VERSION 5.8 ;
DIVIDERCHAR "/" ;
BUSBITCHARS "[]" ;
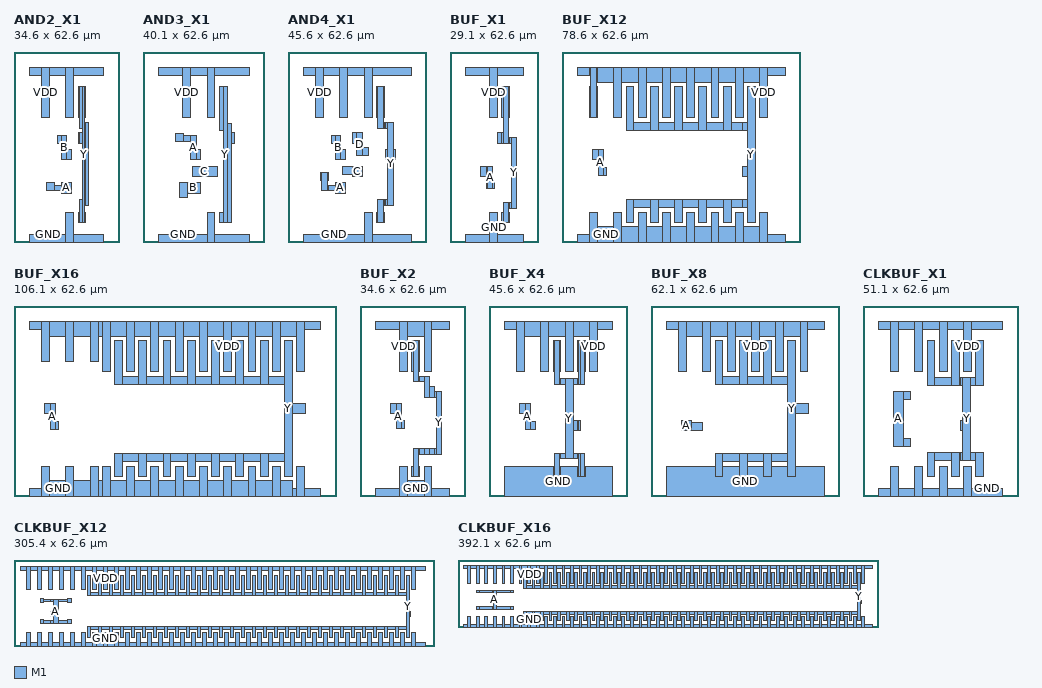
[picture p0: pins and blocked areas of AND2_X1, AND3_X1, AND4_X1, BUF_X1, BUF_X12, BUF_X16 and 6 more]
MACRO AND2_X1
  CLASS CORE ;
  ORIGIN 0 0 ;
  SIZE 34.600 BY 62.600 ;
  SYMMETRY X Y ;
  SITE TR1um_site ;
  PIN VDD
    DIRECTION INOUT ;
    USE POWER ;
    PORT
      LAYER M1 ;
        RECT 5.000 55.000 9.100 57.600 ;
      LAYER M1 ;
        RECT 9.100 41.000 11.700 57.600 ;
      LAYER M1 ;
        RECT 11.700 55.000 17.100 57.600 ;
      LAYER M1 ;
        RECT 17.100 41.000 19.700 57.600 ;
      LAYER M1 ;
        RECT 19.700 55.000 29.600 57.600 ;
    END
  END VDD
  PIN GND
    DIRECTION INOUT ;
    USE GROUND ;
    PORT
      LAYER M1 ;
        RECT 5.000 0.000 17.100 2.600 ;
      LAYER M1 ;
        RECT 17.100 0.000 19.700 9.800 ;
      LAYER M1 ;
        RECT 19.700 0.000 29.600 2.600 ;
    END
  END GND
  PIN Y
    DIRECTION OUTPUT ;
    USE SIGNAL ;
    PORT
      LAYER M1 ;
        RECT 21.100 6.400 21.500 9.800 ;
      LAYER M1 ;
        RECT 21.100 32.600 21.500 36.000 ;
      LAYER M1 ;
        RECT 21.100 41.000 21.500 51.200 ;
      LAYER M1 ;
        RECT 21.500 6.400 22.700 13.900 ;
      LAYER M1 ;
        RECT 21.500 32.600 22.700 36.000 ;
      LAYER M1 ;
        RECT 21.500 37.500 22.700 51.200 ;
      LAYER M1 ;
        RECT 22.700 6.400 23.300 51.200 ;
      LAYER M1 ;
        RECT 23.300 6.400 23.700 9.800 ;
      LAYER M1 ;
        RECT 23.300 12.100 23.700 39.300 ;
      LAYER M1 ;
        RECT 23.300 41.000 23.700 51.200 ;
      LAYER M1 ;
        RECT 23.700 12.100 24.500 39.300 ;
    END
  END Y
  PIN A
    DIRECTION INPUT ;
    USE SIGNAL ;
    PORT
      LAYER M1 ;
        RECT 10.600 16.900 13.200 19.500 ;
      LAYER M1 ;
        RECT 13.200 16.900 15.600 18.700 ;
      LAYER M1 ;
        RECT 15.600 16.100 19.000 19.500 ;
    END
  END A
  PIN B
    DIRECTION INPUT ;
    USE SIGNAL ;
    PORT
      LAYER M1 ;
        RECT 14.400 32.600 15.600 35.200 ;
      LAYER M1 ;
        RECT 15.600 27.100 17.400 35.200 ;
      LAYER M1 ;
        RECT 17.400 27.100 19.000 30.500 ;
    END
  END B
END AND2_X1
MACRO AND3_X1
  CLASS CORE ;
  ORIGIN 0 0 ;
  SIZE 40.100 BY 62.600 ;
  SYMMETRY X Y ;
  SITE TR1um_site ;
  PIN VDD
    DIRECTION INOUT ;
    USE POWER ;
    PORT
      LAYER M1 ;
        RECT 5.000 55.000 13.100 57.600 ;
      LAYER M1 ;
        RECT 13.100 41.000 15.700 57.600 ;
      LAYER M1 ;
        RECT 15.700 55.000 21.100 57.600 ;
      LAYER M1 ;
        RECT 21.100 41.000 23.700 57.600 ;
      LAYER M1 ;
        RECT 23.700 55.000 35.100 57.600 ;
    END
  END VDD
  PIN GND
    DIRECTION INOUT ;
    USE GROUND ;
    PORT
      LAYER M1 ;
        RECT 5.000 0.000 21.100 2.600 ;
      LAYER M1 ;
        RECT 21.100 0.000 23.700 9.800 ;
      LAYER M1 ;
        RECT 23.700 0.000 35.100 2.600 ;
    END
  END GND
  PIN Y
    DIRECTION OUTPUT ;
    USE SIGNAL ;
    PORT
      LAYER M1 ;
        RECT 25.100 6.400 26.600 9.800 ;
      LAYER M1 ;
        RECT 25.100 36.600 26.600 51.200 ;
      LAYER M1 ;
        RECT 26.600 6.400 27.700 51.200 ;
      LAYER M1 ;
        RECT 27.700 6.400 29.200 39.200 ;
      LAYER M1 ;
        RECT 29.200 32.600 30.000 36.000 ;
    END
  END Y
  PIN A
    DIRECTION INPUT ;
    USE SIGNAL ;
    PORT
      LAYER M1 ;
        RECT 10.700 33.200 13.300 35.800 ;
      LAYER M1 ;
        RECT 13.300 33.200 15.600 35.200 ;
      LAYER M1 ;
        RECT 15.600 27.100 17.600 35.200 ;
      LAYER M1 ;
        RECT 17.600 27.100 19.000 30.500 ;
    END
  END A
  PIN C
    DIRECTION INPUT ;
    USE SIGNAL ;
    PORT
      LAYER M1 ;
        RECT 16.300 21.600 24.500 25.000 ;
    END
  END C
  PIN B
    DIRECTION INPUT ;
    USE SIGNAL ;
    PORT
      LAYER M1 ;
        RECT 12.000 14.600 14.600 19.500 ;
      LAYER M1 ;
        RECT 14.600 16.100 19.000 19.500 ;
    END
  END B
END AND3_X1
MACRO AND4_X1
  CLASS CORE ;
  ORIGIN 0 0 ;
  SIZE 45.600 BY 62.600 ;
  SYMMETRY X Y ;
  SITE TR1um_site ;
  PIN VDD
    DIRECTION INOUT ;
    USE POWER ;
    PORT
      LAYER M1 ;
        RECT 5.000 55.000 9.100 57.600 ;
      LAYER M1 ;
        RECT 9.100 41.000 11.700 57.600 ;
      LAYER M1 ;
        RECT 11.700 55.000 17.100 57.600 ;
      LAYER M1 ;
        RECT 17.100 41.000 19.700 57.600 ;
      LAYER M1 ;
        RECT 19.700 55.000 25.100 57.600 ;
      LAYER M1 ;
        RECT 25.100 41.000 27.700 57.600 ;
      LAYER M1 ;
        RECT 27.700 55.000 40.600 57.600 ;
    END
  END VDD
  PIN GND
    DIRECTION INOUT ;
    USE GROUND ;
    PORT
      LAYER M1 ;
        RECT 5.000 0.000 25.100 2.600 ;
      LAYER M1 ;
        RECT 25.100 0.000 27.700 9.800 ;
      LAYER M1 ;
        RECT 27.700 0.000 40.600 2.600 ;
    END
  END GND
  PIN Y
    DIRECTION OUTPUT ;
    USE SIGNAL ;
    PORT
      LAYER M1 ;
        RECT 29.100 6.400 29.500 9.800 ;
      LAYER M1 ;
        RECT 29.100 41.000 29.500 51.200 ;
      LAYER M1 ;
        RECT 29.500 6.400 31.300 13.900 ;
      LAYER M1 ;
        RECT 29.500 37.500 31.300 51.200 ;
      LAYER M1 ;
        RECT 31.300 6.400 31.700 9.800 ;
      LAYER M1 ;
        RECT 31.300 12.100 31.700 13.900 ;
      LAYER M1 ;
        RECT 31.300 37.500 31.700 39.300 ;
      LAYER M1 ;
        RECT 31.300 41.000 31.700 51.200 ;
      LAYER M1 ;
        RECT 31.700 12.100 32.100 13.900 ;
      LAYER M1 ;
        RECT 31.700 37.500 32.100 39.300 ;
      LAYER M1 ;
        RECT 32.100 12.100 32.900 13.900 ;
      LAYER M1 ;
        RECT 32.100 27.100 32.900 30.500 ;
      LAYER M1 ;
        RECT 32.100 37.500 32.900 39.300 ;
      LAYER M1 ;
        RECT 32.900 12.100 34.700 39.300 ;
      LAYER M1 ;
        RECT 34.700 27.100 35.500 30.500 ;
    END
  END Y
  PIN A
    DIRECTION INPUT ;
    USE SIGNAL ;
    PORT
      LAYER M1 ;
        RECT 10.600 20.400 11.100 23.000 ;
      LAYER M1 ;
        RECT 11.100 16.900 12.900 23.000 ;
      LAYER M1 ;
        RECT 12.900 16.900 13.200 18.700 ;
      LAYER M1 ;
        RECT 12.900 20.400 13.200 23.000 ;
      LAYER M1 ;
        RECT 13.200 16.900 15.600 18.700 ;
      LAYER M1 ;
        RECT 15.600 16.100 19.000 19.500 ;
    END
  END A
  PIN B
    DIRECTION INPUT ;
    USE SIGNAL ;
    PORT
      LAYER M1 ;
        RECT 14.400 32.600 15.600 35.200 ;
      LAYER M1 ;
        RECT 15.600 27.100 17.400 35.200 ;
      LAYER M1 ;
        RECT 17.400 27.100 19.000 30.500 ;
    END
  END B
  PIN C
    DIRECTION INPUT ;
    USE SIGNAL ;
    PORT
      LAYER M1 ;
        RECT 17.900 22.400 21.100 25.000 ;
      LAYER M1 ;
        RECT 21.100 21.600 24.500 25.000 ;
    END
  END C
  PIN D
    DIRECTION INPUT ;
    USE SIGNAL ;
    PORT
      LAYER M1 ;
        RECT 21.100 32.600 22.700 36.000 ;
      LAYER M1 ;
        RECT 22.700 28.400 24.500 36.000 ;
      LAYER M1 ;
        RECT 24.500 28.400 26.400 31.000 ;
    END
  END D
END AND4_X1
MACRO BUF_X1
  CLASS CORE ;
  ORIGIN 0 0 ;
  SIZE 29.100 BY 62.600 ;
  SYMMETRY X Y ;
  SITE TR1um_site ;
  PIN VDD
    DIRECTION INOUT ;
    USE POWER ;
    PORT
      LAYER M1 ;
        RECT 5.000 55.000 13.100 57.600 ;
      LAYER M1 ;
        RECT 13.100 41.000 15.700 57.600 ;
      LAYER M1 ;
        RECT 15.700 55.000 24.100 57.600 ;
    END
  END VDD
  PIN GND
    DIRECTION INOUT ;
    USE GROUND ;
    PORT
      LAYER M1 ;
        RECT 5.000 0.000 13.100 2.600 ;
      LAYER M1 ;
        RECT 13.100 0.000 15.700 9.800 ;
      LAYER M1 ;
        RECT 15.700 0.000 24.100 2.600 ;
    END
  END GND
  PIN Y
    DIRECTION OUTPUT ;
    USE SIGNAL ;
    PORT
      LAYER M1 ;
        RECT 15.600 32.600 17.100 36.000 ;
      LAYER M1 ;
        RECT 17.100 6.400 17.500 9.800 ;
      LAYER M1 ;
        RECT 17.100 32.600 17.500 36.000 ;
      LAYER M1 ;
        RECT 17.100 41.000 17.500 51.200 ;
      LAYER M1 ;
        RECT 17.500 6.400 19.300 13.000 ;
      LAYER M1 ;
        RECT 17.500 32.600 19.300 51.200 ;
      LAYER M1 ;
        RECT 19.300 6.400 19.700 9.800 ;
      LAYER M1 ;
        RECT 19.300 11.200 19.700 13.000 ;
      LAYER M1 ;
        RECT 19.300 32.600 19.700 34.400 ;
      LAYER M1 ;
        RECT 19.300 41.000 19.700 51.200 ;
      LAYER M1 ;
        RECT 19.700 11.200 20.100 13.000 ;
      LAYER M1 ;
        RECT 19.700 32.600 20.100 34.400 ;
      LAYER M1 ;
        RECT 20.100 11.200 21.900 34.400 ;
    END
  END Y
  PIN A
    DIRECTION INPUT ;
    USE SIGNAL ;
    PORT
      LAYER M1 ;
        RECT 10.100 21.600 11.900 25.000 ;
      LAYER M1 ;
        RECT 11.900 17.600 12.300 20.200 ;
      LAYER M1 ;
        RECT 11.900 21.600 12.300 25.000 ;
      LAYER M1 ;
        RECT 12.300 17.600 14.100 25.000 ;
      LAYER M1 ;
        RECT 14.100 17.600 14.500 20.200 ;
    END
  END A
END BUF_X1
MACRO BUF_X12
  CLASS CORE ;
  ORIGIN 0 0 ;
  SIZE 78.600 BY 62.600 ;
  SYMMETRY X Y ;
  SITE TR1um_site ;
  PIN VDD
    DIRECTION INOUT ;
    USE POWER ;
    PORT
      LAYER M1 ;
        RECT 5.000 55.000 9.100 57.600 ;
      LAYER M1 ;
        RECT 9.100 41.000 9.500 51.200 ;
      LAYER M1 ;
        RECT 9.100 55.000 9.500 57.600 ;
      LAYER M1 ;
        RECT 9.500 41.000 11.300 57.600 ;
      LAYER M1 ;
        RECT 11.300 41.000 11.700 51.200 ;
      LAYER M1 ;
        RECT 11.300 52.600 11.700 57.600 ;
      LAYER M1 ;
        RECT 11.700 52.600 17.100 57.600 ;
      LAYER M1 ;
        RECT 17.100 41.000 19.700 57.600 ;
      LAYER M1 ;
        RECT 19.700 52.600 25.100 57.600 ;
      LAYER M1 ;
        RECT 25.100 41.000 27.700 57.600 ;
      LAYER M1 ;
        RECT 27.700 52.600 33.100 57.600 ;
      LAYER M1 ;
        RECT 33.100 41.000 35.700 57.600 ;
      LAYER M1 ;
        RECT 35.700 52.600 41.100 57.600 ;
      LAYER M1 ;
        RECT 41.100 41.000 43.700 57.600 ;
      LAYER M1 ;
        RECT 43.700 52.600 49.100 57.600 ;
      LAYER M1 ;
        RECT 49.100 41.000 51.700 57.600 ;
      LAYER M1 ;
        RECT 51.700 52.600 57.100 57.600 ;
      LAYER M1 ;
        RECT 57.100 41.000 59.700 57.600 ;
      LAYER M1 ;
        RECT 59.700 52.600 65.100 57.600 ;
      LAYER M1 ;
        RECT 65.100 41.000 67.700 57.600 ;
      LAYER M1 ;
        RECT 67.700 55.000 73.600 57.600 ;
    END
  END VDD
  PIN GND
    DIRECTION INOUT ;
    USE GROUND ;
    PORT
      LAYER M1 ;
        RECT 5.000 0.000 9.100 2.600 ;
      LAYER M1 ;
        RECT 9.100 0.000 11.700 9.800 ;
      LAYER M1 ;
        RECT 11.700 0.000 17.100 5.000 ;
      LAYER M1 ;
        RECT 17.100 0.000 19.700 9.800 ;
      LAYER M1 ;
        RECT 19.700 0.000 25.100 5.000 ;
      LAYER M1 ;
        RECT 25.100 0.000 27.700 9.800 ;
      LAYER M1 ;
        RECT 27.700 0.000 33.100 5.000 ;
      LAYER M1 ;
        RECT 33.100 0.000 35.700 9.800 ;
      LAYER M1 ;
        RECT 35.700 0.000 41.100 5.000 ;
      LAYER M1 ;
        RECT 41.100 0.000 43.700 9.800 ;
      LAYER M1 ;
        RECT 43.700 0.000 49.100 5.000 ;
      LAYER M1 ;
        RECT 49.100 0.000 51.700 9.800 ;
      LAYER M1 ;
        RECT 51.700 0.000 57.100 5.000 ;
      LAYER M1 ;
        RECT 57.100 0.000 59.700 9.800 ;
      LAYER M1 ;
        RECT 59.700 0.000 65.100 5.000 ;
      LAYER M1 ;
        RECT 65.100 0.000 67.700 9.800 ;
      LAYER M1 ;
        RECT 67.700 0.000 73.600 2.600 ;
    END
  END GND
  PIN Y
    DIRECTION OUTPUT ;
    USE SIGNAL ;
    PORT
      LAYER M1 ;
        RECT 21.100 6.400 23.700 14.000 ;
      LAYER M1 ;
        RECT 21.100 36.800 23.700 51.200 ;
      LAYER M1 ;
        RECT 23.700 11.400 29.100 14.000 ;
      LAYER M1 ;
        RECT 23.700 36.800 29.100 39.400 ;
      LAYER M1 ;
        RECT 29.100 6.400 31.700 14.000 ;
      LAYER M1 ;
        RECT 29.100 36.800 31.700 51.200 ;
      LAYER M1 ;
        RECT 31.700 11.400 37.100 14.000 ;
      LAYER M1 ;
        RECT 31.700 36.800 37.100 39.400 ;
      LAYER M1 ;
        RECT 37.100 6.400 39.700 14.000 ;
      LAYER M1 ;
        RECT 37.100 36.800 39.700 51.200 ;
      LAYER M1 ;
        RECT 39.700 11.400 45.100 14.000 ;
      LAYER M1 ;
        RECT 39.700 36.800 45.100 39.400 ;
      LAYER M1 ;
        RECT 45.100 6.400 47.700 14.000 ;
      LAYER M1 ;
        RECT 45.100 36.800 47.700 51.200 ;
      LAYER M1 ;
        RECT 47.700 11.400 53.100 14.000 ;
      LAYER M1 ;
        RECT 47.700 36.800 53.100 39.400 ;
      LAYER M1 ;
        RECT 53.100 6.400 55.700 14.000 ;
      LAYER M1 ;
        RECT 53.100 36.800 55.700 51.200 ;
      LAYER M1 ;
        RECT 55.700 11.400 59.600 14.000 ;
      LAYER M1 ;
        RECT 55.700 36.800 59.600 39.400 ;
      LAYER M1 ;
        RECT 59.600 11.400 61.100 14.000 ;
      LAYER M1 ;
        RECT 59.600 21.600 61.100 25.000 ;
      LAYER M1 ;
        RECT 59.600 36.800 61.100 39.400 ;
      LAYER M1 ;
        RECT 61.100 6.400 63.700 51.200 ;
    END
  END Y
  PIN A
    DIRECTION INPUT ;
    USE SIGNAL ;
    PORT
      LAYER M1 ;
        RECT 10.100 27.100 11.900 30.500 ;
      LAYER M1 ;
        RECT 11.900 22.000 13.700 30.500 ;
      LAYER M1 ;
        RECT 13.700 22.000 14.500 24.600 ;
    END
  END A
END BUF_X12
MACRO BUF_X16
  CLASS CORE ;
  ORIGIN 0 0 ;
  SIZE 106.100 BY 62.600 ;
  SYMMETRY X Y ;
  SITE TR1um_site ;
  PIN VDD
    DIRECTION INOUT ;
    USE POWER ;
    PORT
      LAYER M1 ;
        RECT 5.000 55.000 9.100 57.600 ;
      LAYER M1 ;
        RECT 9.100 44.400 11.700 57.600 ;
      LAYER M1 ;
        RECT 11.700 52.600 17.100 57.600 ;
      LAYER M1 ;
        RECT 17.100 44.400 19.700 57.600 ;
      LAYER M1 ;
        RECT 19.700 52.600 25.100 57.600 ;
      LAYER M1 ;
        RECT 25.100 44.400 27.700 57.600 ;
      LAYER M1 ;
        RECT 27.700 52.600 29.100 57.600 ;
      LAYER M1 ;
        RECT 29.100 41.000 31.700 57.600 ;
      LAYER M1 ;
        RECT 31.700 52.600 37.100 57.600 ;
      LAYER M1 ;
        RECT 37.100 41.000 39.700 57.600 ;
      LAYER M1 ;
        RECT 39.700 52.600 45.100 57.600 ;
      LAYER M1 ;
        RECT 45.100 41.000 47.700 57.600 ;
      LAYER M1 ;
        RECT 47.700 52.600 53.100 57.600 ;
      LAYER M1 ;
        RECT 53.100 41.000 55.700 57.600 ;
      LAYER M1 ;
        RECT 55.700 52.600 61.100 57.600 ;
      LAYER M1 ;
        RECT 61.100 41.000 63.700 57.600 ;
      LAYER M1 ;
        RECT 63.700 52.600 69.100 57.600 ;
      LAYER M1 ;
        RECT 69.100 41.000 71.700 57.600 ;
      LAYER M1 ;
        RECT 71.700 52.600 77.100 57.600 ;
      LAYER M1 ;
        RECT 77.100 41.000 79.700 57.600 ;
      LAYER M1 ;
        RECT 79.700 52.600 85.100 57.600 ;
      LAYER M1 ;
        RECT 85.100 41.000 87.700 57.600 ;
      LAYER M1 ;
        RECT 87.700 52.600 93.100 57.600 ;
      LAYER M1 ;
        RECT 93.100 41.000 95.700 57.600 ;
      LAYER M1 ;
        RECT 95.700 55.000 101.100 57.600 ;
    END
  END VDD
  PIN Y
    DIRECTION OUTPUT ;
    USE SIGNAL ;
    PORT
      LAYER M1 ;
        RECT 33.100 6.400 35.700 14.000 ;
      LAYER M1 ;
        RECT 33.100 36.800 35.700 51.200 ;
      LAYER M1 ;
        RECT 35.700 11.400 41.100 14.000 ;
      LAYER M1 ;
        RECT 35.700 36.800 41.100 39.400 ;
      LAYER M1 ;
        RECT 41.100 6.400 43.700 14.000 ;
      LAYER M1 ;
        RECT 41.100 36.800 43.700 51.200 ;
      LAYER M1 ;
        RECT 43.700 11.400 49.100 14.000 ;
      LAYER M1 ;
        RECT 43.700 36.800 49.100 39.400 ;
      LAYER M1 ;
        RECT 49.100 6.400 51.700 14.000 ;
      LAYER M1 ;
        RECT 49.100 36.800 51.700 51.200 ;
      LAYER M1 ;
        RECT 51.700 11.400 57.100 14.000 ;
      LAYER M1 ;
        RECT 51.700 36.800 57.100 39.400 ;
      LAYER M1 ;
        RECT 57.100 6.400 59.700 14.000 ;
      LAYER M1 ;
        RECT 57.100 36.800 59.700 51.200 ;
      LAYER M1 ;
        RECT 59.700 11.400 65.100 14.000 ;
      LAYER M1 ;
        RECT 59.700 36.800 65.100 39.400 ;
      LAYER M1 ;
        RECT 65.100 6.400 67.700 14.000 ;
      LAYER M1 ;
        RECT 65.100 36.800 67.700 51.200 ;
      LAYER M1 ;
        RECT 67.700 11.400 73.100 14.000 ;
      LAYER M1 ;
        RECT 67.700 36.800 73.100 39.400 ;
      LAYER M1 ;
        RECT 73.100 6.400 75.700 14.000 ;
      LAYER M1 ;
        RECT 73.100 36.800 75.700 51.200 ;
      LAYER M1 ;
        RECT 75.700 11.400 81.100 14.000 ;
      LAYER M1 ;
        RECT 75.700 36.800 81.100 39.400 ;
      LAYER M1 ;
        RECT 81.100 6.400 83.700 14.000 ;
      LAYER M1 ;
        RECT 81.100 36.800 83.700 51.200 ;
      LAYER M1 ;
        RECT 83.700 11.400 89.100 14.000 ;
      LAYER M1 ;
        RECT 83.700 36.800 89.100 39.400 ;
      LAYER M1 ;
        RECT 89.100 6.400 91.700 51.200 ;
      LAYER M1 ;
        RECT 91.700 27.100 96.000 30.500 ;
    END
  END Y
  PIN A
    DIRECTION INPUT ;
    USE SIGNAL ;
    PORT
      LAYER M1 ;
        RECT 10.100 27.100 11.900 30.500 ;
      LAYER M1 ;
        RECT 11.900 22.000 13.700 30.500 ;
      LAYER M1 ;
        RECT 13.700 22.000 14.500 24.600 ;
    END
  END A
  PIN GND
    DIRECTION INOUT ;
    USE GROUND ;
    PORT
      LAYER M1 ;
        RECT 5.000 0.000 9.100 2.600 ;
      LAYER M1 ;
        RECT 9.100 0.000 11.700 9.800 ;
      LAYER M1 ;
        RECT 11.700 0.000 17.100 5.000 ;
      LAYER M1 ;
        RECT 17.100 0.000 19.700 9.800 ;
      LAYER M1 ;
        RECT 19.700 0.000 25.100 5.000 ;
      LAYER M1 ;
        RECT 25.100 0.000 27.700 9.800 ;
      LAYER M1 ;
        RECT 27.700 0.000 29.100 5.000 ;
      LAYER M1 ;
        RECT 29.100 0.000 31.700 9.800 ;
      LAYER M1 ;
        RECT 31.700 0.000 37.100 5.000 ;
      LAYER M1 ;
        RECT 37.100 0.000 39.700 9.800 ;
      LAYER M1 ;
        RECT 39.700 0.000 45.100 5.000 ;
      LAYER M1 ;
        RECT 45.100 0.000 47.700 9.800 ;
      LAYER M1 ;
        RECT 47.700 0.000 53.100 5.000 ;
      LAYER M1 ;
        RECT 53.100 0.000 55.700 9.800 ;
      LAYER M1 ;
        RECT 55.700 0.000 61.100 5.000 ;
      LAYER M1 ;
        RECT 61.100 0.000 63.700 9.800 ;
      LAYER M1 ;
        RECT 63.700 0.000 69.100 5.000 ;
      LAYER M1 ;
        RECT 69.100 0.000 71.700 9.800 ;
      LAYER M1 ;
        RECT 71.700 0.000 77.100 5.000 ;
      LAYER M1 ;
        RECT 77.100 0.000 79.700 9.800 ;
      LAYER M1 ;
        RECT 79.700 0.000 85.100 5.000 ;
      LAYER M1 ;
        RECT 85.100 0.000 87.700 9.800 ;
      LAYER M1 ;
        RECT 87.700 0.000 91.700 5.000 ;
      LAYER M1 ;
        RECT 91.700 0.000 93.100 2.600 ;
      LAYER M1 ;
        RECT 93.100 0.000 95.700 9.800 ;
      LAYER M1 ;
        RECT 95.700 0.000 101.100 2.600 ;
    END
  END GND
END BUF_X16
MACRO BUF_X2
  CLASS CORE ;
  ORIGIN 0 0 ;
  SIZE 34.600 BY 62.600 ;
  SYMMETRY X Y ;
  SITE TR1um_site ;
  PIN Y
    DIRECTION OUTPUT ;
    USE SIGNAL ;
    PORT
      LAYER M1 ;
        RECT 17.100 6.400 17.500 9.800 ;
      LAYER M1 ;
        RECT 17.100 41.000 17.500 51.200 ;
      LAYER M1 ;
        RECT 17.500 6.400 19.300 15.600 ;
      LAYER M1 ;
        RECT 17.500 37.700 19.300 51.200 ;
      LAYER M1 ;
        RECT 19.300 6.400 19.700 9.800 ;
      LAYER M1 ;
        RECT 19.300 13.800 19.700 15.600 ;
      LAYER M1 ;
        RECT 19.300 37.700 19.700 39.500 ;
      LAYER M1 ;
        RECT 19.300 41.000 19.700 51.200 ;
      LAYER M1 ;
        RECT 19.700 13.800 21.100 15.600 ;
      LAYER M1 ;
        RECT 19.700 37.700 21.100 39.500 ;
      LAYER M1 ;
        RECT 21.100 13.800 22.900 15.600 ;
      LAYER M1 ;
        RECT 21.100 32.600 22.900 39.500 ;
      LAYER M1 ;
        RECT 22.900 13.800 24.500 15.600 ;
      LAYER M1 ;
        RECT 22.900 32.600 24.500 36.000 ;
      LAYER M1 ;
        RECT 24.500 13.800 25.100 15.600 ;
      LAYER M1 ;
        RECT 24.500 32.600 25.100 34.400 ;
      LAYER M1 ;
        RECT 25.100 13.800 26.900 34.400 ;
    END
  END Y
  PIN A
    DIRECTION INPUT ;
    USE SIGNAL ;
    PORT
      LAYER M1 ;
        RECT 10.100 27.100 11.900 30.500 ;
      LAYER M1 ;
        RECT 11.900 22.200 13.700 30.500 ;
      LAYER M1 ;
        RECT 13.700 22.200 14.500 24.800 ;
    END
  END A
  PIN VDD
    DIRECTION INOUT ;
    USE POWER ;
    PORT
      LAYER M1 ;
        RECT 5.000 55.000 13.100 57.600 ;
      LAYER M1 ;
        RECT 13.100 41.000 15.700 57.600 ;
      LAYER M1 ;
        RECT 15.700 52.600 21.100 57.600 ;
      LAYER M1 ;
        RECT 21.100 41.000 23.700 57.600 ;
      LAYER M1 ;
        RECT 23.700 55.000 29.600 57.600 ;
    END
  END VDD
  PIN GND
    DIRECTION INOUT ;
    USE GROUND ;
    PORT
      LAYER M1 ;
        RECT 5.000 0.000 13.100 2.600 ;
      LAYER M1 ;
        RECT 13.100 0.000 15.700 9.800 ;
      LAYER M1 ;
        RECT 15.700 0.000 21.100 5.000 ;
      LAYER M1 ;
        RECT 21.100 0.000 23.700 9.800 ;
      LAYER M1 ;
        RECT 23.700 0.000 29.600 2.600 ;
    END
  END GND
END BUF_X2
MACRO BUF_X4
  CLASS CORE ;
  ORIGIN 0 0 ;
  SIZE 45.600 BY 62.600 ;
  SYMMETRY X Y ;
  SITE TR1um_site ;
  PIN Y
    DIRECTION OUTPUT ;
    USE SIGNAL ;
    PORT
      LAYER M1 ;
        RECT 21.100 6.400 21.500 9.800 ;
      LAYER M1 ;
        RECT 21.100 41.000 21.500 51.200 ;
      LAYER M1 ;
        RECT 21.500 6.400 23.300 14.000 ;
      LAYER M1 ;
        RECT 21.500 36.800 23.300 51.200 ;
      LAYER M1 ;
        RECT 23.300 6.400 23.700 9.800 ;
      LAYER M1 ;
        RECT 23.300 12.200 23.700 14.000 ;
      LAYER M1 ;
        RECT 23.300 36.800 23.700 38.600 ;
      LAYER M1 ;
        RECT 23.300 41.000 23.700 51.200 ;
      LAYER M1 ;
        RECT 23.700 12.200 25.100 14.000 ;
      LAYER M1 ;
        RECT 23.700 36.800 25.100 38.600 ;
      LAYER M1 ;
        RECT 25.100 12.200 27.700 38.600 ;
      LAYER M1 ;
        RECT 27.700 12.200 29.100 14.000 ;
      LAYER M1 ;
        RECT 27.700 21.600 29.100 25.000 ;
      LAYER M1 ;
        RECT 27.700 36.800 29.100 38.600 ;
      LAYER M1 ;
        RECT 29.100 6.400 29.500 9.800 ;
      LAYER M1 ;
        RECT 29.100 12.200 29.500 14.000 ;
      LAYER M1 ;
        RECT 29.100 21.600 29.500 25.000 ;
      LAYER M1 ;
        RECT 29.100 36.800 29.500 38.600 ;
      LAYER M1 ;
        RECT 29.100 41.000 29.500 51.200 ;
      LAYER M1 ;
        RECT 29.500 6.400 30.000 14.000 ;
      LAYER M1 ;
        RECT 29.500 21.600 30.000 25.000 ;
      LAYER M1 ;
        RECT 29.500 36.800 30.000 51.200 ;
      LAYER M1 ;
        RECT 30.000 6.400 31.300 14.000 ;
      LAYER M1 ;
        RECT 30.000 36.800 31.300 51.200 ;
      LAYER M1 ;
        RECT 31.300 6.400 31.700 9.800 ;
      LAYER M1 ;
        RECT 31.300 41.000 31.700 51.200 ;
    END
  END Y
  PIN A
    DIRECTION INPUT ;
    USE SIGNAL ;
    PORT
      LAYER M1 ;
        RECT 10.100 27.100 11.900 30.500 ;
      LAYER M1 ;
        RECT 11.900 22.000 13.700 30.500 ;
      LAYER M1 ;
        RECT 13.700 22.000 15.400 24.600 ;
    END
  END A
  PIN VDD
    DIRECTION INOUT ;
    USE POWER ;
    PORT
      LAYER M1 ;
        RECT 5.000 55.000 9.100 57.600 ;
      LAYER M1 ;
        RECT 9.100 41.000 11.700 57.600 ;
      LAYER M1 ;
        RECT 11.700 52.600 17.100 57.600 ;
      LAYER M1 ;
        RECT 17.100 41.000 19.700 57.600 ;
      LAYER M1 ;
        RECT 19.700 52.600 25.100 57.600 ;
      LAYER M1 ;
        RECT 25.100 41.000 27.700 57.600 ;
      LAYER M1 ;
        RECT 27.700 52.600 33.100 57.600 ;
      LAYER M1 ;
        RECT 33.100 41.000 35.700 57.600 ;
      LAYER M1 ;
        RECT 35.700 55.000 40.600 57.600 ;
    END
  END VDD
  PIN GND
    DIRECTION INOUT ;
    USE GROUND ;
    PORT
      LAYER M1 ;
        RECT 5.000 0.000 40.600 9.800 ;
    END
  END GND
END BUF_X4
MACRO BUF_X8
  CLASS CORE ;
  ORIGIN 0 0 ;
  SIZE 62.100 BY 62.600 ;
  SYMMETRY X Y ;
  SITE TR1um_site ;
  PIN Y
    DIRECTION OUTPUT ;
    USE SIGNAL ;
    PORT
      LAYER M1 ;
        RECT 21.100 6.400 23.700 14.000 ;
      LAYER M1 ;
        RECT 21.100 36.800 23.700 51.200 ;
      LAYER M1 ;
        RECT 23.700 11.400 29.100 14.000 ;
      LAYER M1 ;
        RECT 23.700 36.800 29.100 39.400 ;
      LAYER M1 ;
        RECT 29.100 6.400 31.700 14.000 ;
      LAYER M1 ;
        RECT 29.100 36.800 31.700 51.200 ;
      LAYER M1 ;
        RECT 31.700 11.400 37.100 14.000 ;
      LAYER M1 ;
        RECT 31.700 36.800 37.100 39.400 ;
      LAYER M1 ;
        RECT 37.100 6.400 39.700 14.000 ;
      LAYER M1 ;
        RECT 37.100 36.800 39.700 51.200 ;
      LAYER M1 ;
        RECT 39.700 11.400 45.100 14.000 ;
      LAYER M1 ;
        RECT 39.700 36.800 45.100 39.400 ;
      LAYER M1 ;
        RECT 45.100 6.400 47.700 51.200 ;
      LAYER M1 ;
        RECT 47.700 27.100 52.000 30.500 ;
    END
  END Y
  PIN A
    DIRECTION INPUT ;
    USE SIGNAL ;
    PORT
      LAYER M1 ;
        RECT 10.100 21.600 13.500 25.000 ;
      LAYER M1 ;
        RECT 13.500 21.600 16.900 24.200 ;
    END
  END A
  PIN VDD
    DIRECTION INOUT ;
    USE POWER ;
    PORT
      LAYER M1 ;
        RECT 5.000 55.000 9.100 57.600 ;
      LAYER M1 ;
        RECT 9.100 41.000 11.700 57.600 ;
      LAYER M1 ;
        RECT 11.700 52.600 17.100 57.600 ;
      LAYER M1 ;
        RECT 17.100 41.000 19.700 57.600 ;
      LAYER M1 ;
        RECT 19.700 52.600 25.100 57.600 ;
      LAYER M1 ;
        RECT 25.100 41.000 27.700 57.600 ;
      LAYER M1 ;
        RECT 27.700 52.600 33.100 57.600 ;
      LAYER M1 ;
        RECT 33.100 41.000 35.700 57.600 ;
      LAYER M1 ;
        RECT 35.700 52.600 41.100 57.600 ;
      LAYER M1 ;
        RECT 41.100 41.000 43.700 57.600 ;
      LAYER M1 ;
        RECT 43.700 52.600 49.100 57.600 ;
      LAYER M1 ;
        RECT 49.100 41.000 51.700 57.600 ;
      LAYER M1 ;
        RECT 51.700 55.000 57.100 57.600 ;
    END
  END VDD
  PIN GND
    DIRECTION INOUT ;
    USE GROUND ;
    PORT
      LAYER M1 ;
        RECT 5.000 0.000 57.100 9.800 ;
    END
  END GND
END BUF_X8
MACRO CLKBUF_X1
  CLASS CORE ;
  ORIGIN 0 0 ;
  SIZE 51.100 BY 62.600 ;
  SYMMETRY X Y ;
  SITE TR1um_site ;
  PIN VDD
    DIRECTION INOUT ;
    USE POWER ;
    PORT
      LAYER M1 ;
        RECT 5.000 55.000 9.100 57.600 ;
      LAYER M1 ;
        RECT 9.100 41.000 11.700 57.600 ;
      LAYER M1 ;
        RECT 11.700 55.000 17.100 57.600 ;
      LAYER M1 ;
        RECT 17.100 41.000 19.700 57.600 ;
      LAYER M1 ;
        RECT 19.700 55.000 25.100 57.600 ;
      LAYER M1 ;
        RECT 25.100 41.000 27.700 57.600 ;
      LAYER M1 ;
        RECT 27.700 55.000 33.100 57.600 ;
      LAYER M1 ;
        RECT 33.100 41.000 35.700 57.600 ;
      LAYER M1 ;
        RECT 35.700 55.000 46.100 57.600 ;
    END
  END VDD
  PIN A
    DIRECTION INPUT ;
    USE SIGNAL ;
    PORT
      LAYER M1 ;
        RECT 10.100 16.400 13.500 34.400 ;
      LAYER M1 ;
        RECT 13.500 16.400 15.700 19.000 ;
      LAYER M1 ;
        RECT 13.500 31.800 15.700 34.400 ;
    END
  END A
  PIN GND
    DIRECTION INOUT ;
    USE GROUND ;
    PORT
      LAYER M1 ;
        RECT 5.000 0.000 9.100 2.600 ;
      LAYER M1 ;
        RECT 9.100 0.000 11.700 9.800 ;
      LAYER M1 ;
        RECT 11.700 0.000 17.100 2.600 ;
      LAYER M1 ;
        RECT 17.100 0.000 19.700 9.800 ;
      LAYER M1 ;
        RECT 19.700 0.000 25.100 2.600 ;
      LAYER M1 ;
        RECT 25.100 0.000 27.700 9.800 ;
      LAYER M1 ;
        RECT 27.700 0.000 33.100 2.600 ;
      LAYER M1 ;
        RECT 33.100 0.000 35.700 9.800 ;
      LAYER M1 ;
        RECT 35.700 0.000 46.100 2.600 ;
    END
  END GND
  PIN Y
    DIRECTION OUTPUT ;
    USE SIGNAL ;
    PORT
      LAYER M1 ;
        RECT 21.100 6.400 23.700 14.400 ;
      LAYER M1 ;
        RECT 21.100 36.400 23.700 51.200 ;
      LAYER M1 ;
        RECT 23.700 11.800 29.100 14.400 ;
      LAYER M1 ;
        RECT 23.700 36.400 29.100 39.000 ;
      LAYER M1 ;
        RECT 29.100 6.400 31.700 14.400 ;
      LAYER M1 ;
        RECT 29.100 36.400 31.700 51.200 ;
      LAYER M1 ;
        RECT 31.700 11.800 32.100 14.400 ;
      LAYER M1 ;
        RECT 31.700 36.400 32.100 39.000 ;
      LAYER M1 ;
        RECT 32.100 11.800 32.900 14.400 ;
      LAYER M1 ;
        RECT 32.100 21.600 32.900 25.000 ;
      LAYER M1 ;
        RECT 32.100 36.400 32.900 39.000 ;
      LAYER M1 ;
        RECT 32.900 11.800 35.500 39.000 ;
      LAYER M1 ;
        RECT 35.500 11.800 37.100 14.400 ;
      LAYER M1 ;
        RECT 35.500 36.400 37.100 39.000 ;
      LAYER M1 ;
        RECT 37.100 6.400 39.700 14.400 ;
      LAYER M1 ;
        RECT 37.100 36.400 39.700 51.200 ;
    END
  END Y
END CLKBUF_X1
MACRO CLKBUF_X12
  CLASS CORE ;
  ORIGIN 0 0 ;
  SIZE 305.400 BY 62.600 ;
  SYMMETRY X Y ;
  SITE TR1um_site ;
  PIN Y
    DIRECTION OUTPUT ;
    USE SIGNAL ;
    PORT
      LAYER M1 ;
        RECT 53.100 6.400 55.700 14.400 ;
      LAYER M1 ;
        RECT 53.100 36.400 55.700 51.200 ;
      LAYER M1 ;
        RECT 55.700 11.800 61.100 14.400 ;
      LAYER M1 ;
        RECT 55.700 36.400 61.100 39.000 ;
      LAYER M1 ;
        RECT 61.100 6.400 63.700 14.400 ;
      LAYER M1 ;
        RECT 61.100 36.400 63.700 51.200 ;
      LAYER M1 ;
        RECT 63.700 11.800 69.100 14.400 ;
      LAYER M1 ;
        RECT 63.700 36.400 69.100 39.000 ;
      LAYER M1 ;
        RECT 69.100 6.400 71.700 14.400 ;
      LAYER M1 ;
        RECT 69.100 36.400 71.700 51.200 ;
      LAYER M1 ;
        RECT 71.700 11.800 77.100 14.400 ;
      LAYER M1 ;
        RECT 71.700 36.400 77.100 39.000 ;
      LAYER M1 ;
        RECT 77.100 6.400 79.700 14.400 ;
      LAYER M1 ;
        RECT 77.100 36.400 79.700 51.200 ;
      LAYER M1 ;
        RECT 79.700 11.800 85.100 14.400 ;
      LAYER M1 ;
        RECT 79.700 36.400 85.100 39.000 ;
      LAYER M1 ;
        RECT 85.100 6.400 87.700 14.400 ;
      LAYER M1 ;
        RECT 85.100 36.400 87.700 51.200 ;
      LAYER M1 ;
        RECT 87.700 11.800 93.100 14.400 ;
      LAYER M1 ;
        RECT 87.700 36.400 93.100 39.000 ;
      LAYER M1 ;
        RECT 93.100 6.400 95.700 14.400 ;
      LAYER M1 ;
        RECT 93.100 36.400 95.700 51.200 ;
      LAYER M1 ;
        RECT 95.700 11.800 101.100 14.400 ;
      LAYER M1 ;
        RECT 95.700 36.400 101.100 39.000 ;
      LAYER M1 ;
        RECT 101.100 6.400 103.700 14.400 ;
      LAYER M1 ;
        RECT 101.100 36.400 103.700 51.200 ;
      LAYER M1 ;
        RECT 103.700 11.800 109.100 14.400 ;
      LAYER M1 ;
        RECT 103.700 36.400 109.100 39.000 ;
      LAYER M1 ;
        RECT 109.100 6.400 111.700 14.400 ;
      LAYER M1 ;
        RECT 109.100 36.400 111.700 51.200 ;
      LAYER M1 ;
        RECT 111.700 11.800 117.100 14.400 ;
      LAYER M1 ;
        RECT 111.700 36.400 117.100 39.000 ;
      LAYER M1 ;
        RECT 117.100 6.400 119.700 14.400 ;
      LAYER M1 ;
        RECT 117.100 36.400 119.700 51.200 ;
      LAYER M1 ;
        RECT 119.700 11.800 125.100 14.400 ;
      LAYER M1 ;
        RECT 119.700 36.400 125.100 39.000 ;
      LAYER M1 ;
        RECT 125.100 6.400 127.700 14.400 ;
      LAYER M1 ;
        RECT 125.100 36.400 127.700 51.200 ;
      LAYER M1 ;
        RECT 127.700 11.800 133.100 14.400 ;
      LAYER M1 ;
        RECT 127.700 36.400 133.100 39.000 ;
      LAYER M1 ;
        RECT 133.100 6.400 135.700 14.400 ;
      LAYER M1 ;
        RECT 133.100 36.400 135.700 51.200 ;
      LAYER M1 ;
        RECT 135.700 11.800 141.100 14.400 ;
      LAYER M1 ;
        RECT 135.700 36.400 141.100 39.000 ;
      LAYER M1 ;
        RECT 141.100 6.400 143.700 14.400 ;
      LAYER M1 ;
        RECT 141.100 36.400 143.700 51.200 ;
      LAYER M1 ;
        RECT 143.700 11.800 149.100 14.400 ;
      LAYER M1 ;
        RECT 143.700 36.400 149.100 39.000 ;
      LAYER M1 ;
        RECT 149.100 6.400 151.700 14.400 ;
      LAYER M1 ;
        RECT 149.100 36.400 151.700 51.200 ;
      LAYER M1 ;
        RECT 151.700 11.800 157.100 14.400 ;
      LAYER M1 ;
        RECT 151.700 36.400 157.100 39.000 ;
      LAYER M1 ;
        RECT 157.100 6.400 159.700 14.400 ;
      LAYER M1 ;
        RECT 157.100 36.400 159.700 51.200 ;
      LAYER M1 ;
        RECT 159.700 11.800 165.100 14.400 ;
      LAYER M1 ;
        RECT 159.700 36.400 165.100 39.000 ;
      LAYER M1 ;
        RECT 165.100 6.400 167.700 14.400 ;
      LAYER M1 ;
        RECT 165.100 36.400 167.700 51.200 ;
      LAYER M1 ;
        RECT 167.700 11.800 173.100 14.400 ;
      LAYER M1 ;
        RECT 167.700 36.400 173.100 39.000 ;
      LAYER M1 ;
        RECT 173.100 6.400 175.700 14.400 ;
      LAYER M1 ;
        RECT 173.100 36.400 175.700 51.200 ;
      LAYER M1 ;
        RECT 175.700 11.800 181.100 14.400 ;
      LAYER M1 ;
        RECT 175.700 36.400 181.100 39.000 ;
      LAYER M1 ;
        RECT 181.100 6.400 183.700 14.400 ;
      LAYER M1 ;
        RECT 181.100 36.400 183.700 51.200 ;
      LAYER M1 ;
        RECT 183.700 11.800 189.100 14.400 ;
      LAYER M1 ;
        RECT 183.700 36.400 189.100 39.000 ;
      LAYER M1 ;
        RECT 189.100 6.400 191.700 14.400 ;
      LAYER M1 ;
        RECT 189.100 36.400 191.700 51.200 ;
      LAYER M1 ;
        RECT 191.700 11.800 197.100 14.400 ;
      LAYER M1 ;
        RECT 191.700 36.400 197.100 39.000 ;
      LAYER M1 ;
        RECT 197.100 6.400 199.700 14.400 ;
      LAYER M1 ;
        RECT 197.100 36.400 199.700 51.200 ;
      LAYER M1 ;
        RECT 199.700 11.800 205.100 14.400 ;
      LAYER M1 ;
        RECT 199.700 36.400 205.100 39.000 ;
      LAYER M1 ;
        RECT 205.100 6.400 207.700 14.400 ;
      LAYER M1 ;
        RECT 205.100 36.400 207.700 51.200 ;
      LAYER M1 ;
        RECT 207.700 11.800 213.100 14.400 ;
      LAYER M1 ;
        RECT 207.700 36.400 213.100 39.000 ;
      LAYER M1 ;
        RECT 213.100 6.400 215.700 14.400 ;
      LAYER M1 ;
        RECT 213.100 36.400 215.700 51.200 ;
      LAYER M1 ;
        RECT 215.700 11.800 221.100 14.400 ;
      LAYER M1 ;
        RECT 215.700 36.400 221.100 39.000 ;
      LAYER M1 ;
        RECT 221.100 6.400 223.700 14.400 ;
      LAYER M1 ;
        RECT 221.100 36.400 223.700 51.200 ;
      LAYER M1 ;
        RECT 223.700 11.800 229.100 14.400 ;
      LAYER M1 ;
        RECT 223.700 36.400 229.100 39.000 ;
      LAYER M1 ;
        RECT 229.100 6.400 231.700 14.400 ;
      LAYER M1 ;
        RECT 229.100 36.400 231.700 51.200 ;
      LAYER M1 ;
        RECT 231.700 11.800 237.100 14.400 ;
      LAYER M1 ;
        RECT 231.700 36.400 237.100 39.000 ;
      LAYER M1 ;
        RECT 237.100 6.400 239.700 14.400 ;
      LAYER M1 ;
        RECT 237.100 36.400 239.700 51.200 ;
      LAYER M1 ;
        RECT 239.700 11.800 245.100 14.400 ;
      LAYER M1 ;
        RECT 239.700 36.400 245.100 39.000 ;
      LAYER M1 ;
        RECT 245.100 6.400 247.700 14.400 ;
      LAYER M1 ;
        RECT 245.100 36.400 247.700 51.200 ;
      LAYER M1 ;
        RECT 247.700 11.800 253.100 14.400 ;
      LAYER M1 ;
        RECT 247.700 36.400 253.100 39.000 ;
      LAYER M1 ;
        RECT 253.100 6.400 255.700 14.400 ;
      LAYER M1 ;
        RECT 253.100 36.400 255.700 51.200 ;
      LAYER M1 ;
        RECT 255.700 11.800 261.100 14.400 ;
      LAYER M1 ;
        RECT 255.700 36.400 261.100 39.000 ;
      LAYER M1 ;
        RECT 261.100 6.400 263.700 14.400 ;
      LAYER M1 ;
        RECT 261.100 36.400 263.700 51.200 ;
      LAYER M1 ;
        RECT 263.700 11.800 269.100 14.400 ;
      LAYER M1 ;
        RECT 263.700 36.400 269.100 39.000 ;
      LAYER M1 ;
        RECT 269.100 6.400 271.700 14.400 ;
      LAYER M1 ;
        RECT 269.100 36.400 271.700 51.200 ;
      LAYER M1 ;
        RECT 271.700 11.800 277.100 14.400 ;
      LAYER M1 ;
        RECT 271.700 36.400 277.100 39.000 ;
      LAYER M1 ;
        RECT 277.100 6.400 279.700 14.400 ;
      LAYER M1 ;
        RECT 277.100 36.400 279.700 51.200 ;
      LAYER M1 ;
        RECT 279.700 11.800 285.100 14.400 ;
      LAYER M1 ;
        RECT 279.700 36.400 285.100 39.000 ;
      LAYER M1 ;
        RECT 285.100 6.400 287.700 51.200 ;
      LAYER M1 ;
        RECT 287.700 21.600 288.500 25.000 ;
    END
  END Y
  PIN VDD
    DIRECTION INOUT ;
    USE POWER ;
    PORT
      LAYER M1 ;
        RECT 5.000 55.000 9.100 57.600 ;
      LAYER M1 ;
        RECT 9.100 41.000 11.700 57.600 ;
      LAYER M1 ;
        RECT 11.700 55.000 17.100 57.600 ;
      LAYER M1 ;
        RECT 17.100 41.000 19.700 57.600 ;
      LAYER M1 ;
        RECT 19.700 55.000 25.100 57.600 ;
      LAYER M1 ;
        RECT 25.100 41.000 27.700 57.600 ;
      LAYER M1 ;
        RECT 27.700 55.000 33.100 57.600 ;
      LAYER M1 ;
        RECT 33.100 41.000 35.700 57.600 ;
      LAYER M1 ;
        RECT 35.700 55.000 41.100 57.600 ;
      LAYER M1 ;
        RECT 41.100 41.000 43.700 57.600 ;
      LAYER M1 ;
        RECT 43.700 55.000 49.100 57.600 ;
      LAYER M1 ;
        RECT 49.100 41.000 51.700 57.600 ;
      LAYER M1 ;
        RECT 51.700 55.000 57.100 57.600 ;
      LAYER M1 ;
        RECT 57.100 41.000 59.700 57.600 ;
      LAYER M1 ;
        RECT 59.700 55.000 65.100 57.600 ;
      LAYER M1 ;
        RECT 65.100 41.000 67.700 57.600 ;
      LAYER M1 ;
        RECT 67.700 55.000 73.100 57.600 ;
      LAYER M1 ;
        RECT 73.100 41.000 75.700 57.600 ;
      LAYER M1 ;
        RECT 75.700 55.000 81.100 57.600 ;
      LAYER M1 ;
        RECT 81.100 41.000 83.700 57.600 ;
      LAYER M1 ;
        RECT 83.700 55.000 89.100 57.600 ;
      LAYER M1 ;
        RECT 89.100 41.000 91.700 57.600 ;
      LAYER M1 ;
        RECT 91.700 55.000 97.100 57.600 ;
      LAYER M1 ;
        RECT 97.100 41.000 99.700 57.600 ;
      LAYER M1 ;
        RECT 99.700 55.000 105.100 57.600 ;
      LAYER M1 ;
        RECT 105.100 41.000 107.700 57.600 ;
      LAYER M1 ;
        RECT 107.700 55.000 113.100 57.600 ;
      LAYER M1 ;
        RECT 113.100 41.000 115.700 57.600 ;
      LAYER M1 ;
        RECT 115.700 55.000 121.100 57.600 ;
      LAYER M1 ;
        RECT 121.100 41.000 123.700 57.600 ;
      LAYER M1 ;
        RECT 123.700 55.000 129.100 57.600 ;
      LAYER M1 ;
        RECT 129.100 41.000 131.700 57.600 ;
      LAYER M1 ;
        RECT 131.700 55.000 137.100 57.600 ;
      LAYER M1 ;
        RECT 137.100 41.000 139.700 57.600 ;
      LAYER M1 ;
        RECT 139.700 55.000 145.100 57.600 ;
      LAYER M1 ;
        RECT 145.100 41.000 147.700 57.600 ;
      LAYER M1 ;
        RECT 147.700 55.000 153.100 57.600 ;
      LAYER M1 ;
        RECT 153.100 41.000 155.700 57.600 ;
      LAYER M1 ;
        RECT 155.700 55.000 161.100 57.600 ;
      LAYER M1 ;
        RECT 161.100 41.000 163.700 57.600 ;
      LAYER M1 ;
        RECT 163.700 55.000 169.100 57.600 ;
      LAYER M1 ;
        RECT 169.100 41.000 171.700 57.600 ;
      LAYER M1 ;
        RECT 171.700 55.000 177.100 57.600 ;
      LAYER M1 ;
        RECT 177.100 41.000 179.700 57.600 ;
      LAYER M1 ;
        RECT 179.700 55.000 185.100 57.600 ;
      LAYER M1 ;
        RECT 185.100 41.000 187.700 57.600 ;
      LAYER M1 ;
        RECT 187.700 55.000 193.100 57.600 ;
      LAYER M1 ;
        RECT 193.100 41.000 195.700 57.600 ;
      LAYER M1 ;
        RECT 195.700 55.000 201.100 57.600 ;
      LAYER M1 ;
        RECT 201.100 41.000 203.700 57.600 ;
      LAYER M1 ;
        RECT 203.700 55.000 209.100 57.600 ;
      LAYER M1 ;
        RECT 209.100 41.000 211.700 57.600 ;
      LAYER M1 ;
        RECT 211.700 55.000 217.100 57.600 ;
      LAYER M1 ;
        RECT 217.100 41.000 219.700 57.600 ;
      LAYER M1 ;
        RECT 219.700 55.000 225.100 57.600 ;
      LAYER M1 ;
        RECT 225.100 41.000 227.700 57.600 ;
      LAYER M1 ;
        RECT 227.700 55.000 233.100 57.600 ;
      LAYER M1 ;
        RECT 233.100 41.000 235.700 57.600 ;
      LAYER M1 ;
        RECT 235.700 55.000 241.100 57.600 ;
      LAYER M1 ;
        RECT 241.100 41.000 243.700 57.600 ;
      LAYER M1 ;
        RECT 243.700 55.000 249.100 57.600 ;
      LAYER M1 ;
        RECT 249.100 41.000 251.700 57.600 ;
      LAYER M1 ;
        RECT 251.700 55.000 257.100 57.600 ;
      LAYER M1 ;
        RECT 257.100 41.000 259.700 57.600 ;
      LAYER M1 ;
        RECT 259.700 55.000 265.100 57.600 ;
      LAYER M1 ;
        RECT 265.100 41.000 267.700 57.600 ;
      LAYER M1 ;
        RECT 267.700 55.000 273.100 57.600 ;
      LAYER M1 ;
        RECT 273.100 41.000 275.700 57.600 ;
      LAYER M1 ;
        RECT 275.700 55.000 281.100 57.600 ;
      LAYER M1 ;
        RECT 281.100 41.000 283.700 57.600 ;
      LAYER M1 ;
        RECT 283.700 55.000 289.100 57.600 ;
      LAYER M1 ;
        RECT 289.100 41.000 291.700 57.600 ;
      LAYER M1 ;
        RECT 291.700 55.000 299.100 57.600 ;
    END
  END VDD
  PIN GND
    DIRECTION INOUT ;
    USE GROUND ;
    PORT
      LAYER M1 ;
        RECT 5.000 0.000 9.100 2.600 ;
      LAYER M1 ;
        RECT 9.100 0.000 11.700 9.800 ;
      LAYER M1 ;
        RECT 11.700 0.000 17.100 2.600 ;
      LAYER M1 ;
        RECT 17.100 0.000 19.700 9.800 ;
      LAYER M1 ;
        RECT 19.700 0.000 25.100 2.600 ;
      LAYER M1 ;
        RECT 25.100 0.000 27.700 9.800 ;
      LAYER M1 ;
        RECT 27.700 0.000 33.100 2.600 ;
      LAYER M1 ;
        RECT 33.100 0.000 35.700 9.800 ;
      LAYER M1 ;
        RECT 35.700 0.000 41.100 2.600 ;
      LAYER M1 ;
        RECT 41.100 0.000 43.700 9.800 ;
      LAYER M1 ;
        RECT 43.700 0.000 49.100 2.600 ;
      LAYER M1 ;
        RECT 49.100 0.000 51.700 9.800 ;
      LAYER M1 ;
        RECT 51.700 0.000 57.100 2.600 ;
      LAYER M1 ;
        RECT 57.100 0.000 59.700 9.800 ;
      LAYER M1 ;
        RECT 59.700 0.000 65.100 2.600 ;
      LAYER M1 ;
        RECT 65.100 0.000 67.700 9.800 ;
      LAYER M1 ;
        RECT 67.700 0.000 73.100 2.600 ;
      LAYER M1 ;
        RECT 73.100 0.000 75.700 9.800 ;
      LAYER M1 ;
        RECT 75.700 0.000 81.100 2.600 ;
      LAYER M1 ;
        RECT 81.100 0.000 83.700 9.800 ;
      LAYER M1 ;
        RECT 83.700 0.000 89.100 2.600 ;
      LAYER M1 ;
        RECT 89.100 0.000 91.700 9.800 ;
      LAYER M1 ;
        RECT 91.700 0.000 97.100 2.600 ;
      LAYER M1 ;
        RECT 97.100 0.000 99.700 9.800 ;
      LAYER M1 ;
        RECT 99.700 0.000 105.100 2.600 ;
      LAYER M1 ;
        RECT 105.100 0.000 107.700 9.800 ;
      LAYER M1 ;
        RECT 107.700 0.000 113.100 2.600 ;
      LAYER M1 ;
        RECT 113.100 0.000 115.700 9.800 ;
      LAYER M1 ;
        RECT 115.700 0.000 121.100 2.600 ;
      LAYER M1 ;
        RECT 121.100 0.000 123.700 9.800 ;
      LAYER M1 ;
        RECT 123.700 0.000 129.100 2.600 ;
      LAYER M1 ;
        RECT 129.100 0.000 131.700 9.800 ;
      LAYER M1 ;
        RECT 131.700 0.000 137.100 2.600 ;
      LAYER M1 ;
        RECT 137.100 0.000 139.700 9.800 ;
      LAYER M1 ;
        RECT 139.700 0.000 145.100 2.600 ;
      LAYER M1 ;
        RECT 145.100 0.000 147.700 9.800 ;
      LAYER M1 ;
        RECT 147.700 0.000 153.100 2.600 ;
      LAYER M1 ;
        RECT 153.100 0.000 155.700 9.800 ;
      LAYER M1 ;
        RECT 155.700 0.000 161.100 2.600 ;
      LAYER M1 ;
        RECT 161.100 0.000 163.700 9.800 ;
      LAYER M1 ;
        RECT 163.700 0.000 169.100 2.600 ;
      LAYER M1 ;
        RECT 169.100 0.000 171.700 9.800 ;
      LAYER M1 ;
        RECT 171.700 0.000 177.100 2.600 ;
      LAYER M1 ;
        RECT 177.100 0.000 179.700 9.800 ;
      LAYER M1 ;
        RECT 179.700 0.000 185.100 2.600 ;
      LAYER M1 ;
        RECT 185.100 0.000 187.700 9.800 ;
      LAYER M1 ;
        RECT 187.700 0.000 193.100 2.600 ;
      LAYER M1 ;
        RECT 193.100 0.000 195.700 9.800 ;
      LAYER M1 ;
        RECT 195.700 0.000 201.100 2.600 ;
      LAYER M1 ;
        RECT 201.100 0.000 203.700 9.800 ;
      LAYER M1 ;
        RECT 203.700 0.000 209.100 2.600 ;
      LAYER M1 ;
        RECT 209.100 0.000 211.700 9.800 ;
      LAYER M1 ;
        RECT 211.700 0.000 217.100 2.600 ;
      LAYER M1 ;
        RECT 217.100 0.000 219.700 9.800 ;
      LAYER M1 ;
        RECT 219.700 0.000 225.100 2.600 ;
      LAYER M1 ;
        RECT 225.100 0.000 227.700 9.800 ;
      LAYER M1 ;
        RECT 227.700 0.000 233.100 2.600 ;
      LAYER M1 ;
        RECT 233.100 0.000 235.700 9.800 ;
      LAYER M1 ;
        RECT 235.700 0.000 241.100 2.600 ;
      LAYER M1 ;
        RECT 241.100 0.000 243.700 9.800 ;
      LAYER M1 ;
        RECT 243.700 0.000 249.100 2.600 ;
      LAYER M1 ;
        RECT 249.100 0.000 251.700 9.800 ;
      LAYER M1 ;
        RECT 251.700 0.000 257.100 2.600 ;
      LAYER M1 ;
        RECT 257.100 0.000 259.700 9.800 ;
      LAYER M1 ;
        RECT 259.700 0.000 265.100 2.600 ;
      LAYER M1 ;
        RECT 265.100 0.000 267.700 9.800 ;
      LAYER M1 ;
        RECT 267.700 0.000 273.100 2.600 ;
      LAYER M1 ;
        RECT 273.100 0.000 275.700 9.800 ;
      LAYER M1 ;
        RECT 275.700 0.000 281.100 2.600 ;
      LAYER M1 ;
        RECT 281.100 0.000 283.700 9.800 ;
      LAYER M1 ;
        RECT 283.700 0.000 289.100 2.600 ;
      LAYER M1 ;
        RECT 289.100 0.000 291.700 9.800 ;
      LAYER M1 ;
        RECT 291.700 0.000 299.100 2.600 ;
    END
  END GND
  PIN A
    DIRECTION INPUT ;
    USE SIGNAL ;
    PORT
      LAYER M1 ;
        RECT 19.100 16.400 21.700 19.000 ;
      LAYER M1 ;
        RECT 19.100 31.800 21.700 34.400 ;
      LAYER M1 ;
        RECT 21.700 16.700 26.600 18.700 ;
      LAYER M1 ;
        RECT 21.700 32.100 26.600 34.100 ;
      LAYER M1 ;
        RECT 26.600 16.700 28.700 18.700 ;
      LAYER M1 ;
        RECT 26.600 21.600 28.700 25.000 ;
      LAYER M1 ;
        RECT 26.600 32.100 28.700 34.100 ;
      LAYER M1 ;
        RECT 28.700 16.700 32.100 34.100 ;
      LAYER M1 ;
        RECT 32.100 16.700 39.100 18.700 ;
      LAYER M1 ;
        RECT 32.100 32.100 39.100 34.100 ;
      LAYER M1 ;
        RECT 39.100 16.400 41.700 19.000 ;
      LAYER M1 ;
        RECT 39.100 31.800 41.700 34.400 ;
    END
  END A
END CLKBUF_X12
MACRO CLKBUF_X16
  CLASS CORE ;
  ORIGIN 0 0 ;
  SIZE 392.100 BY 62.600 ;
  SYMMETRY X Y ;
  SITE TR1um_site ;
  PIN A
    DIRECTION INPUT ;
    USE SIGNAL ;
    PORT
      LAYER M1 ;
        RECT 17.100 16.400 19.700 19.000 ;
      LAYER M1 ;
        RECT 17.100 31.800 19.700 34.400 ;
      LAYER M1 ;
        RECT 19.700 16.700 32.100 18.700 ;
      LAYER M1 ;
        RECT 19.700 32.100 32.100 34.100 ;
      LAYER M1 ;
        RECT 32.100 16.700 32.700 18.700 ;
      LAYER M1 ;
        RECT 32.100 21.600 32.700 25.000 ;
      LAYER M1 ;
        RECT 32.100 32.100 32.700 34.100 ;
      LAYER M1 ;
        RECT 32.700 16.700 33.100 34.100 ;
      LAYER M1 ;
        RECT 33.100 16.400 35.700 34.400 ;
      LAYER M1 ;
        RECT 35.700 16.700 36.100 34.100 ;
      LAYER M1 ;
        RECT 36.100 16.700 49.100 18.700 ;
      LAYER M1 ;
        RECT 36.100 32.100 49.100 34.100 ;
      LAYER M1 ;
        RECT 49.100 16.400 51.700 19.000 ;
      LAYER M1 ;
        RECT 49.100 31.800 51.700 34.400 ;
    END
  END A
  PIN Y
    DIRECTION OUTPUT ;
    USE SIGNAL ;
    PORT
      LAYER M1 ;
        RECT 61.100 6.400 63.700 14.400 ;
      LAYER M1 ;
        RECT 61.100 36.400 63.700 51.200 ;
      LAYER M1 ;
        RECT 63.700 11.800 69.100 14.400 ;
      LAYER M1 ;
        RECT 63.700 36.400 69.100 39.000 ;
      LAYER M1 ;
        RECT 69.100 6.400 71.700 14.400 ;
      LAYER M1 ;
        RECT 69.100 36.400 71.700 51.200 ;
      LAYER M1 ;
        RECT 71.700 11.800 77.100 14.400 ;
      LAYER M1 ;
        RECT 71.700 36.400 77.100 39.000 ;
      LAYER M1 ;
        RECT 77.100 6.400 79.700 14.400 ;
      LAYER M1 ;
        RECT 77.100 36.400 79.700 51.200 ;
      LAYER M1 ;
        RECT 79.700 11.800 85.100 14.400 ;
      LAYER M1 ;
        RECT 79.700 36.400 85.100 39.000 ;
      LAYER M1 ;
        RECT 85.100 6.400 87.700 14.400 ;
      LAYER M1 ;
        RECT 85.100 36.400 87.700 51.200 ;
      LAYER M1 ;
        RECT 87.700 11.800 93.100 14.400 ;
      LAYER M1 ;
        RECT 87.700 36.400 93.100 39.000 ;
      LAYER M1 ;
        RECT 93.100 6.400 95.700 14.400 ;
      LAYER M1 ;
        RECT 93.100 36.400 95.700 51.200 ;
      LAYER M1 ;
        RECT 95.700 11.800 101.100 14.400 ;
      LAYER M1 ;
        RECT 95.700 36.400 101.100 39.000 ;
      LAYER M1 ;
        RECT 101.100 6.400 103.700 14.400 ;
      LAYER M1 ;
        RECT 101.100 36.400 103.700 51.200 ;
      LAYER M1 ;
        RECT 103.700 11.800 109.100 14.400 ;
      LAYER M1 ;
        RECT 103.700 36.400 109.100 39.000 ;
      LAYER M1 ;
        RECT 109.100 6.400 111.700 14.400 ;
      LAYER M1 ;
        RECT 109.100 36.400 111.700 51.200 ;
      LAYER M1 ;
        RECT 111.700 11.800 117.100 14.400 ;
      LAYER M1 ;
        RECT 111.700 36.400 117.100 39.000 ;
      LAYER M1 ;
        RECT 117.100 6.400 119.700 14.400 ;
      LAYER M1 ;
        RECT 117.100 36.400 119.700 51.200 ;
      LAYER M1 ;
        RECT 119.700 11.800 125.100 14.400 ;
      LAYER M1 ;
        RECT 119.700 36.400 125.100 39.000 ;
      LAYER M1 ;
        RECT 125.100 6.400 127.700 14.400 ;
      LAYER M1 ;
        RECT 125.100 36.400 127.700 51.200 ;
      LAYER M1 ;
        RECT 127.700 11.800 133.100 14.400 ;
      LAYER M1 ;
        RECT 127.700 36.400 133.100 39.000 ;
      LAYER M1 ;
        RECT 133.100 6.400 135.700 14.400 ;
      LAYER M1 ;
        RECT 133.100 36.400 135.700 51.200 ;
      LAYER M1 ;
        RECT 135.700 11.800 141.100 14.400 ;
      LAYER M1 ;
        RECT 135.700 36.400 141.100 39.000 ;
      LAYER M1 ;
        RECT 141.100 6.400 143.700 14.400 ;
      LAYER M1 ;
        RECT 141.100 36.400 143.700 51.200 ;
      LAYER M1 ;
        RECT 143.700 11.800 149.100 14.400 ;
      LAYER M1 ;
        RECT 143.700 36.400 149.100 39.000 ;
      LAYER M1 ;
        RECT 149.100 6.400 151.700 14.400 ;
      LAYER M1 ;
        RECT 149.100 36.400 151.700 51.200 ;
      LAYER M1 ;
        RECT 151.700 11.800 157.100 14.400 ;
      LAYER M1 ;
        RECT 151.700 36.400 157.100 39.000 ;
      LAYER M1 ;
        RECT 157.100 6.400 159.700 14.400 ;
      LAYER M1 ;
        RECT 157.100 36.400 159.700 51.200 ;
      LAYER M1 ;
        RECT 159.700 11.800 165.100 14.400 ;
      LAYER M1 ;
        RECT 159.700 36.400 165.100 39.000 ;
      LAYER M1 ;
        RECT 165.100 6.400 167.700 14.400 ;
      LAYER M1 ;
        RECT 165.100 36.400 167.700 51.200 ;
      LAYER M1 ;
        RECT 167.700 11.800 173.100 14.400 ;
      LAYER M1 ;
        RECT 167.700 36.400 173.100 39.000 ;
      LAYER M1 ;
        RECT 173.100 6.400 175.700 14.400 ;
      LAYER M1 ;
        RECT 173.100 36.400 175.700 51.200 ;
      LAYER M1 ;
        RECT 175.700 11.800 181.100 14.400 ;
      LAYER M1 ;
        RECT 175.700 36.400 181.100 39.000 ;
      LAYER M1 ;
        RECT 181.100 6.400 183.700 14.400 ;
      LAYER M1 ;
        RECT 181.100 36.400 183.700 51.200 ;
      LAYER M1 ;
        RECT 183.700 11.800 189.100 14.400 ;
      LAYER M1 ;
        RECT 183.700 36.400 189.100 39.000 ;
      LAYER M1 ;
        RECT 189.100 6.400 191.700 14.400 ;
      LAYER M1 ;
        RECT 189.100 36.400 191.700 51.200 ;
      LAYER M1 ;
        RECT 191.700 11.800 197.100 14.400 ;
      LAYER M1 ;
        RECT 191.700 36.400 197.100 39.000 ;
      LAYER M1 ;
        RECT 197.100 6.400 199.700 14.400 ;
      LAYER M1 ;
        RECT 197.100 36.400 199.700 51.200 ;
      LAYER M1 ;
        RECT 199.700 11.800 205.100 14.400 ;
      LAYER M1 ;
        RECT 199.700 36.400 205.100 39.000 ;
      LAYER M1 ;
        RECT 205.100 6.400 207.700 14.400 ;
      LAYER M1 ;
        RECT 205.100 36.400 207.700 51.200 ;
      LAYER M1 ;
        RECT 207.700 11.800 213.100 14.400 ;
      LAYER M1 ;
        RECT 207.700 36.400 213.100 39.000 ;
      LAYER M1 ;
        RECT 213.100 6.400 215.700 14.400 ;
      LAYER M1 ;
        RECT 213.100 36.400 215.700 51.200 ;
      LAYER M1 ;
        RECT 215.700 11.800 221.100 14.400 ;
      LAYER M1 ;
        RECT 215.700 36.400 221.100 39.000 ;
      LAYER M1 ;
        RECT 221.100 6.400 223.700 14.400 ;
      LAYER M1 ;
        RECT 221.100 36.400 223.700 51.200 ;
      LAYER M1 ;
        RECT 223.700 11.800 229.100 14.400 ;
      LAYER M1 ;
        RECT 223.700 36.400 229.100 39.000 ;
      LAYER M1 ;
        RECT 229.100 6.400 231.700 14.400 ;
      LAYER M1 ;
        RECT 229.100 36.400 231.700 51.200 ;
      LAYER M1 ;
        RECT 231.700 11.800 237.100 14.400 ;
      LAYER M1 ;
        RECT 231.700 36.400 237.100 39.000 ;
      LAYER M1 ;
        RECT 237.100 6.400 239.700 14.400 ;
      LAYER M1 ;
        RECT 237.100 36.400 239.700 51.200 ;
      LAYER M1 ;
        RECT 239.700 11.800 245.100 14.400 ;
      LAYER M1 ;
        RECT 239.700 36.400 245.100 39.000 ;
      LAYER M1 ;
        RECT 245.100 6.400 247.700 14.400 ;
      LAYER M1 ;
        RECT 245.100 36.400 247.700 51.200 ;
      LAYER M1 ;
        RECT 247.700 11.800 253.100 14.400 ;
      LAYER M1 ;
        RECT 247.700 36.400 253.100 39.000 ;
      LAYER M1 ;
        RECT 253.100 6.400 255.700 14.400 ;
      LAYER M1 ;
        RECT 253.100 36.400 255.700 51.200 ;
      LAYER M1 ;
        RECT 255.700 11.800 261.100 14.400 ;
      LAYER M1 ;
        RECT 255.700 36.400 261.100 39.000 ;
      LAYER M1 ;
        RECT 261.100 6.400 263.700 14.400 ;
      LAYER M1 ;
        RECT 261.100 36.400 263.700 51.200 ;
      LAYER M1 ;
        RECT 263.700 11.800 269.100 14.400 ;
      LAYER M1 ;
        RECT 263.700 36.400 269.100 39.000 ;
      LAYER M1 ;
        RECT 269.100 6.400 271.700 14.400 ;
      LAYER M1 ;
        RECT 269.100 36.400 271.700 51.200 ;
      LAYER M1 ;
        RECT 271.700 11.800 277.100 14.400 ;
      LAYER M1 ;
        RECT 271.700 36.400 277.100 39.000 ;
      LAYER M1 ;
        RECT 277.100 6.400 279.700 14.400 ;
      LAYER M1 ;
        RECT 277.100 36.400 279.700 51.200 ;
      LAYER M1 ;
        RECT 279.700 11.800 285.100 14.400 ;
      LAYER M1 ;
        RECT 279.700 36.400 285.100 39.000 ;
      LAYER M1 ;
        RECT 285.100 6.400 287.700 14.400 ;
      LAYER M1 ;
        RECT 285.100 36.400 287.700 51.200 ;
      LAYER M1 ;
        RECT 287.700 11.800 293.100 14.400 ;
      LAYER M1 ;
        RECT 287.700 36.400 293.100 39.000 ;
      LAYER M1 ;
        RECT 293.100 6.400 295.700 14.400 ;
      LAYER M1 ;
        RECT 293.100 36.400 295.700 51.200 ;
      LAYER M1 ;
        RECT 295.700 11.800 301.100 14.400 ;
      LAYER M1 ;
        RECT 295.700 36.400 301.100 39.000 ;
      LAYER M1 ;
        RECT 301.100 6.400 303.700 14.400 ;
      LAYER M1 ;
        RECT 301.100 36.400 303.700 51.200 ;
      LAYER M1 ;
        RECT 303.700 11.800 309.100 14.400 ;
      LAYER M1 ;
        RECT 303.700 36.400 309.100 39.000 ;
      LAYER M1 ;
        RECT 309.100 6.400 311.700 14.400 ;
      LAYER M1 ;
        RECT 309.100 36.400 311.700 51.200 ;
      LAYER M1 ;
        RECT 311.700 11.800 317.100 14.400 ;
      LAYER M1 ;
        RECT 311.700 36.400 317.100 39.000 ;
      LAYER M1 ;
        RECT 317.100 6.400 319.700 14.400 ;
      LAYER M1 ;
        RECT 317.100 36.400 319.700 51.200 ;
      LAYER M1 ;
        RECT 319.700 11.800 325.100 14.400 ;
      LAYER M1 ;
        RECT 319.700 36.400 325.100 39.000 ;
      LAYER M1 ;
        RECT 325.100 6.400 327.700 14.400 ;
      LAYER M1 ;
        RECT 325.100 36.400 327.700 51.200 ;
      LAYER M1 ;
        RECT 327.700 11.800 333.100 14.400 ;
      LAYER M1 ;
        RECT 327.700 36.400 333.100 39.000 ;
      LAYER M1 ;
        RECT 333.100 6.400 335.700 14.400 ;
      LAYER M1 ;
        RECT 333.100 36.400 335.700 51.200 ;
      LAYER M1 ;
        RECT 335.700 11.800 341.100 14.400 ;
      LAYER M1 ;
        RECT 335.700 36.400 341.100 39.000 ;
      LAYER M1 ;
        RECT 341.100 6.400 343.700 14.400 ;
      LAYER M1 ;
        RECT 341.100 36.400 343.700 51.200 ;
      LAYER M1 ;
        RECT 343.700 11.800 349.100 14.400 ;
      LAYER M1 ;
        RECT 343.700 36.400 349.100 39.000 ;
      LAYER M1 ;
        RECT 349.100 6.400 351.700 14.400 ;
      LAYER M1 ;
        RECT 349.100 36.400 351.700 51.200 ;
      LAYER M1 ;
        RECT 351.700 11.800 357.100 14.400 ;
      LAYER M1 ;
        RECT 351.700 36.400 357.100 39.000 ;
      LAYER M1 ;
        RECT 357.100 6.400 359.700 14.400 ;
      LAYER M1 ;
        RECT 357.100 36.400 359.700 51.200 ;
      LAYER M1 ;
        RECT 359.700 11.800 365.100 14.400 ;
      LAYER M1 ;
        RECT 359.700 36.400 365.100 39.000 ;
      LAYER M1 ;
        RECT 365.100 6.400 367.700 14.400 ;
      LAYER M1 ;
        RECT 365.100 36.400 367.700 51.200 ;
      LAYER M1 ;
        RECT 367.700 11.800 373.100 14.400 ;
      LAYER M1 ;
        RECT 367.700 36.400 373.100 39.000 ;
      LAYER M1 ;
        RECT 373.100 6.400 375.700 51.200 ;
      LAYER M1 ;
        RECT 375.700 21.600 376.500 25.000 ;
    END
  END Y
  PIN VDD
    DIRECTION INOUT ;
    USE POWER ;
    PORT
      LAYER M1 ;
        RECT 5.000 55.000 9.100 57.600 ;
      LAYER M1 ;
        RECT 9.100 41.000 11.700 57.600 ;
      LAYER M1 ;
        RECT 11.700 55.000 17.100 57.600 ;
      LAYER M1 ;
        RECT 17.100 41.000 19.700 57.600 ;
      LAYER M1 ;
        RECT 19.700 55.000 25.100 57.600 ;
      LAYER M1 ;
        RECT 25.100 41.000 27.700 57.600 ;
      LAYER M1 ;
        RECT 27.700 55.000 33.100 57.600 ;
      LAYER M1 ;
        RECT 33.100 41.000 35.700 57.600 ;
      LAYER M1 ;
        RECT 35.700 55.000 41.100 57.600 ;
      LAYER M1 ;
        RECT 41.100 41.000 43.700 57.600 ;
      LAYER M1 ;
        RECT 43.700 55.000 49.100 57.600 ;
      LAYER M1 ;
        RECT 49.100 41.000 51.700 57.600 ;
      LAYER M1 ;
        RECT 51.700 55.000 57.100 57.600 ;
      LAYER M1 ;
        RECT 57.100 41.000 59.700 57.600 ;
      LAYER M1 ;
        RECT 59.700 55.000 65.100 57.600 ;
      LAYER M1 ;
        RECT 65.100 41.000 67.700 57.600 ;
      LAYER M1 ;
        RECT 67.700 55.000 73.100 57.600 ;
      LAYER M1 ;
        RECT 73.100 41.000 75.700 57.600 ;
      LAYER M1 ;
        RECT 75.700 55.000 81.100 57.600 ;
      LAYER M1 ;
        RECT 81.100 41.000 83.700 57.600 ;
      LAYER M1 ;
        RECT 83.700 55.000 89.100 57.600 ;
      LAYER M1 ;
        RECT 89.100 41.000 91.700 57.600 ;
      LAYER M1 ;
        RECT 91.700 55.000 97.100 57.600 ;
      LAYER M1 ;
        RECT 97.100 41.000 99.700 57.600 ;
      LAYER M1 ;
        RECT 99.700 55.000 105.100 57.600 ;
      LAYER M1 ;
        RECT 105.100 41.000 107.700 57.600 ;
      LAYER M1 ;
        RECT 107.700 55.000 113.100 57.600 ;
      LAYER M1 ;
        RECT 113.100 41.000 115.700 57.600 ;
      LAYER M1 ;
        RECT 115.700 55.000 121.100 57.600 ;
      LAYER M1 ;
        RECT 121.100 41.000 123.700 57.600 ;
      LAYER M1 ;
        RECT 123.700 55.000 129.100 57.600 ;
      LAYER M1 ;
        RECT 129.100 41.000 131.700 57.600 ;
      LAYER M1 ;
        RECT 131.700 55.000 137.100 57.600 ;
      LAYER M1 ;
        RECT 137.100 41.000 139.700 57.600 ;
      LAYER M1 ;
        RECT 139.700 55.000 145.100 57.600 ;
      LAYER M1 ;
        RECT 145.100 41.000 147.700 57.600 ;
      LAYER M1 ;
        RECT 147.700 55.000 153.100 57.600 ;
      LAYER M1 ;
        RECT 153.100 41.000 155.700 57.600 ;
      LAYER M1 ;
        RECT 155.700 55.000 161.100 57.600 ;
      LAYER M1 ;
        RECT 161.100 41.000 163.700 57.600 ;
      LAYER M1 ;
        RECT 163.700 55.000 169.100 57.600 ;
      LAYER M1 ;
        RECT 169.100 41.000 171.700 57.600 ;
      LAYER M1 ;
        RECT 171.700 55.000 177.100 57.600 ;
      LAYER M1 ;
        RECT 177.100 41.000 179.700 57.600 ;
      LAYER M1 ;
        RECT 179.700 55.000 185.100 57.600 ;
      LAYER M1 ;
        RECT 185.100 41.000 187.700 57.600 ;
      LAYER M1 ;
        RECT 187.700 55.000 193.100 57.600 ;
      LAYER M1 ;
        RECT 193.100 41.000 195.700 57.600 ;
      LAYER M1 ;
        RECT 195.700 55.000 201.100 57.600 ;
      LAYER M1 ;
        RECT 201.100 41.000 203.700 57.600 ;
      LAYER M1 ;
        RECT 203.700 55.000 209.100 57.600 ;
      LAYER M1 ;
        RECT 209.100 41.000 211.700 57.600 ;
      LAYER M1 ;
        RECT 211.700 55.000 217.100 57.600 ;
      LAYER M1 ;
        RECT 217.100 41.000 219.700 57.600 ;
      LAYER M1 ;
        RECT 219.700 55.000 225.100 57.600 ;
      LAYER M1 ;
        RECT 225.100 41.000 227.700 57.600 ;
      LAYER M1 ;
        RECT 227.700 55.000 233.100 57.600 ;
      LAYER M1 ;
        RECT 233.100 41.000 235.700 57.600 ;
      LAYER M1 ;
        RECT 235.700 55.000 241.100 57.600 ;
      LAYER M1 ;
        RECT 241.100 41.000 243.700 57.600 ;
      LAYER M1 ;
        RECT 243.700 55.000 249.100 57.600 ;
      LAYER M1 ;
        RECT 249.100 41.000 251.700 57.600 ;
      LAYER M1 ;
        RECT 251.700 55.000 257.100 57.600 ;
      LAYER M1 ;
        RECT 257.100 41.000 259.700 57.600 ;
      LAYER M1 ;
        RECT 259.700 55.000 265.100 57.600 ;
      LAYER M1 ;
        RECT 265.100 41.000 267.700 57.600 ;
      LAYER M1 ;
        RECT 267.700 55.000 273.100 57.600 ;
      LAYER M1 ;
        RECT 273.100 41.000 275.700 57.600 ;
      LAYER M1 ;
        RECT 275.700 55.000 281.100 57.600 ;
      LAYER M1 ;
        RECT 281.100 41.000 283.700 57.600 ;
      LAYER M1 ;
        RECT 283.700 55.000 289.100 57.600 ;
      LAYER M1 ;
        RECT 289.100 41.000 291.700 57.600 ;
      LAYER M1 ;
        RECT 291.700 55.000 297.100 57.600 ;
      LAYER M1 ;
        RECT 297.100 41.000 299.700 57.600 ;
      LAYER M1 ;
        RECT 299.700 55.000 305.100 57.600 ;
      LAYER M1 ;
        RECT 305.100 41.000 307.700 57.600 ;
      LAYER M1 ;
        RECT 307.700 55.000 313.100 57.600 ;
      LAYER M1 ;
        RECT 313.100 41.000 315.700 57.600 ;
      LAYER M1 ;
        RECT 315.700 55.000 321.100 57.600 ;
      LAYER M1 ;
        RECT 321.100 41.000 323.700 57.600 ;
      LAYER M1 ;
        RECT 323.700 55.000 329.100 57.600 ;
      LAYER M1 ;
        RECT 329.100 41.000 331.700 57.600 ;
      LAYER M1 ;
        RECT 331.700 55.000 337.100 57.600 ;
      LAYER M1 ;
        RECT 337.100 41.000 339.700 57.600 ;
      LAYER M1 ;
        RECT 339.700 55.000 345.100 57.600 ;
      LAYER M1 ;
        RECT 345.100 41.000 347.700 57.600 ;
      LAYER M1 ;
        RECT 347.700 55.000 353.100 57.600 ;
      LAYER M1 ;
        RECT 353.100 41.000 355.700 57.600 ;
      LAYER M1 ;
        RECT 355.700 55.000 361.100 57.600 ;
      LAYER M1 ;
        RECT 361.100 41.000 363.700 57.600 ;
      LAYER M1 ;
        RECT 363.700 55.000 369.100 57.600 ;
      LAYER M1 ;
        RECT 369.100 41.000 371.700 57.600 ;
      LAYER M1 ;
        RECT 371.700 55.000 377.100 57.600 ;
      LAYER M1 ;
        RECT 377.100 41.000 379.700 57.600 ;
      LAYER M1 ;
        RECT 379.700 55.000 387.100 57.600 ;
    END
  END VDD
  PIN GND
    DIRECTION INOUT ;
    USE GROUND ;
    PORT
      LAYER M1 ;
        RECT 5.000 0.000 9.100 2.600 ;
      LAYER M1 ;
        RECT 9.100 0.000 11.700 9.800 ;
      LAYER M1 ;
        RECT 11.700 0.000 17.100 2.600 ;
      LAYER M1 ;
        RECT 17.100 0.000 19.700 9.800 ;
      LAYER M1 ;
        RECT 19.700 0.000 25.100 2.600 ;
      LAYER M1 ;
        RECT 25.100 0.000 27.700 9.800 ;
      LAYER M1 ;
        RECT 27.700 0.000 33.100 2.600 ;
      LAYER M1 ;
        RECT 33.100 0.000 35.700 9.800 ;
      LAYER M1 ;
        RECT 35.700 0.000 41.100 2.600 ;
      LAYER M1 ;
        RECT 41.100 0.000 43.700 9.800 ;
      LAYER M1 ;
        RECT 43.700 0.000 49.100 2.600 ;
      LAYER M1 ;
        RECT 49.100 0.000 51.700 9.800 ;
      LAYER M1 ;
        RECT 51.700 0.000 57.100 2.600 ;
      LAYER M1 ;
        RECT 57.100 0.000 59.700 9.800 ;
      LAYER M1 ;
        RECT 59.700 0.000 65.100 2.600 ;
      LAYER M1 ;
        RECT 65.100 0.000 67.700 9.800 ;
      LAYER M1 ;
        RECT 67.700 0.000 73.100 2.600 ;
      LAYER M1 ;
        RECT 73.100 0.000 75.700 9.800 ;
      LAYER M1 ;
        RECT 75.700 0.000 81.100 2.600 ;
      LAYER M1 ;
        RECT 81.100 0.000 83.700 9.800 ;
      LAYER M1 ;
        RECT 83.700 0.000 89.100 2.600 ;
      LAYER M1 ;
        RECT 89.100 0.000 91.700 9.800 ;
      LAYER M1 ;
        RECT 91.700 0.000 97.100 2.600 ;
      LAYER M1 ;
        RECT 97.100 0.000 99.700 9.800 ;
      LAYER M1 ;
        RECT 99.700 0.000 105.100 2.600 ;
      LAYER M1 ;
        RECT 105.100 0.000 107.700 9.800 ;
      LAYER M1 ;
        RECT 107.700 0.000 113.100 2.600 ;
      LAYER M1 ;
        RECT 113.100 0.000 115.700 9.800 ;
      LAYER M1 ;
        RECT 115.700 0.000 121.100 2.600 ;
      LAYER M1 ;
        RECT 121.100 0.000 123.700 9.800 ;
      LAYER M1 ;
        RECT 123.700 0.000 129.100 2.600 ;
      LAYER M1 ;
        RECT 129.100 0.000 131.700 9.800 ;
      LAYER M1 ;
        RECT 131.700 0.000 137.100 2.600 ;
      LAYER M1 ;
        RECT 137.100 0.000 139.700 9.800 ;
      LAYER M1 ;
        RECT 139.700 0.000 145.100 2.600 ;
      LAYER M1 ;
        RECT 145.100 0.000 147.700 9.800 ;
      LAYER M1 ;
        RECT 147.700 0.000 153.100 2.600 ;
      LAYER M1 ;
        RECT 153.100 0.000 155.700 9.800 ;
      LAYER M1 ;
        RECT 155.700 0.000 161.100 2.600 ;
      LAYER M1 ;
        RECT 161.100 0.000 163.700 9.800 ;
      LAYER M1 ;
        RECT 163.700 0.000 169.100 2.600 ;
      LAYER M1 ;
        RECT 169.100 0.000 171.700 9.800 ;
      LAYER M1 ;
        RECT 171.700 0.000 177.100 2.600 ;
      LAYER M1 ;
        RECT 177.100 0.000 179.700 9.800 ;
      LAYER M1 ;
        RECT 179.700 0.000 185.100 2.600 ;
      LAYER M1 ;
        RECT 185.100 0.000 187.700 9.800 ;
      LAYER M1 ;
        RECT 187.700 0.000 193.100 2.600 ;
      LAYER M1 ;
        RECT 193.100 0.000 195.700 9.800 ;
      LAYER M1 ;
        RECT 195.700 0.000 201.100 2.600 ;
      LAYER M1 ;
        RECT 201.100 0.000 203.700 9.800 ;
      LAYER M1 ;
        RECT 203.700 0.000 209.100 2.600 ;
      LAYER M1 ;
        RECT 209.100 0.000 211.700 9.800 ;
      LAYER M1 ;
        RECT 211.700 0.000 217.100 2.600 ;
      LAYER M1 ;
        RECT 217.100 0.000 219.700 9.800 ;
      LAYER M1 ;
        RECT 219.700 0.000 225.100 2.600 ;
      LAYER M1 ;
        RECT 225.100 0.000 227.700 9.800 ;
      LAYER M1 ;
        RECT 227.700 0.000 233.100 2.600 ;
      LAYER M1 ;
        RECT 233.100 0.000 235.700 9.800 ;
      LAYER M1 ;
        RECT 235.700 0.000 241.100 2.600 ;
      LAYER M1 ;
        RECT 241.100 0.000 243.700 9.800 ;
      LAYER M1 ;
        RECT 243.700 0.000 249.100 2.600 ;
      LAYER M1 ;
        RECT 249.100 0.000 251.700 9.800 ;
      LAYER M1 ;
        RECT 251.700 0.000 257.100 2.600 ;
      LAYER M1 ;
        RECT 257.100 0.000 259.700 9.800 ;
      LAYER M1 ;
        RECT 259.700 0.000 265.100 2.600 ;
      LAYER M1 ;
        RECT 265.100 0.000 267.700 9.800 ;
      LAYER M1 ;
        RECT 267.700 0.000 273.100 2.600 ;
      LAYER M1 ;
        RECT 273.100 0.000 275.700 9.800 ;
      LAYER M1 ;
        RECT 275.700 0.000 281.100 2.600 ;
      LAYER M1 ;
        RECT 281.100 0.000 283.700 9.800 ;
      LAYER M1 ;
        RECT 283.700 0.000 289.100 2.600 ;
      LAYER M1 ;
        RECT 289.100 0.000 291.700 9.800 ;
      LAYER M1 ;
        RECT 291.700 0.000 297.100 2.600 ;
      LAYER M1 ;
        RECT 297.100 0.000 299.700 9.800 ;
      LAYER M1 ;
        RECT 299.700 0.000 305.100 2.600 ;
      LAYER M1 ;
        RECT 305.100 0.000 307.700 9.800 ;
      LAYER M1 ;
        RECT 307.700 0.000 313.100 2.600 ;
      LAYER M1 ;
        RECT 313.100 0.000 315.700 9.800 ;
      LAYER M1 ;
        RECT 315.700 0.000 321.100 2.600 ;
      LAYER M1 ;
        RECT 321.100 0.000 323.700 9.800 ;
      LAYER M1 ;
        RECT 323.700 0.000 329.100 2.600 ;
      LAYER M1 ;
        RECT 329.100 0.000 331.700 9.800 ;
      LAYER M1 ;
        RECT 331.700 0.000 337.100 2.600 ;
      LAYER M1 ;
        RECT 337.100 0.000 339.700 9.800 ;
      LAYER M1 ;
        RECT 339.700 0.000 345.100 2.600 ;
      LAYER M1 ;
        RECT 345.100 0.000 347.700 9.800 ;
      LAYER M1 ;
        RECT 347.700 0.000 353.100 2.600 ;
      LAYER M1 ;
        RECT 353.100 0.000 355.700 9.800 ;
      LAYER M1 ;
        RECT 355.700 0.000 361.100 2.600 ;
      LAYER M1 ;
        RECT 361.100 0.000 363.700 9.800 ;
      LAYER M1 ;
        RECT 363.700 0.000 369.100 2.600 ;
      LAYER M1 ;
        RECT 369.100 0.000 371.700 9.800 ;
      LAYER M1 ;
        RECT 371.700 0.000 377.100 2.600 ;
      LAYER M1 ;
        RECT 377.100 0.000 379.700 9.800 ;
      LAYER M1 ;
        RECT 379.700 0.000 387.100 2.600 ;
    END
  END GND
END CLKBUF_X16
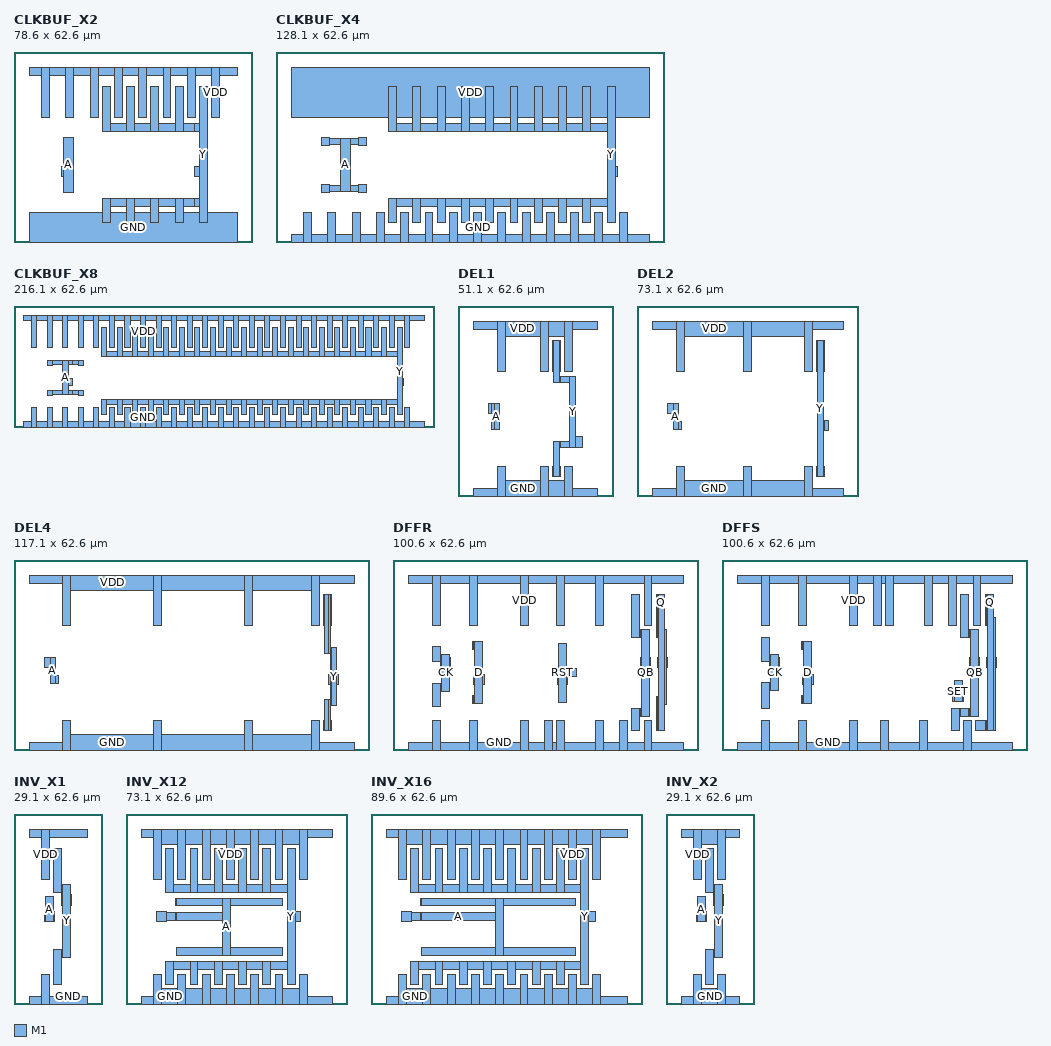
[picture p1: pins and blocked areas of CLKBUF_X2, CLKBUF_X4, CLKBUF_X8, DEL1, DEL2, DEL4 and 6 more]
MACRO CLKBUF_X2
  CLASS CORE ;
  ORIGIN 0 0 ;
  SIZE 78.600 BY 62.600 ;
  SYMMETRY X Y ;
  SITE TR1um_site ;
  PIN A
    DIRECTION INPUT ;
    USE SIGNAL ;
    PORT
      LAYER M1 ;
        RECT 15.600 21.600 16.300 25.000 ;
      LAYER M1 ;
        RECT 16.300 16.400 19.700 34.400 ;
    END
  END A
  PIN Y
    DIRECTION OUTPUT ;
    USE SIGNAL ;
    PORT
      LAYER M1 ;
        RECT 29.100 6.400 31.700 14.400 ;
      LAYER M1 ;
        RECT 29.100 36.400 31.700 51.200 ;
      LAYER M1 ;
        RECT 31.700 11.800 37.100 14.400 ;
      LAYER M1 ;
        RECT 31.700 36.400 37.100 39.000 ;
      LAYER M1 ;
        RECT 37.100 6.400 39.700 14.400 ;
      LAYER M1 ;
        RECT 37.100 36.400 39.700 51.200 ;
      LAYER M1 ;
        RECT 39.700 11.800 45.100 14.400 ;
      LAYER M1 ;
        RECT 39.700 36.400 45.100 39.000 ;
      LAYER M1 ;
        RECT 45.100 6.400 47.700 14.400 ;
      LAYER M1 ;
        RECT 45.100 36.400 47.700 51.200 ;
      LAYER M1 ;
        RECT 47.700 11.800 53.100 14.400 ;
      LAYER M1 ;
        RECT 47.700 36.400 53.100 39.000 ;
      LAYER M1 ;
        RECT 53.100 6.400 55.700 14.400 ;
      LAYER M1 ;
        RECT 53.100 36.400 55.700 51.200 ;
      LAYER M1 ;
        RECT 55.700 11.800 59.600 14.400 ;
      LAYER M1 ;
        RECT 55.700 36.400 59.600 39.000 ;
      LAYER M1 ;
        RECT 59.600 11.800 61.100 14.400 ;
      LAYER M1 ;
        RECT 59.600 21.600 61.100 25.000 ;
      LAYER M1 ;
        RECT 59.600 36.400 61.100 39.000 ;
      LAYER M1 ;
        RECT 61.100 6.400 63.700 51.200 ;
    END
  END Y
  PIN VDD
    DIRECTION INOUT ;
    USE POWER ;
    PORT
      LAYER M1 ;
        RECT 5.000 55.000 9.100 57.600 ;
      LAYER M1 ;
        RECT 9.100 41.000 11.700 57.600 ;
      LAYER M1 ;
        RECT 11.700 55.000 17.100 57.600 ;
      LAYER M1 ;
        RECT 17.100 41.000 19.700 57.600 ;
      LAYER M1 ;
        RECT 19.700 55.000 25.100 57.600 ;
      LAYER M1 ;
        RECT 25.100 41.000 27.700 57.600 ;
      LAYER M1 ;
        RECT 27.700 55.000 33.100 57.600 ;
      LAYER M1 ;
        RECT 33.100 41.000 35.700 57.600 ;
      LAYER M1 ;
        RECT 35.700 55.000 41.100 57.600 ;
      LAYER M1 ;
        RECT 41.100 41.000 43.700 57.600 ;
      LAYER M1 ;
        RECT 43.700 55.000 49.100 57.600 ;
      LAYER M1 ;
        RECT 49.100 41.000 51.700 57.600 ;
      LAYER M1 ;
        RECT 51.700 55.000 57.100 57.600 ;
      LAYER M1 ;
        RECT 57.100 41.000 59.700 57.600 ;
      LAYER M1 ;
        RECT 59.700 55.000 65.100 57.600 ;
      LAYER M1 ;
        RECT 65.100 41.000 67.700 57.600 ;
      LAYER M1 ;
        RECT 67.700 55.000 73.600 57.600 ;
    END
  END VDD
  PIN GND
    DIRECTION INOUT ;
    USE GROUND ;
    PORT
      LAYER M1 ;
        RECT 5.000 0.000 73.600 9.800 ;
    END
  END GND
END CLKBUF_X2
MACRO CLKBUF_X4
  CLASS CORE ;
  ORIGIN 0 0 ;
  SIZE 128.100 BY 62.600 ;
  SYMMETRY X Y ;
  SITE TR1um_site ;
  PIN Y
    DIRECTION OUTPUT ;
    USE SIGNAL ;
    PORT
      LAYER M1 ;
        RECT 37.100 6.400 39.700 14.400 ;
      LAYER M1 ;
        RECT 37.100 36.400 39.700 51.200 ;
      LAYER M1 ;
        RECT 39.700 11.800 45.100 14.400 ;
      LAYER M1 ;
        RECT 39.700 36.400 45.100 39.000 ;
      LAYER M1 ;
        RECT 45.100 6.400 47.700 14.400 ;
      LAYER M1 ;
        RECT 45.100 36.400 47.700 51.200 ;
      LAYER M1 ;
        RECT 47.700 11.800 53.100 14.400 ;
      LAYER M1 ;
        RECT 47.700 36.400 53.100 39.000 ;
      LAYER M1 ;
        RECT 53.100 6.400 55.700 14.400 ;
      LAYER M1 ;
        RECT 53.100 36.400 55.700 51.200 ;
      LAYER M1 ;
        RECT 55.700 11.800 61.100 14.400 ;
      LAYER M1 ;
        RECT 55.700 36.400 61.100 39.000 ;
      LAYER M1 ;
        RECT 61.100 6.400 63.700 14.400 ;
      LAYER M1 ;
        RECT 61.100 36.400 63.700 51.200 ;
      LAYER M1 ;
        RECT 63.700 11.800 69.100 14.400 ;
      LAYER M1 ;
        RECT 63.700 36.400 69.100 39.000 ;
      LAYER M1 ;
        RECT 69.100 6.400 71.700 14.400 ;
      LAYER M1 ;
        RECT 69.100 36.400 71.700 51.200 ;
      LAYER M1 ;
        RECT 71.700 11.800 77.100 14.400 ;
      LAYER M1 ;
        RECT 71.700 36.400 77.100 39.000 ;
      LAYER M1 ;
        RECT 77.100 6.400 79.700 14.400 ;
      LAYER M1 ;
        RECT 77.100 36.400 79.700 51.200 ;
      LAYER M1 ;
        RECT 79.700 11.800 85.100 14.400 ;
      LAYER M1 ;
        RECT 79.700 36.400 85.100 39.000 ;
      LAYER M1 ;
        RECT 85.100 6.400 87.700 14.400 ;
      LAYER M1 ;
        RECT 85.100 36.400 87.700 51.200 ;
      LAYER M1 ;
        RECT 87.700 11.800 93.100 14.400 ;
      LAYER M1 ;
        RECT 87.700 36.400 93.100 39.000 ;
      LAYER M1 ;
        RECT 93.100 6.400 95.700 14.400 ;
      LAYER M1 ;
        RECT 93.100 36.400 95.700 51.200 ;
      LAYER M1 ;
        RECT 95.700 11.800 101.100 14.400 ;
      LAYER M1 ;
        RECT 95.700 36.400 101.100 39.000 ;
      LAYER M1 ;
        RECT 101.100 6.400 103.700 14.400 ;
      LAYER M1 ;
        RECT 101.100 36.400 103.700 51.200 ;
      LAYER M1 ;
        RECT 103.700 11.800 109.100 14.400 ;
      LAYER M1 ;
        RECT 103.700 36.400 109.100 39.000 ;
      LAYER M1 ;
        RECT 109.100 6.400 111.700 51.200 ;
      LAYER M1 ;
        RECT 111.700 21.600 112.500 25.000 ;
    END
  END Y
  PIN A
    DIRECTION INPUT ;
    USE SIGNAL ;
    PORT
      LAYER M1 ;
        RECT 15.100 16.400 17.700 19.000 ;
      LAYER M1 ;
        RECT 15.100 31.800 17.700 34.400 ;
      LAYER M1 ;
        RECT 17.700 16.700 21.100 18.700 ;
      LAYER M1 ;
        RECT 17.700 32.100 21.100 34.100 ;
      LAYER M1 ;
        RECT 21.100 16.700 24.500 34.100 ;
      LAYER M1 ;
        RECT 24.500 16.700 27.100 18.700 ;
      LAYER M1 ;
        RECT 24.500 32.100 27.100 34.100 ;
      LAYER M1 ;
        RECT 27.100 16.400 29.700 19.000 ;
      LAYER M1 ;
        RECT 27.100 31.800 29.700 34.400 ;
    END
  END A
  PIN GND
    DIRECTION INOUT ;
    USE GROUND ;
    PORT
      LAYER M1 ;
        RECT 5.000 0.000 9.100 2.600 ;
      LAYER M1 ;
        RECT 9.100 0.000 11.700 9.800 ;
      LAYER M1 ;
        RECT 11.700 0.000 17.100 2.600 ;
      LAYER M1 ;
        RECT 17.100 0.000 19.700 9.800 ;
      LAYER M1 ;
        RECT 19.700 0.000 25.100 2.600 ;
      LAYER M1 ;
        RECT 25.100 0.000 27.700 9.800 ;
      LAYER M1 ;
        RECT 27.700 0.000 33.100 2.600 ;
      LAYER M1 ;
        RECT 33.100 0.000 35.700 9.800 ;
      LAYER M1 ;
        RECT 35.700 0.000 41.100 2.600 ;
      LAYER M1 ;
        RECT 41.100 0.000 43.700 9.800 ;
      LAYER M1 ;
        RECT 43.700 0.000 49.100 2.600 ;
      LAYER M1 ;
        RECT 49.100 0.000 51.700 9.800 ;
      LAYER M1 ;
        RECT 51.700 0.000 57.100 2.600 ;
      LAYER M1 ;
        RECT 57.100 0.000 59.700 9.800 ;
      LAYER M1 ;
        RECT 59.700 0.000 65.100 2.600 ;
      LAYER M1 ;
        RECT 65.100 0.000 67.700 9.800 ;
      LAYER M1 ;
        RECT 67.700 0.000 73.100 2.600 ;
      LAYER M1 ;
        RECT 73.100 0.000 75.700 9.800 ;
      LAYER M1 ;
        RECT 75.700 0.000 81.100 2.600 ;
      LAYER M1 ;
        RECT 81.100 0.000 83.700 9.800 ;
      LAYER M1 ;
        RECT 83.700 0.000 89.100 2.600 ;
      LAYER M1 ;
        RECT 89.100 0.000 91.700 9.800 ;
      LAYER M1 ;
        RECT 91.700 0.000 97.100 2.600 ;
      LAYER M1 ;
        RECT 97.100 0.000 99.700 9.800 ;
      LAYER M1 ;
        RECT 99.700 0.000 105.100 2.600 ;
      LAYER M1 ;
        RECT 105.100 0.000 107.700 9.800 ;
      LAYER M1 ;
        RECT 107.700 0.000 113.100 2.600 ;
      LAYER M1 ;
        RECT 113.100 0.000 115.700 9.800 ;
      LAYER M1 ;
        RECT 115.700 0.000 123.100 2.600 ;
    END
  END GND
  PIN VDD
    DIRECTION INOUT ;
    USE POWER ;
    PORT
      LAYER M1 ;
        RECT 5.000 41.000 123.100 57.600 ;
    END
  END VDD
END CLKBUF_X4
MACRO CLKBUF_X8
  CLASS CORE ;
  ORIGIN 0 0 ;
  SIZE 216.100 BY 62.600 ;
  SYMMETRY X Y ;
  SITE TR1um_site ;
  PIN A
    DIRECTION INPUT ;
    USE SIGNAL ;
    PORT
      LAYER M1 ;
        RECT 17.100 16.400 19.700 19.000 ;
      LAYER M1 ;
        RECT 17.100 31.800 19.700 34.400 ;
      LAYER M1 ;
        RECT 19.700 16.700 24.700 18.700 ;
      LAYER M1 ;
        RECT 19.700 32.100 24.700 34.100 ;
      LAYER M1 ;
        RECT 24.700 16.700 28.100 34.100 ;
      LAYER M1 ;
        RECT 28.100 16.700 30.000 18.700 ;
      LAYER M1 ;
        RECT 28.100 21.600 30.000 25.000 ;
      LAYER M1 ;
        RECT 28.100 32.100 30.000 34.100 ;
      LAYER M1 ;
        RECT 30.000 16.700 33.100 18.700 ;
      LAYER M1 ;
        RECT 30.000 32.100 33.100 34.100 ;
      LAYER M1 ;
        RECT 33.100 16.400 35.700 19.000 ;
      LAYER M1 ;
        RECT 33.100 31.800 35.700 34.400 ;
    END
  END A
  PIN Y
    DIRECTION OUTPUT ;
    USE SIGNAL ;
    PORT
      LAYER M1 ;
        RECT 45.100 6.400 47.700 14.400 ;
      LAYER M1 ;
        RECT 45.100 36.400 47.700 51.200 ;
      LAYER M1 ;
        RECT 47.700 11.800 53.100 14.400 ;
      LAYER M1 ;
        RECT 47.700 36.400 53.100 39.000 ;
      LAYER M1 ;
        RECT 53.100 6.400 55.700 14.400 ;
      LAYER M1 ;
        RECT 53.100 36.400 55.700 51.200 ;
      LAYER M1 ;
        RECT 55.700 11.800 61.100 14.400 ;
      LAYER M1 ;
        RECT 55.700 36.400 61.100 39.000 ;
      LAYER M1 ;
        RECT 61.100 6.400 63.700 14.400 ;
      LAYER M1 ;
        RECT 61.100 36.400 63.700 51.200 ;
      LAYER M1 ;
        RECT 63.700 11.800 69.100 14.400 ;
      LAYER M1 ;
        RECT 63.700 36.400 69.100 39.000 ;
      LAYER M1 ;
        RECT 69.100 6.400 71.700 14.400 ;
      LAYER M1 ;
        RECT 69.100 36.400 71.700 51.200 ;
      LAYER M1 ;
        RECT 71.700 11.800 77.100 14.400 ;
      LAYER M1 ;
        RECT 71.700 36.400 77.100 39.000 ;
      LAYER M1 ;
        RECT 77.100 6.400 79.700 14.400 ;
      LAYER M1 ;
        RECT 77.100 36.400 79.700 51.200 ;
      LAYER M1 ;
        RECT 79.700 11.800 85.100 14.400 ;
      LAYER M1 ;
        RECT 79.700 36.400 85.100 39.000 ;
      LAYER M1 ;
        RECT 85.100 6.400 87.700 14.400 ;
      LAYER M1 ;
        RECT 85.100 36.400 87.700 51.200 ;
      LAYER M1 ;
        RECT 87.700 11.800 93.100 14.400 ;
      LAYER M1 ;
        RECT 87.700 36.400 93.100 39.000 ;
      LAYER M1 ;
        RECT 93.100 6.400 95.700 14.400 ;
      LAYER M1 ;
        RECT 93.100 36.400 95.700 51.200 ;
      LAYER M1 ;
        RECT 95.700 11.800 101.100 14.400 ;
      LAYER M1 ;
        RECT 95.700 36.400 101.100 39.000 ;
      LAYER M1 ;
        RECT 101.100 6.400 103.700 14.400 ;
      LAYER M1 ;
        RECT 101.100 36.400 103.700 51.200 ;
      LAYER M1 ;
        RECT 103.700 11.800 109.100 14.400 ;
      LAYER M1 ;
        RECT 103.700 36.400 109.100 39.000 ;
      LAYER M1 ;
        RECT 109.100 6.400 111.700 14.400 ;
      LAYER M1 ;
        RECT 109.100 36.400 111.700 51.200 ;
      LAYER M1 ;
        RECT 111.700 11.800 117.100 14.400 ;
      LAYER M1 ;
        RECT 111.700 36.400 117.100 39.000 ;
      LAYER M1 ;
        RECT 117.100 6.400 119.700 14.400 ;
      LAYER M1 ;
        RECT 117.100 36.400 119.700 51.200 ;
      LAYER M1 ;
        RECT 119.700 11.800 125.100 14.400 ;
      LAYER M1 ;
        RECT 119.700 36.400 125.100 39.000 ;
      LAYER M1 ;
        RECT 125.100 6.400 127.700 14.400 ;
      LAYER M1 ;
        RECT 125.100 36.400 127.700 51.200 ;
      LAYER M1 ;
        RECT 127.700 11.800 133.100 14.400 ;
      LAYER M1 ;
        RECT 127.700 36.400 133.100 39.000 ;
      LAYER M1 ;
        RECT 133.100 6.400 135.700 14.400 ;
      LAYER M1 ;
        RECT 133.100 36.400 135.700 51.200 ;
      LAYER M1 ;
        RECT 135.700 11.800 141.100 14.400 ;
      LAYER M1 ;
        RECT 135.700 36.400 141.100 39.000 ;
      LAYER M1 ;
        RECT 141.100 6.400 143.700 14.400 ;
      LAYER M1 ;
        RECT 141.100 36.400 143.700 51.200 ;
      LAYER M1 ;
        RECT 143.700 11.800 149.100 14.400 ;
      LAYER M1 ;
        RECT 143.700 36.400 149.100 39.000 ;
      LAYER M1 ;
        RECT 149.100 6.400 151.700 14.400 ;
      LAYER M1 ;
        RECT 149.100 36.400 151.700 51.200 ;
      LAYER M1 ;
        RECT 151.700 11.800 157.100 14.400 ;
      LAYER M1 ;
        RECT 151.700 36.400 157.100 39.000 ;
      LAYER M1 ;
        RECT 157.100 6.400 159.700 14.400 ;
      LAYER M1 ;
        RECT 157.100 36.400 159.700 51.200 ;
      LAYER M1 ;
        RECT 159.700 11.800 165.100 14.400 ;
      LAYER M1 ;
        RECT 159.700 36.400 165.100 39.000 ;
      LAYER M1 ;
        RECT 165.100 6.400 167.700 14.400 ;
      LAYER M1 ;
        RECT 165.100 36.400 167.700 51.200 ;
      LAYER M1 ;
        RECT 167.700 11.800 173.100 14.400 ;
      LAYER M1 ;
        RECT 167.700 36.400 173.100 39.000 ;
      LAYER M1 ;
        RECT 173.100 6.400 175.700 14.400 ;
      LAYER M1 ;
        RECT 173.100 36.400 175.700 51.200 ;
      LAYER M1 ;
        RECT 175.700 11.800 181.100 14.400 ;
      LAYER M1 ;
        RECT 175.700 36.400 181.100 39.000 ;
      LAYER M1 ;
        RECT 181.100 6.400 183.700 14.400 ;
      LAYER M1 ;
        RECT 181.100 36.400 183.700 51.200 ;
      LAYER M1 ;
        RECT 183.700 11.800 189.100 14.400 ;
      LAYER M1 ;
        RECT 183.700 36.400 189.100 39.000 ;
      LAYER M1 ;
        RECT 189.100 6.400 191.700 14.400 ;
      LAYER M1 ;
        RECT 189.100 36.400 191.700 51.200 ;
      LAYER M1 ;
        RECT 191.700 11.800 197.100 14.400 ;
      LAYER M1 ;
        RECT 191.700 36.400 197.100 39.000 ;
      LAYER M1 ;
        RECT 197.100 6.400 199.700 51.200 ;
      LAYER M1 ;
        RECT 199.700 21.600 200.500 25.000 ;
    END
  END Y
  PIN VDD
    DIRECTION INOUT ;
    USE POWER ;
    PORT
      LAYER M1 ;
        RECT 5.000 55.000 9.100 57.600 ;
      LAYER M1 ;
        RECT 9.100 41.000 11.700 57.600 ;
      LAYER M1 ;
        RECT 11.700 55.000 17.100 57.600 ;
      LAYER M1 ;
        RECT 17.100 41.000 19.700 57.600 ;
      LAYER M1 ;
        RECT 19.700 55.000 25.100 57.600 ;
      LAYER M1 ;
        RECT 25.100 41.000 27.700 57.600 ;
      LAYER M1 ;
        RECT 27.700 55.000 33.100 57.600 ;
      LAYER M1 ;
        RECT 33.100 41.000 35.700 57.600 ;
      LAYER M1 ;
        RECT 35.700 55.000 41.100 57.600 ;
      LAYER M1 ;
        RECT 41.100 41.000 43.700 57.600 ;
      LAYER M1 ;
        RECT 43.700 55.000 49.100 57.600 ;
      LAYER M1 ;
        RECT 49.100 41.000 51.700 57.600 ;
      LAYER M1 ;
        RECT 51.700 55.000 57.100 57.600 ;
      LAYER M1 ;
        RECT 57.100 41.000 59.700 57.600 ;
      LAYER M1 ;
        RECT 59.700 55.000 65.100 57.600 ;
      LAYER M1 ;
        RECT 65.100 41.000 67.700 57.600 ;
      LAYER M1 ;
        RECT 67.700 55.000 73.100 57.600 ;
      LAYER M1 ;
        RECT 73.100 41.000 75.700 57.600 ;
      LAYER M1 ;
        RECT 75.700 55.000 81.100 57.600 ;
      LAYER M1 ;
        RECT 81.100 41.000 83.700 57.600 ;
      LAYER M1 ;
        RECT 83.700 55.000 89.100 57.600 ;
      LAYER M1 ;
        RECT 89.100 41.000 91.700 57.600 ;
      LAYER M1 ;
        RECT 91.700 55.000 97.100 57.600 ;
      LAYER M1 ;
        RECT 97.100 41.000 99.700 57.600 ;
      LAYER M1 ;
        RECT 99.700 55.000 105.100 57.600 ;
      LAYER M1 ;
        RECT 105.100 41.000 107.700 57.600 ;
      LAYER M1 ;
        RECT 107.700 55.000 113.100 57.600 ;
      LAYER M1 ;
        RECT 113.100 41.000 115.700 57.600 ;
      LAYER M1 ;
        RECT 115.700 55.000 121.100 57.600 ;
      LAYER M1 ;
        RECT 121.100 41.000 123.700 57.600 ;
      LAYER M1 ;
        RECT 123.700 55.000 129.100 57.600 ;
      LAYER M1 ;
        RECT 129.100 41.000 131.700 57.600 ;
      LAYER M1 ;
        RECT 131.700 55.000 137.100 57.600 ;
      LAYER M1 ;
        RECT 137.100 41.000 139.700 57.600 ;
      LAYER M1 ;
        RECT 139.700 55.000 145.100 57.600 ;
      LAYER M1 ;
        RECT 145.100 41.000 147.700 57.600 ;
      LAYER M1 ;
        RECT 147.700 55.000 153.100 57.600 ;
      LAYER M1 ;
        RECT 153.100 41.000 155.700 57.600 ;
      LAYER M1 ;
        RECT 155.700 55.000 161.100 57.600 ;
      LAYER M1 ;
        RECT 161.100 41.000 163.700 57.600 ;
      LAYER M1 ;
        RECT 163.700 55.000 169.100 57.600 ;
      LAYER M1 ;
        RECT 169.100 41.000 171.700 57.600 ;
      LAYER M1 ;
        RECT 171.700 55.000 177.100 57.600 ;
      LAYER M1 ;
        RECT 177.100 41.000 179.700 57.600 ;
      LAYER M1 ;
        RECT 179.700 55.000 185.100 57.600 ;
      LAYER M1 ;
        RECT 185.100 41.000 187.700 57.600 ;
      LAYER M1 ;
        RECT 187.700 55.000 193.100 57.600 ;
      LAYER M1 ;
        RECT 193.100 41.000 195.700 57.600 ;
      LAYER M1 ;
        RECT 195.700 55.000 201.100 57.600 ;
      LAYER M1 ;
        RECT 201.100 41.000 203.700 57.600 ;
      LAYER M1 ;
        RECT 203.700 55.000 211.100 57.600 ;
    END
  END VDD
  PIN GND
    DIRECTION INOUT ;
    USE GROUND ;
    PORT
      LAYER M1 ;
        RECT 5.000 0.000 9.100 2.600 ;
      LAYER M1 ;
        RECT 9.100 0.000 11.700 9.800 ;
      LAYER M1 ;
        RECT 11.700 0.000 17.100 2.600 ;
      LAYER M1 ;
        RECT 17.100 0.000 19.700 9.800 ;
      LAYER M1 ;
        RECT 19.700 0.000 25.100 2.600 ;
      LAYER M1 ;
        RECT 25.100 0.000 27.700 9.800 ;
      LAYER M1 ;
        RECT 27.700 0.000 33.100 2.600 ;
      LAYER M1 ;
        RECT 33.100 0.000 35.700 9.800 ;
      LAYER M1 ;
        RECT 35.700 0.000 41.100 2.600 ;
      LAYER M1 ;
        RECT 41.100 0.000 43.700 9.800 ;
      LAYER M1 ;
        RECT 43.700 0.000 49.100 2.600 ;
      LAYER M1 ;
        RECT 49.100 0.000 51.700 9.800 ;
      LAYER M1 ;
        RECT 51.700 0.000 57.100 2.600 ;
      LAYER M1 ;
        RECT 57.100 0.000 59.700 9.800 ;
      LAYER M1 ;
        RECT 59.700 0.000 65.100 2.600 ;
      LAYER M1 ;
        RECT 65.100 0.000 67.700 9.800 ;
      LAYER M1 ;
        RECT 67.700 0.000 73.100 2.600 ;
      LAYER M1 ;
        RECT 73.100 0.000 75.700 9.800 ;
      LAYER M1 ;
        RECT 75.700 0.000 81.100 2.600 ;
      LAYER M1 ;
        RECT 81.100 0.000 83.700 9.800 ;
      LAYER M1 ;
        RECT 83.700 0.000 89.100 2.600 ;
      LAYER M1 ;
        RECT 89.100 0.000 91.700 9.800 ;
      LAYER M1 ;
        RECT 91.700 0.000 97.100 2.600 ;
      LAYER M1 ;
        RECT 97.100 0.000 99.700 9.800 ;
      LAYER M1 ;
        RECT 99.700 0.000 105.100 2.600 ;
      LAYER M1 ;
        RECT 105.100 0.000 107.700 9.800 ;
      LAYER M1 ;
        RECT 107.700 0.000 113.100 2.600 ;
      LAYER M1 ;
        RECT 113.100 0.000 115.700 9.800 ;
      LAYER M1 ;
        RECT 115.700 0.000 121.100 2.600 ;
      LAYER M1 ;
        RECT 121.100 0.000 123.700 9.800 ;
      LAYER M1 ;
        RECT 123.700 0.000 129.100 2.600 ;
      LAYER M1 ;
        RECT 129.100 0.000 131.700 9.800 ;
      LAYER M1 ;
        RECT 131.700 0.000 137.100 2.600 ;
      LAYER M1 ;
        RECT 137.100 0.000 139.700 9.800 ;
      LAYER M1 ;
        RECT 139.700 0.000 145.100 2.600 ;
      LAYER M1 ;
        RECT 145.100 0.000 147.700 9.800 ;
      LAYER M1 ;
        RECT 147.700 0.000 153.100 2.600 ;
      LAYER M1 ;
        RECT 153.100 0.000 155.700 9.800 ;
      LAYER M1 ;
        RECT 155.700 0.000 161.100 2.600 ;
      LAYER M1 ;
        RECT 161.100 0.000 163.700 9.800 ;
      LAYER M1 ;
        RECT 163.700 0.000 169.100 2.600 ;
      LAYER M1 ;
        RECT 169.100 0.000 171.700 9.800 ;
      LAYER M1 ;
        RECT 171.700 0.000 177.100 2.600 ;
      LAYER M1 ;
        RECT 177.100 0.000 179.700 9.800 ;
      LAYER M1 ;
        RECT 179.700 0.000 185.100 2.600 ;
      LAYER M1 ;
        RECT 185.100 0.000 187.700 9.800 ;
      LAYER M1 ;
        RECT 187.700 0.000 193.100 2.600 ;
      LAYER M1 ;
        RECT 193.100 0.000 195.700 9.800 ;
      LAYER M1 ;
        RECT 195.700 0.000 201.100 2.600 ;
      LAYER M1 ;
        RECT 201.100 0.000 203.700 9.800 ;
      LAYER M1 ;
        RECT 203.700 0.000 211.100 2.600 ;
    END
  END GND
END CLKBUF_X8
MACRO DEL1
  CLASS CORE ;
  ORIGIN 0 0 ;
  SIZE 51.100 BY 62.600 ;
  SYMMETRY X Y ;
  SITE TR1um_site ;
  PIN Y
    DIRECTION OUTPUT ;
    USE SIGNAL ;
    PORT
      LAYER M1 ;
        RECT 31.100 6.400 31.500 9.800 ;
      LAYER M1 ;
        RECT 31.100 41.000 31.500 51.200 ;
      LAYER M1 ;
        RECT 31.500 6.400 33.300 17.900 ;
      LAYER M1 ;
        RECT 31.500 37.500 33.300 51.200 ;
      LAYER M1 ;
        RECT 33.300 6.400 33.700 9.800 ;
      LAYER M1 ;
        RECT 33.300 16.100 33.700 17.900 ;
      LAYER M1 ;
        RECT 33.300 37.500 33.700 39.300 ;
      LAYER M1 ;
        RECT 33.300 41.000 33.700 51.200 ;
      LAYER M1 ;
        RECT 33.700 16.100 36.900 17.900 ;
      LAYER M1 ;
        RECT 33.700 37.500 36.900 39.300 ;
      LAYER M1 ;
        RECT 36.900 16.100 38.700 39.300 ;
      LAYER M1 ;
        RECT 38.700 16.100 41.000 19.500 ;
    END
  END Y
  PIN A
    DIRECTION INPUT ;
    USE SIGNAL ;
    PORT
      LAYER M1 ;
        RECT 10.100 27.100 11.100 30.500 ;
      LAYER M1 ;
        RECT 11.100 22.000 11.900 24.600 ;
      LAYER M1 ;
        RECT 11.100 27.100 11.900 30.500 ;
      LAYER M1 ;
        RECT 11.900 22.000 13.700 30.500 ;
    END
  END A
  PIN VDD
    DIRECTION INOUT ;
    USE POWER ;
    PORT
      LAYER M1 ;
        RECT 5.000 55.000 13.100 57.600 ;
      LAYER M1 ;
        RECT 13.100 41.000 15.700 57.600 ;
      LAYER M1 ;
        RECT 15.700 52.600 27.100 57.600 ;
      LAYER M1 ;
        RECT 27.100 41.000 29.700 57.600 ;
      LAYER M1 ;
        RECT 29.700 52.600 35.100 57.600 ;
      LAYER M1 ;
        RECT 35.100 41.000 37.700 57.600 ;
      LAYER M1 ;
        RECT 37.700 55.000 46.100 57.600 ;
    END
  END VDD
  PIN GND
    DIRECTION INOUT ;
    USE GROUND ;
    PORT
      LAYER M1 ;
        RECT 5.000 0.000 13.100 2.600 ;
      LAYER M1 ;
        RECT 13.100 0.000 15.700 9.800 ;
      LAYER M1 ;
        RECT 15.700 0.000 27.100 5.000 ;
      LAYER M1 ;
        RECT 27.100 0.000 29.700 9.800 ;
      LAYER M1 ;
        RECT 29.700 0.000 35.100 5.000 ;
      LAYER M1 ;
        RECT 35.100 0.000 37.700 9.800 ;
      LAYER M1 ;
        RECT 37.700 0.000 46.100 2.600 ;
    END
  END GND
END DEL1
MACRO DEL2
  CLASS CORE ;
  ORIGIN 0 0 ;
  SIZE 73.100 BY 62.600 ;
  SYMMETRY X Y ;
  SITE TR1um_site ;
  PIN VDD
    DIRECTION INOUT ;
    USE POWER ;
    PORT
      LAYER M1 ;
        RECT 5.000 55.000 13.100 57.600 ;
      LAYER M1 ;
        RECT 13.100 41.000 15.700 57.600 ;
      LAYER M1 ;
        RECT 15.700 52.600 35.100 57.600 ;
      LAYER M1 ;
        RECT 35.100 41.000 37.700 57.600 ;
      LAYER M1 ;
        RECT 37.700 52.600 55.100 57.600 ;
      LAYER M1 ;
        RECT 55.100 41.000 57.700 57.600 ;
      LAYER M1 ;
        RECT 57.700 55.000 68.100 57.600 ;
    END
  END VDD
  PIN Y
    DIRECTION OUTPUT ;
    USE SIGNAL ;
    PORT
      LAYER M1 ;
        RECT 59.100 6.400 59.500 9.800 ;
      LAYER M1 ;
        RECT 59.100 41.000 59.500 51.200 ;
      LAYER M1 ;
        RECT 59.500 6.400 61.300 51.200 ;
      LAYER M1 ;
        RECT 61.300 6.400 61.700 9.800 ;
      LAYER M1 ;
        RECT 61.300 21.600 61.700 25.000 ;
      LAYER M1 ;
        RECT 61.300 41.000 61.700 51.200 ;
      LAYER M1 ;
        RECT 61.700 21.600 63.000 25.000 ;
    END
  END Y
  PIN A
    DIRECTION INPUT ;
    USE SIGNAL ;
    PORT
      LAYER M1 ;
        RECT 10.100 27.100 11.900 30.500 ;
      LAYER M1 ;
        RECT 11.900 22.000 13.700 30.500 ;
      LAYER M1 ;
        RECT 13.700 22.000 14.500 24.600 ;
    END
  END A
  PIN GND
    DIRECTION INOUT ;
    USE GROUND ;
    PORT
      LAYER M1 ;
        RECT 5.000 0.000 13.100 2.600 ;
      LAYER M1 ;
        RECT 13.100 0.000 15.700 9.800 ;
      LAYER M1 ;
        RECT 15.700 0.000 35.100 5.000 ;
      LAYER M1 ;
        RECT 35.100 0.000 37.700 9.800 ;
      LAYER M1 ;
        RECT 37.700 0.000 55.100 5.000 ;
      LAYER M1 ;
        RECT 55.100 0.000 57.700 9.800 ;
      LAYER M1 ;
        RECT 57.700 0.000 68.100 2.600 ;
    END
  END GND
END DEL2
MACRO DEL4
  CLASS CORE ;
  ORIGIN 0 0 ;
  SIZE 117.100 BY 62.600 ;
  SYMMETRY X Y ;
  SITE TR1um_site ;
  PIN VDD
    DIRECTION INOUT ;
    USE POWER ;
    PORT
      LAYER M1 ;
        RECT 5.000 55.000 16.100 57.600 ;
      LAYER M1 ;
        RECT 16.100 41.000 18.700 57.600 ;
      LAYER M1 ;
        RECT 18.700 52.600 46.100 57.600 ;
      LAYER M1 ;
        RECT 46.100 41.000 48.700 57.600 ;
      LAYER M1 ;
        RECT 48.700 52.600 76.100 57.600 ;
      LAYER M1 ;
        RECT 76.100 41.000 78.700 57.600 ;
      LAYER M1 ;
        RECT 78.700 52.600 98.100 57.600 ;
      LAYER M1 ;
        RECT 98.100 41.000 100.700 57.600 ;
      LAYER M1 ;
        RECT 100.700 55.000 112.100 57.600 ;
    END
  END VDD
  PIN Y
    DIRECTION OUTPUT ;
    USE SIGNAL ;
    PORT
      LAYER M1 ;
        RECT 102.100 6.400 102.400 9.800 ;
      LAYER M1 ;
        RECT 102.100 41.000 102.400 51.200 ;
      LAYER M1 ;
        RECT 102.400 6.400 103.600 16.600 ;
      LAYER M1 ;
        RECT 102.400 31.800 103.600 51.200 ;
      LAYER M1 ;
        RECT 103.600 6.400 104.300 16.600 ;
      LAYER M1 ;
        RECT 103.600 21.600 104.300 25.000 ;
      LAYER M1 ;
        RECT 103.600 31.800 104.300 51.200 ;
      LAYER M1 ;
        RECT 104.300 6.400 104.400 51.200 ;
      LAYER M1 ;
        RECT 104.400 6.400 104.700 9.800 ;
      LAYER M1 ;
        RECT 104.400 14.600 104.700 33.800 ;
      LAYER M1 ;
        RECT 104.400 41.000 104.700 51.200 ;
      LAYER M1 ;
        RECT 104.700 14.600 106.300 33.800 ;
      LAYER M1 ;
        RECT 106.300 21.600 107.000 25.000 ;
    END
  END Y
  PIN A
    DIRECTION INPUT ;
    USE SIGNAL ;
    PORT
      LAYER M1 ;
        RECT 10.100 27.100 11.900 30.500 ;
      LAYER M1 ;
        RECT 11.900 22.000 13.700 30.500 ;
      LAYER M1 ;
        RECT 13.700 22.000 14.500 24.600 ;
    END
  END A
  PIN GND
    DIRECTION INOUT ;
    USE GROUND ;
    PORT
      LAYER M1 ;
        RECT 5.000 0.000 16.100 2.600 ;
      LAYER M1 ;
        RECT 16.100 0.000 18.700 9.800 ;
      LAYER M1 ;
        RECT 18.700 0.000 46.100 5.000 ;
      LAYER M1 ;
        RECT 46.100 0.000 48.700 9.800 ;
      LAYER M1 ;
        RECT 48.700 0.000 76.100 5.000 ;
      LAYER M1 ;
        RECT 76.100 0.000 78.700 9.800 ;
      LAYER M1 ;
        RECT 78.700 0.000 98.100 5.000 ;
      LAYER M1 ;
        RECT 98.100 0.000 100.700 9.800 ;
      LAYER M1 ;
        RECT 100.700 0.000 112.100 2.600 ;
    END
  END GND
END DEL4
MACRO DFFR
  CLASS CORE ;
  ORIGIN 0 0 ;
  SIZE 100.600 BY 62.600 ;
  SYMMETRY X Y ;
  SITE TR1um_site ;
  PIN D
    DIRECTION INPUT ;
    USE SIGNAL ;
    PORT
      LAYER M1 ;
        RECT 26.300 15.200 26.600 17.800 ;
      LAYER M1 ;
        RECT 26.300 33.000 26.600 35.600 ;
      LAYER M1 ;
        RECT 26.600 15.200 27.000 17.800 ;
      LAYER M1 ;
        RECT 26.600 21.600 27.000 25.000 ;
      LAYER M1 ;
        RECT 26.600 33.000 27.000 35.600 ;
      LAYER M1 ;
        RECT 27.000 15.200 29.600 35.600 ;
      LAYER M1 ;
        RECT 29.600 21.600 30.000 25.000 ;
    END
  END D
  PIN RST
    DIRECTION INPUT ;
    USE SIGNAL ;
    PORT
      LAYER M1 ;
        RECT 54.100 21.600 54.500 25.000 ;
      LAYER M1 ;
        RECT 54.500 15.600 57.100 35.200 ;
      LAYER M1 ;
        RECT 57.100 21.600 57.500 26.800 ;
      LAYER M1 ;
        RECT 57.500 24.200 60.300 26.800 ;
    END
  END RST
  PIN QB
    DIRECTION OUTPUT ;
    USE SIGNAL ;
    PORT
      LAYER M1 ;
        RECT 78.700 6.400 81.300 13.800 ;
      LAYER M1 ;
        RECT 78.700 37.000 81.300 51.200 ;
      LAYER M1 ;
        RECT 81.300 11.200 81.600 13.800 ;
      LAYER M1 ;
        RECT 81.300 37.000 81.600 39.600 ;
      LAYER M1 ;
        RECT 81.600 11.200 82.000 13.800 ;
      LAYER M1 ;
        RECT 81.600 27.100 82.000 30.500 ;
      LAYER M1 ;
        RECT 81.600 37.000 82.000 39.600 ;
      LAYER M1 ;
        RECT 82.000 11.200 84.600 39.600 ;
      LAYER M1 ;
        RECT 84.600 27.100 85.000 30.500 ;
    END
  END QB
  PIN Q
    DIRECTION OUTPUT ;
    USE SIGNAL ;
    PORT
      LAYER M1 ;
        RECT 86.700 6.400 87.100 17.700 ;
      LAYER M1 ;
        RECT 86.700 37.000 87.100 51.200 ;
      LAYER M1 ;
        RECT 87.100 6.400 87.500 17.700 ;
      LAYER M1 ;
        RECT 87.100 27.100 87.500 30.500 ;
      LAYER M1 ;
        RECT 87.100 37.000 87.500 51.200 ;
      LAYER M1 ;
        RECT 87.500 6.400 89.300 51.200 ;
      LAYER M1 ;
        RECT 89.300 15.100 90.100 39.600 ;
      LAYER M1 ;
        RECT 90.100 27.100 90.500 30.500 ;
    END
  END Q
  PIN GND
    DIRECTION INOUT ;
    USE GROUND ;
    PORT
      LAYER M1 ;
        RECT 5.000 0.000 13.100 2.600 ;
      LAYER M1 ;
        RECT 13.100 0.000 15.700 9.800 ;
      LAYER M1 ;
        RECT 15.700 0.000 25.100 2.600 ;
      LAYER M1 ;
        RECT 25.100 0.000 27.700 9.800 ;
      LAYER M1 ;
        RECT 27.700 0.000 41.900 2.600 ;
      LAYER M1 ;
        RECT 41.900 0.000 44.500 9.800 ;
      LAYER M1 ;
        RECT 44.500 0.000 49.900 2.600 ;
      LAYER M1 ;
        RECT 49.900 0.000 52.500 9.800 ;
      LAYER M1 ;
        RECT 52.500 0.000 53.900 2.600 ;
      LAYER M1 ;
        RECT 53.900 0.000 56.500 9.800 ;
      LAYER M1 ;
        RECT 56.500 0.000 66.700 2.600 ;
      LAYER M1 ;
        RECT 66.700 0.000 69.300 9.800 ;
      LAYER M1 ;
        RECT 69.300 0.000 74.700 2.600 ;
      LAYER M1 ;
        RECT 74.700 0.000 77.300 9.800 ;
      LAYER M1 ;
        RECT 77.300 0.000 82.700 2.600 ;
      LAYER M1 ;
        RECT 82.700 0.000 85.300 9.800 ;
      LAYER M1 ;
        RECT 85.300 0.000 95.600 2.600 ;
    END
  END GND
  PIN CK
    DIRECTION INPUT ;
    USE SIGNAL ;
    PORT
      LAYER M1 ;
        RECT 13.100 14.350 15.600 21.800 ;
      LAYER M1 ;
        RECT 13.100 29.000 15.600 34.150 ;
      LAYER M1 ;
        RECT 15.600 14.350 15.700 21.800 ;
      LAYER M1 ;
        RECT 15.600 27.100 15.700 34.150 ;
      LAYER M1 ;
        RECT 15.700 19.200 16.000 21.800 ;
      LAYER M1 ;
        RECT 15.700 27.100 16.000 31.600 ;
      LAYER M1 ;
        RECT 16.000 19.200 18.600 31.600 ;
      LAYER M1 ;
        RECT 18.600 27.100 19.000 30.500 ;
    END
  END CK
  PIN VDD
    DIRECTION INOUT ;
    USE POWER ;
    PORT
      LAYER M1 ;
        RECT 5.000 55.000 13.100 57.600 ;
      LAYER M1 ;
        RECT 13.100 41.000 15.700 57.600 ;
      LAYER M1 ;
        RECT 15.700 55.000 25.100 57.600 ;
      LAYER M1 ;
        RECT 25.100 41.000 27.700 57.600 ;
      LAYER M1 ;
        RECT 27.700 55.000 41.900 57.600 ;
      LAYER M1 ;
        RECT 41.900 41.000 44.500 57.600 ;
      LAYER M1 ;
        RECT 44.500 55.000 53.900 57.600 ;
      LAYER M1 ;
        RECT 53.900 41.000 56.500 57.600 ;
      LAYER M1 ;
        RECT 56.500 55.000 66.700 57.600 ;
      LAYER M1 ;
        RECT 66.700 41.000 69.300 57.600 ;
      LAYER M1 ;
        RECT 69.300 55.000 82.700 57.600 ;
      LAYER M1 ;
        RECT 82.700 41.000 85.300 57.600 ;
      LAYER M1 ;
        RECT 85.300 55.000 95.600 57.600 ;
    END
  END VDD
END DFFR
MACRO DFFS
  CLASS CORE ;
  ORIGIN 0 0 ;
  SIZE 100.600 BY 62.600 ;
  SYMMETRY X Y ;
  SITE TR1um_site ;
  PIN SET
    DIRECTION INPUT ;
    USE SIGNAL ;
    PORT
      LAYER M1 ;
        RECT 76.100 16.100 76.500 19.500 ;
      LAYER M1 ;
        RECT 76.500 16.100 79.100 22.750 ;
      LAYER M1 ;
        RECT 79.100 16.100 79.500 19.500 ;
    END
  END SET
  PIN D
    DIRECTION INPUT ;
    USE SIGNAL ;
    PORT
      LAYER M1 ;
        RECT 26.300 15.200 26.600 17.800 ;
      LAYER M1 ;
        RECT 26.300 33.000 26.600 35.600 ;
      LAYER M1 ;
        RECT 26.600 15.200 27.000 17.800 ;
      LAYER M1 ;
        RECT 26.600 21.600 27.000 25.000 ;
      LAYER M1 ;
        RECT 26.600 33.000 27.000 35.600 ;
      LAYER M1 ;
        RECT 27.000 15.200 29.600 35.600 ;
      LAYER M1 ;
        RECT 29.600 21.600 30.000 25.000 ;
    END
  END D
  PIN Q
    DIRECTION OUTPUT ;
    USE SIGNAL ;
    PORT
      LAYER M1 ;
        RECT 83.500 6.400 86.700 9.800 ;
      LAYER M1 ;
        RECT 86.700 6.400 87.100 9.800 ;
      LAYER M1 ;
        RECT 86.700 41.000 87.100 51.200 ;
      LAYER M1 ;
        RECT 87.100 6.400 87.500 9.800 ;
      LAYER M1 ;
        RECT 87.100 27.100 87.500 30.500 ;
      LAYER M1 ;
        RECT 87.100 41.000 87.500 51.200 ;
      LAYER M1 ;
        RECT 87.500 6.400 89.300 51.200 ;
      LAYER M1 ;
        RECT 89.300 6.400 90.100 43.600 ;
      LAYER M1 ;
        RECT 90.100 27.100 90.500 30.500 ;
    END
  END Q
  PIN QB
    DIRECTION OUTPUT ;
    USE SIGNAL ;
    PORT
      LAYER M1 ;
        RECT 75.500 6.400 78.100 13.800 ;
      LAYER M1 ;
        RECT 78.100 11.200 78.700 13.800 ;
      LAYER M1 ;
        RECT 78.700 11.200 81.300 13.800 ;
      LAYER M1 ;
        RECT 78.700 37.000 81.300 51.200 ;
      LAYER M1 ;
        RECT 81.300 11.200 81.600 13.800 ;
      LAYER M1 ;
        RECT 81.300 37.000 81.600 39.600 ;
      LAYER M1 ;
        RECT 81.600 11.200 82.000 13.800 ;
      LAYER M1 ;
        RECT 81.600 27.100 82.000 30.500 ;
      LAYER M1 ;
        RECT 81.600 37.000 82.000 39.600 ;
      LAYER M1 ;
        RECT 82.000 11.200 84.600 39.600 ;
      LAYER M1 ;
        RECT 84.600 27.100 85.000 30.500 ;
    END
  END QB
  PIN CK
    DIRECTION INPUT ;
    USE SIGNAL ;
    PORT
      LAYER M1 ;
        RECT 13.100 13.600 15.600 22.350 ;
      LAYER M1 ;
        RECT 13.100 29.000 15.600 37.200 ;
      LAYER M1 ;
        RECT 15.600 13.600 15.700 22.350 ;
      LAYER M1 ;
        RECT 15.600 27.100 15.700 37.200 ;
      LAYER M1 ;
        RECT 15.700 19.750 16.000 22.350 ;
      LAYER M1 ;
        RECT 15.700 27.100 16.000 31.600 ;
      LAYER M1 ;
        RECT 16.000 19.750 18.600 31.600 ;
      LAYER M1 ;
        RECT 18.600 27.100 19.000 30.500 ;
    END
  END CK
  PIN GND
    DIRECTION INOUT ;
    USE GROUND ;
    PORT
      LAYER M1 ;
        RECT 5.000 0.000 13.100 2.600 ;
      LAYER M1 ;
        RECT 13.100 0.000 15.700 9.800 ;
      LAYER M1 ;
        RECT 15.700 0.000 25.100 2.600 ;
      LAYER M1 ;
        RECT 25.100 0.000 27.700 9.800 ;
      LAYER M1 ;
        RECT 27.700 0.000 41.900 2.600 ;
      LAYER M1 ;
        RECT 41.900 0.000 44.500 9.800 ;
      LAYER M1 ;
        RECT 44.500 0.000 52.300 2.600 ;
      LAYER M1 ;
        RECT 52.300 0.000 54.900 9.800 ;
      LAYER M1 ;
        RECT 54.900 0.000 65.100 2.600 ;
      LAYER M1 ;
        RECT 65.100 0.000 67.700 9.800 ;
      LAYER M1 ;
        RECT 67.700 0.000 79.500 2.600 ;
      LAYER M1 ;
        RECT 79.500 0.000 82.100 9.800 ;
      LAYER M1 ;
        RECT 82.100 0.000 95.600 2.600 ;
    END
  END GND
  PIN VDD
    DIRECTION INOUT ;
    USE POWER ;
    PORT
      LAYER M1 ;
        RECT 5.000 55.000 13.100 57.600 ;
      LAYER M1 ;
        RECT 13.100 41.000 15.700 57.600 ;
      LAYER M1 ;
        RECT 15.700 55.000 25.100 57.600 ;
      LAYER M1 ;
        RECT 25.100 41.000 27.700 57.600 ;
      LAYER M1 ;
        RECT 27.700 55.000 41.900 57.600 ;
      LAYER M1 ;
        RECT 41.900 41.000 44.500 57.600 ;
      LAYER M1 ;
        RECT 44.500 55.000 49.900 57.600 ;
      LAYER M1 ;
        RECT 49.900 41.000 52.500 57.600 ;
      LAYER M1 ;
        RECT 52.500 55.000 53.900 57.600 ;
      LAYER M1 ;
        RECT 53.900 41.000 56.500 57.600 ;
      LAYER M1 ;
        RECT 56.500 55.000 66.700 57.600 ;
      LAYER M1 ;
        RECT 66.700 41.000 69.300 57.600 ;
      LAYER M1 ;
        RECT 69.300 55.000 74.700 57.600 ;
      LAYER M1 ;
        RECT 74.700 41.000 77.300 57.600 ;
      LAYER M1 ;
        RECT 77.300 55.000 82.700 57.600 ;
      LAYER M1 ;
        RECT 82.700 41.000 85.300 57.600 ;
      LAYER M1 ;
        RECT 85.300 55.000 95.600 57.600 ;
    END
  END VDD
END DFFS
MACRO INV_X1
  CLASS CORE ;
  ORIGIN 0 0 ;
  SIZE 29.100 BY 62.600 ;
  SYMMETRY X Y ;
  SITE TR1um_site ;
  PIN A
    DIRECTION INPUT ;
    USE SIGNAL ;
    PORT
      LAYER M1 ;
        RECT 10.100 27.100 10.300 30.500 ;
      LAYER M1 ;
        RECT 10.300 27.100 12.900 35.500 ;
      LAYER M1 ;
        RECT 12.900 27.100 13.500 30.500 ;
    END
  END A
  PIN VDD
    DIRECTION INOUT ;
    USE POWER ;
    PORT
      LAYER M1 ;
        RECT 5.000 55.000 9.100 57.600 ;
      LAYER M1 ;
        RECT 9.100 41.000 11.700 57.600 ;
      LAYER M1 ;
        RECT 11.700 55.000 24.100 57.600 ;
    END
  END VDD
  PIN GND
    DIRECTION INOUT ;
    USE GROUND ;
    PORT
      LAYER M1 ;
        RECT 5.000 0.000 9.100 2.600 ;
      LAYER M1 ;
        RECT 9.100 0.000 11.700 9.800 ;
      LAYER M1 ;
        RECT 11.700 0.000 24.100 2.600 ;
    END
  END GND
  PIN Y
    DIRECTION OUTPUT ;
    USE SIGNAL ;
    PORT
      LAYER M1 ;
        RECT 13.100 6.400 15.600 17.800 ;
      LAYER M1 ;
        RECT 13.100 36.900 15.600 51.200 ;
      LAYER M1 ;
        RECT 15.600 6.400 15.700 17.800 ;
      LAYER M1 ;
        RECT 15.600 32.600 15.700 51.200 ;
      LAYER M1 ;
        RECT 15.700 15.200 16.000 17.800 ;
      LAYER M1 ;
        RECT 15.700 32.600 16.000 39.500 ;
      LAYER M1 ;
        RECT 16.000 15.200 18.600 39.500 ;
      LAYER M1 ;
        RECT 18.600 32.600 19.000 36.000 ;
    END
  END Y
END INV_X1
MACRO INV_X12
  CLASS CORE ;
  ORIGIN 0 0 ;
  SIZE 73.100 BY 62.600 ;
  SYMMETRY X Y ;
  SITE TR1um_site ;
  PIN Y
    DIRECTION OUTPUT ;
    USE SIGNAL ;
    PORT
      LAYER M1 ;
        RECT 13.100 6.400 15.700 14.000 ;
      LAYER M1 ;
        RECT 13.100 36.800 15.700 51.200 ;
      LAYER M1 ;
        RECT 15.700 11.400 21.100 14.000 ;
      LAYER M1 ;
        RECT 15.700 36.800 21.100 39.400 ;
      LAYER M1 ;
        RECT 21.100 6.400 23.700 14.000 ;
      LAYER M1 ;
        RECT 21.100 36.800 23.700 51.200 ;
      LAYER M1 ;
        RECT 23.700 11.400 29.100 14.000 ;
      LAYER M1 ;
        RECT 23.700 36.800 29.100 39.400 ;
      LAYER M1 ;
        RECT 29.100 6.400 31.700 14.000 ;
      LAYER M1 ;
        RECT 29.100 36.800 31.700 51.200 ;
      LAYER M1 ;
        RECT 31.700 11.400 37.100 14.000 ;
      LAYER M1 ;
        RECT 31.700 36.800 37.100 39.400 ;
      LAYER M1 ;
        RECT 37.100 6.400 39.700 14.000 ;
      LAYER M1 ;
        RECT 37.100 36.800 39.700 51.200 ;
      LAYER M1 ;
        RECT 39.700 11.400 45.100 14.000 ;
      LAYER M1 ;
        RECT 39.700 36.800 45.100 39.400 ;
      LAYER M1 ;
        RECT 45.100 6.400 47.700 14.000 ;
      LAYER M1 ;
        RECT 45.100 36.800 47.700 51.200 ;
      LAYER M1 ;
        RECT 47.700 11.400 53.100 14.000 ;
      LAYER M1 ;
        RECT 47.700 36.800 53.100 39.400 ;
      LAYER M1 ;
        RECT 53.100 6.400 55.700 51.200 ;
      LAYER M1 ;
        RECT 55.700 27.100 57.500 30.500 ;
    END
  END Y
  PIN A
    DIRECTION INPUT ;
    USE SIGNAL ;
    PORT
      LAYER M1 ;
        RECT 10.100 27.100 13.500 30.500 ;
      LAYER M1 ;
        RECT 13.500 27.500 16.400 30.100 ;
      LAYER M1 ;
        RECT 16.400 27.500 16.600 30.100 ;
      LAYER M1 ;
        RECT 16.400 32.300 16.600 34.900 ;
      LAYER M1 ;
        RECT 16.600 15.900 31.900 18.500 ;
      LAYER M1 ;
        RECT 16.600 27.500 31.900 30.100 ;
      LAYER M1 ;
        RECT 16.600 32.300 31.900 34.900 ;
      LAYER M1 ;
        RECT 31.900 15.900 34.500 34.900 ;
      LAYER M1 ;
        RECT 34.500 15.900 51.500 18.500 ;
      LAYER M1 ;
        RECT 34.500 32.300 51.500 34.900 ;
    END
  END A
  PIN VDD
    DIRECTION INOUT ;
    USE POWER ;
    PORT
      LAYER M1 ;
        RECT 5.000 55.000 9.100 57.600 ;
      LAYER M1 ;
        RECT 9.100 41.000 11.700 57.600 ;
      LAYER M1 ;
        RECT 11.700 52.600 17.100 57.600 ;
      LAYER M1 ;
        RECT 17.100 41.000 19.700 57.600 ;
      LAYER M1 ;
        RECT 19.700 52.600 25.100 57.600 ;
      LAYER M1 ;
        RECT 25.100 41.000 27.700 57.600 ;
      LAYER M1 ;
        RECT 27.700 52.600 33.100 57.600 ;
      LAYER M1 ;
        RECT 33.100 41.000 35.700 57.600 ;
      LAYER M1 ;
        RECT 35.700 52.600 41.100 57.600 ;
      LAYER M1 ;
        RECT 41.100 41.000 43.700 57.600 ;
      LAYER M1 ;
        RECT 43.700 52.600 49.100 57.600 ;
      LAYER M1 ;
        RECT 49.100 41.000 51.700 57.600 ;
      LAYER M1 ;
        RECT 51.700 52.600 57.100 57.600 ;
      LAYER M1 ;
        RECT 57.100 41.000 59.700 57.600 ;
      LAYER M1 ;
        RECT 59.700 55.000 68.100 57.600 ;
    END
  END VDD
  PIN GND
    DIRECTION INOUT ;
    USE GROUND ;
    PORT
      LAYER M1 ;
        RECT 5.000 0.000 9.100 2.600 ;
      LAYER M1 ;
        RECT 9.100 0.000 11.700 9.800 ;
      LAYER M1 ;
        RECT 11.700 0.000 17.100 5.000 ;
      LAYER M1 ;
        RECT 17.100 0.000 19.700 9.800 ;
      LAYER M1 ;
        RECT 19.700 0.000 25.100 5.000 ;
      LAYER M1 ;
        RECT 25.100 0.000 27.700 9.800 ;
      LAYER M1 ;
        RECT 27.700 0.000 33.100 5.000 ;
      LAYER M1 ;
        RECT 33.100 0.000 35.700 9.800 ;
      LAYER M1 ;
        RECT 35.700 0.000 41.100 5.000 ;
      LAYER M1 ;
        RECT 41.100 0.000 43.700 9.800 ;
      LAYER M1 ;
        RECT 43.700 0.000 49.100 5.000 ;
      LAYER M1 ;
        RECT 49.100 0.000 51.700 9.800 ;
      LAYER M1 ;
        RECT 51.700 0.000 57.100 5.000 ;
      LAYER M1 ;
        RECT 57.100 0.000 59.700 9.800 ;
      LAYER M1 ;
        RECT 59.700 0.000 68.100 2.600 ;
    END
  END GND
END INV_X12
MACRO INV_X16
  CLASS CORE ;
  ORIGIN 0 0 ;
  SIZE 89.600 BY 62.600 ;
  SYMMETRY X Y ;
  SITE TR1um_site ;
  PIN Y
    DIRECTION OUTPUT ;
    USE SIGNAL ;
    PORT
      LAYER M1 ;
        RECT 13.100 6.400 15.700 14.000 ;
      LAYER M1 ;
        RECT 13.100 36.800 15.700 51.200 ;
      LAYER M1 ;
        RECT 15.700 11.400 21.100 14.000 ;
      LAYER M1 ;
        RECT 15.700 36.800 21.100 39.400 ;
      LAYER M1 ;
        RECT 21.100 6.400 23.700 14.000 ;
      LAYER M1 ;
        RECT 21.100 36.800 23.700 51.200 ;
      LAYER M1 ;
        RECT 23.700 11.400 29.100 14.000 ;
      LAYER M1 ;
        RECT 23.700 36.800 29.100 39.400 ;
      LAYER M1 ;
        RECT 29.100 6.400 31.700 14.000 ;
      LAYER M1 ;
        RECT 29.100 36.800 31.700 51.200 ;
      LAYER M1 ;
        RECT 31.700 11.400 37.100 14.000 ;
      LAYER M1 ;
        RECT 31.700 36.800 37.100 39.400 ;
      LAYER M1 ;
        RECT 37.100 6.400 39.700 14.000 ;
      LAYER M1 ;
        RECT 37.100 36.800 39.700 51.200 ;
      LAYER M1 ;
        RECT 39.700 11.400 45.100 14.000 ;
      LAYER M1 ;
        RECT 39.700 36.800 45.100 39.400 ;
      LAYER M1 ;
        RECT 45.100 6.400 47.700 14.000 ;
      LAYER M1 ;
        RECT 45.100 36.800 47.700 51.200 ;
      LAYER M1 ;
        RECT 47.700 11.400 53.100 14.000 ;
      LAYER M1 ;
        RECT 47.700 36.800 53.100 39.400 ;
      LAYER M1 ;
        RECT 53.100 6.400 55.700 14.000 ;
      LAYER M1 ;
        RECT 53.100 36.800 55.700 51.200 ;
      LAYER M1 ;
        RECT 55.700 11.400 61.100 14.000 ;
      LAYER M1 ;
        RECT 55.700 36.800 61.100 39.400 ;
      LAYER M1 ;
        RECT 61.100 6.400 63.700 14.000 ;
      LAYER M1 ;
        RECT 61.100 36.800 63.700 51.200 ;
      LAYER M1 ;
        RECT 63.700 11.400 69.100 14.000 ;
      LAYER M1 ;
        RECT 63.700 36.800 69.100 39.400 ;
      LAYER M1 ;
        RECT 69.100 6.400 71.700 51.200 ;
      LAYER M1 ;
        RECT 71.700 27.100 74.000 30.500 ;
    END
  END Y
  PIN A
    DIRECTION INPUT ;
    USE SIGNAL ;
    PORT
      LAYER M1 ;
        RECT 10.100 27.100 13.500 30.500 ;
      LAYER M1 ;
        RECT 13.500 27.500 16.400 30.100 ;
      LAYER M1 ;
        RECT 16.400 27.500 16.600 30.100 ;
      LAYER M1 ;
        RECT 16.400 32.300 16.600 34.900 ;
      LAYER M1 ;
        RECT 16.600 15.900 41.100 18.500 ;
      LAYER M1 ;
        RECT 16.600 27.500 41.100 30.100 ;
      LAYER M1 ;
        RECT 16.600 32.300 41.100 34.900 ;
      LAYER M1 ;
        RECT 41.100 15.900 43.700 34.900 ;
      LAYER M1 ;
        RECT 43.700 15.900 67.500 18.500 ;
      LAYER M1 ;
        RECT 43.700 32.300 67.500 34.900 ;
    END
  END A
  PIN VDD
    DIRECTION INOUT ;
    USE POWER ;
    PORT
      LAYER M1 ;
        RECT 5.000 55.000 9.100 57.600 ;
      LAYER M1 ;
        RECT 9.100 41.000 11.700 57.600 ;
      LAYER M1 ;
        RECT 11.700 52.600 17.100 57.600 ;
      LAYER M1 ;
        RECT 17.100 41.000 19.700 57.600 ;
      LAYER M1 ;
        RECT 19.700 52.600 25.100 57.600 ;
      LAYER M1 ;
        RECT 25.100 41.000 27.700 57.600 ;
      LAYER M1 ;
        RECT 27.700 52.600 33.100 57.600 ;
      LAYER M1 ;
        RECT 33.100 41.000 35.700 57.600 ;
      LAYER M1 ;
        RECT 35.700 52.600 41.100 57.600 ;
      LAYER M1 ;
        RECT 41.100 41.000 43.700 57.600 ;
      LAYER M1 ;
        RECT 43.700 52.600 49.100 57.600 ;
      LAYER M1 ;
        RECT 49.100 41.000 51.700 57.600 ;
      LAYER M1 ;
        RECT 51.700 52.600 57.100 57.600 ;
      LAYER M1 ;
        RECT 57.100 41.000 59.700 57.600 ;
      LAYER M1 ;
        RECT 59.700 52.600 65.100 57.600 ;
      LAYER M1 ;
        RECT 65.100 41.000 67.700 57.600 ;
      LAYER M1 ;
        RECT 67.700 52.600 73.100 57.600 ;
      LAYER M1 ;
        RECT 73.100 41.000 75.700 57.600 ;
      LAYER M1 ;
        RECT 75.700 55.000 84.600 57.600 ;
    END
  END VDD
  PIN GND
    DIRECTION INOUT ;
    USE GROUND ;
    PORT
      LAYER M1 ;
        RECT 5.000 0.000 9.100 2.600 ;
      LAYER M1 ;
        RECT 9.100 0.000 11.700 9.800 ;
      LAYER M1 ;
        RECT 11.700 0.000 17.100 5.000 ;
      LAYER M1 ;
        RECT 17.100 0.000 19.700 9.800 ;
      LAYER M1 ;
        RECT 19.700 0.000 25.100 5.000 ;
      LAYER M1 ;
        RECT 25.100 0.000 27.700 9.800 ;
      LAYER M1 ;
        RECT 27.700 0.000 33.100 5.000 ;
      LAYER M1 ;
        RECT 33.100 0.000 35.700 9.800 ;
      LAYER M1 ;
        RECT 35.700 0.000 41.100 5.000 ;
      LAYER M1 ;
        RECT 41.100 0.000 43.700 9.800 ;
      LAYER M1 ;
        RECT 43.700 0.000 49.100 5.000 ;
      LAYER M1 ;
        RECT 49.100 0.000 51.700 9.800 ;
      LAYER M1 ;
        RECT 51.700 0.000 57.100 5.000 ;
      LAYER M1 ;
        RECT 57.100 0.000 59.700 9.800 ;
      LAYER M1 ;
        RECT 59.700 0.000 65.100 5.000 ;
      LAYER M1 ;
        RECT 65.100 0.000 67.700 9.800 ;
      LAYER M1 ;
        RECT 67.700 0.000 73.100 5.000 ;
      LAYER M1 ;
        RECT 73.100 0.000 75.700 9.800 ;
      LAYER M1 ;
        RECT 75.700 0.000 84.600 2.600 ;
    END
  END GND
END INV_X16
MACRO INV_X2
  CLASS CORE ;
  ORIGIN 0 0 ;
  SIZE 29.100 BY 62.600 ;
  SYMMETRY X Y ;
  SITE TR1um_site ;
  PIN A
    DIRECTION INPUT ;
    USE SIGNAL ;
    PORT
      LAYER M1 ;
        RECT 10.100 27.100 10.300 30.500 ;
      LAYER M1 ;
        RECT 10.300 27.100 12.900 35.500 ;
      LAYER M1 ;
        RECT 12.900 27.100 13.500 30.500 ;
    END
  END A
  PIN Y
    DIRECTION OUTPUT ;
    USE SIGNAL ;
    PORT
      LAYER M1 ;
        RECT 13.100 6.400 15.600 17.800 ;
      LAYER M1 ;
        RECT 13.100 36.900 15.600 51.200 ;
      LAYER M1 ;
        RECT 15.600 6.400 15.700 17.800 ;
      LAYER M1 ;
        RECT 15.600 32.600 15.700 51.200 ;
      LAYER M1 ;
        RECT 15.700 15.200 16.000 17.800 ;
      LAYER M1 ;
        RECT 15.700 32.600 16.000 39.500 ;
      LAYER M1 ;
        RECT 16.000 15.200 18.600 39.500 ;
      LAYER M1 ;
        RECT 18.600 32.600 19.000 36.000 ;
    END
  END Y
  PIN VDD
    DIRECTION INOUT ;
    USE POWER ;
    PORT
      LAYER M1 ;
        RECT 5.000 55.000 9.100 57.600 ;
      LAYER M1 ;
        RECT 9.100 41.000 11.700 57.600 ;
      LAYER M1 ;
        RECT 11.700 52.600 17.100 57.600 ;
      LAYER M1 ;
        RECT 17.100 41.000 19.700 57.600 ;
      LAYER M1 ;
        RECT 19.700 55.000 24.100 57.600 ;
    END
  END VDD
  PIN GND
    DIRECTION INOUT ;
    USE GROUND ;
    PORT
      LAYER M1 ;
        RECT 5.000 0.000 9.100 2.600 ;
      LAYER M1 ;
        RECT 9.100 0.000 11.700 9.800 ;
      LAYER M1 ;
        RECT 11.700 0.000 17.100 5.000 ;
      LAYER M1 ;
        RECT 17.100 0.000 19.700 9.800 ;
      LAYER M1 ;
        RECT 19.700 0.000 24.100 2.600 ;
    END
  END GND
END INV_X2
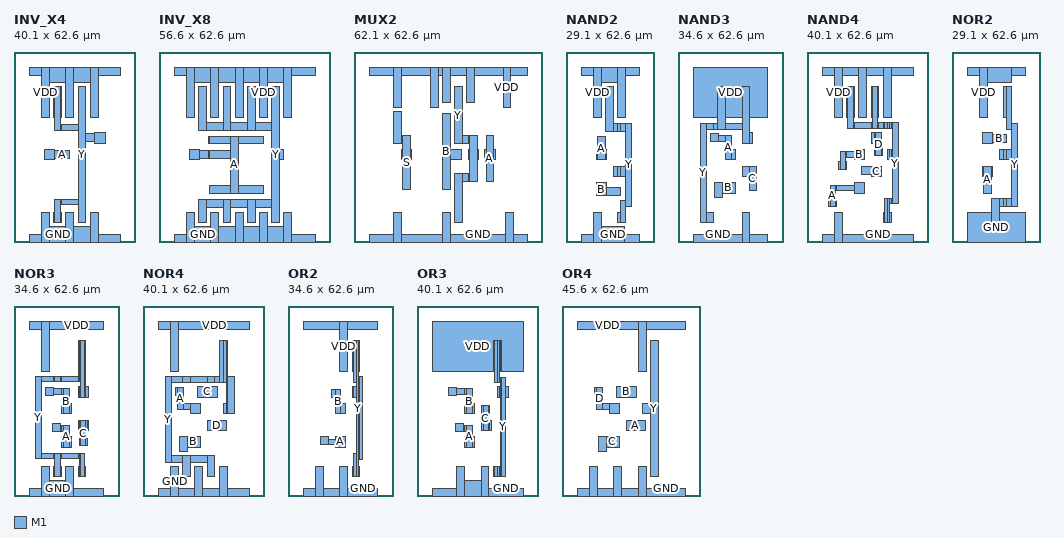
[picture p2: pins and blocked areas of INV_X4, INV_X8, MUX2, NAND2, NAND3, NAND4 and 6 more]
MACRO INV_X4
  CLASS CORE ;
  ORIGIN 0 0 ;
  SIZE 40.100 BY 62.600 ;
  SYMMETRY X Y ;
  SITE TR1um_site ;
  PIN Y
    DIRECTION OUTPUT ;
    USE SIGNAL ;
    PORT
      LAYER M1 ;
        RECT 13.100 6.400 13.500 9.800 ;
      LAYER M1 ;
        RECT 13.100 41.000 13.500 51.200 ;
      LAYER M1 ;
        RECT 13.500 6.400 15.300 14.000 ;
      LAYER M1 ;
        RECT 13.500 36.800 15.300 51.200 ;
      LAYER M1 ;
        RECT 15.300 6.400 15.700 9.800 ;
      LAYER M1 ;
        RECT 15.300 12.200 15.700 14.000 ;
      LAYER M1 ;
        RECT 15.300 36.800 15.700 38.600 ;
      LAYER M1 ;
        RECT 15.300 41.000 15.700 51.200 ;
      LAYER M1 ;
        RECT 15.700 12.200 21.100 14.000 ;
      LAYER M1 ;
        RECT 15.700 36.800 21.100 38.600 ;
      LAYER M1 ;
        RECT 21.100 6.400 23.700 51.200 ;
      LAYER M1 ;
        RECT 23.700 33.000 26.600 35.600 ;
      LAYER M1 ;
        RECT 26.600 32.600 30.000 36.000 ;
    END
  END Y
  PIN A
    DIRECTION INPUT ;
    USE SIGNAL ;
    PORT
      LAYER M1 ;
        RECT 10.100 27.100 13.500 30.500 ;
      LAYER M1 ;
        RECT 13.500 27.500 18.400 30.100 ;
    END
  END A
  PIN VDD
    DIRECTION INOUT ;
    USE POWER ;
    PORT
      LAYER M1 ;
        RECT 5.000 55.000 9.100 57.600 ;
      LAYER M1 ;
        RECT 9.100 41.000 11.700 57.600 ;
      LAYER M1 ;
        RECT 11.700 52.600 17.100 57.600 ;
      LAYER M1 ;
        RECT 17.100 41.000 19.700 57.600 ;
      LAYER M1 ;
        RECT 19.700 52.600 25.100 57.600 ;
      LAYER M1 ;
        RECT 25.100 41.000 27.700 57.600 ;
      LAYER M1 ;
        RECT 27.700 55.000 35.100 57.600 ;
    END
  END VDD
  PIN GND
    DIRECTION INOUT ;
    USE GROUND ;
    PORT
      LAYER M1 ;
        RECT 5.000 0.000 9.100 2.600 ;
      LAYER M1 ;
        RECT 9.100 0.000 11.700 9.800 ;
      LAYER M1 ;
        RECT 11.700 0.000 17.100 5.000 ;
      LAYER M1 ;
        RECT 17.100 0.000 19.700 9.800 ;
      LAYER M1 ;
        RECT 19.700 0.000 25.100 5.000 ;
      LAYER M1 ;
        RECT 25.100 0.000 27.700 9.800 ;
      LAYER M1 ;
        RECT 27.700 0.000 35.100 2.600 ;
    END
  END GND
END INV_X4
MACRO INV_X8
  CLASS CORE ;
  ORIGIN 0 0 ;
  SIZE 56.600 BY 62.600 ;
  SYMMETRY X Y ;
  SITE TR1um_site ;
  PIN Y
    DIRECTION OUTPUT ;
    USE SIGNAL ;
    PORT
      LAYER M1 ;
        RECT 13.100 6.400 15.700 14.000 ;
      LAYER M1 ;
        RECT 13.100 36.800 15.700 51.200 ;
      LAYER M1 ;
        RECT 15.700 11.400 21.100 14.000 ;
      LAYER M1 ;
        RECT 15.700 36.800 21.100 39.400 ;
      LAYER M1 ;
        RECT 21.100 6.400 23.700 14.000 ;
      LAYER M1 ;
        RECT 21.100 36.800 23.700 51.200 ;
      LAYER M1 ;
        RECT 23.700 11.400 29.100 14.000 ;
      LAYER M1 ;
        RECT 23.700 36.800 29.100 39.400 ;
      LAYER M1 ;
        RECT 29.100 6.400 31.700 14.000 ;
      LAYER M1 ;
        RECT 29.100 36.800 31.700 51.200 ;
      LAYER M1 ;
        RECT 31.700 11.400 37.100 14.000 ;
      LAYER M1 ;
        RECT 31.700 36.800 37.100 39.400 ;
      LAYER M1 ;
        RECT 37.100 6.400 39.700 51.200 ;
      LAYER M1 ;
        RECT 39.700 27.100 41.000 30.500 ;
    END
  END Y
  PIN A
    DIRECTION INPUT ;
    USE SIGNAL ;
    PORT
      LAYER M1 ;
        RECT 10.100 27.100 13.500 30.500 ;
      LAYER M1 ;
        RECT 13.500 27.500 16.400 30.100 ;
      LAYER M1 ;
        RECT 16.400 27.500 16.600 30.100 ;
      LAYER M1 ;
        RECT 16.400 32.300 16.600 34.900 ;
      LAYER M1 ;
        RECT 16.600 15.900 23.600 18.500 ;
      LAYER M1 ;
        RECT 16.600 27.500 23.600 30.100 ;
      LAYER M1 ;
        RECT 16.600 32.300 23.600 34.900 ;
      LAYER M1 ;
        RECT 23.600 15.900 26.200 34.900 ;
      LAYER M1 ;
        RECT 26.200 15.900 34.500 18.500 ;
      LAYER M1 ;
        RECT 26.200 32.300 34.500 34.900 ;
    END
  END A
  PIN VDD
    DIRECTION INOUT ;
    USE POWER ;
    PORT
      LAYER M1 ;
        RECT 5.000 55.000 9.100 57.600 ;
      LAYER M1 ;
        RECT 9.100 41.000 11.700 57.600 ;
      LAYER M1 ;
        RECT 11.700 52.600 17.100 57.600 ;
      LAYER M1 ;
        RECT 17.100 41.000 19.700 57.600 ;
      LAYER M1 ;
        RECT 19.700 52.600 25.100 57.600 ;
      LAYER M1 ;
        RECT 25.100 41.000 27.700 57.600 ;
      LAYER M1 ;
        RECT 27.700 52.600 33.100 57.600 ;
      LAYER M1 ;
        RECT 33.100 41.000 35.700 57.600 ;
      LAYER M1 ;
        RECT 35.700 52.600 41.100 57.600 ;
      LAYER M1 ;
        RECT 41.100 41.000 43.700 57.600 ;
      LAYER M1 ;
        RECT 43.700 55.000 51.600 57.600 ;
    END
  END VDD
  PIN GND
    DIRECTION INOUT ;
    USE GROUND ;
    PORT
      LAYER M1 ;
        RECT 5.000 0.000 9.100 2.600 ;
      LAYER M1 ;
        RECT 9.100 0.000 11.700 9.800 ;
      LAYER M1 ;
        RECT 11.700 0.000 17.100 5.000 ;
      LAYER M1 ;
        RECT 17.100 0.000 19.700 9.800 ;
      LAYER M1 ;
        RECT 19.700 0.000 25.100 5.000 ;
      LAYER M1 ;
        RECT 25.100 0.000 27.700 9.800 ;
      LAYER M1 ;
        RECT 27.700 0.000 33.100 5.000 ;
      LAYER M1 ;
        RECT 33.100 0.000 35.700 9.800 ;
      LAYER M1 ;
        RECT 35.700 0.000 41.100 5.000 ;
      LAYER M1 ;
        RECT 41.100 0.000 43.700 9.800 ;
      LAYER M1 ;
        RECT 43.700 0.000 51.600 2.600 ;
    END
  END GND
END INV_X8
MACRO MUX2
  CLASS CORE ;
  ORIGIN 0 0 ;
  SIZE 62.100 BY 62.600 ;
  SYMMETRY X Y ;
  SITE TR1um_site ;
  PIN S
    DIRECTION OUTPUT ;
    USE SIGNAL ;
    PORT
      LAYER M1 ;
        RECT 13.100 32.400 15.600 43.000 ;
      LAYER M1 ;
        RECT 15.600 27.100 15.700 30.500 ;
      LAYER M1 ;
        RECT 15.600 32.400 15.700 43.000 ;
      LAYER M1 ;
        RECT 15.700 27.100 16.000 30.500 ;
      LAYER M1 ;
        RECT 15.700 32.400 16.000 35.000 ;
      LAYER M1 ;
        RECT 16.000 17.200 18.600 35.000 ;
      LAYER M1 ;
        RECT 18.600 27.100 19.000 30.500 ;
    END
  END S
  PIN B
    DIRECTION INPUT ;
    USE SIGNAL ;
    PORT
      LAYER M1 ;
        RECT 29.100 17.200 31.700 42.300 ;
      LAYER M1 ;
        RECT 31.700 27.100 35.500 30.500 ;
    END
  END B
  PIN Y
    DIRECTION OUTPUT ;
    USE SIGNAL ;
    PORT
      LAYER M1 ;
        RECT 33.100 6.400 35.700 22.600 ;
      LAYER M1 ;
        RECT 33.100 32.400 35.700 51.200 ;
      LAYER M1 ;
        RECT 35.700 20.000 37.600 22.600 ;
      LAYER M1 ;
        RECT 35.700 32.400 37.600 35.000 ;
      LAYER M1 ;
        RECT 37.600 20.000 38.000 22.600 ;
      LAYER M1 ;
        RECT 37.600 27.100 38.000 30.500 ;
      LAYER M1 ;
        RECT 37.600 32.400 38.000 35.000 ;
      LAYER M1 ;
        RECT 38.000 20.000 40.600 35.000 ;
      LAYER M1 ;
        RECT 40.600 27.100 41.000 30.500 ;
    END
  END Y
  PIN A
    DIRECTION INPUT ;
    USE SIGNAL ;
    PORT
      LAYER M1 ;
        RECT 43.100 27.100 43.500 30.500 ;
      LAYER M1 ;
        RECT 43.500 20.000 46.100 35.000 ;
      LAYER M1 ;
        RECT 46.100 27.100 46.500 30.500 ;
    END
  END A
  PIN GND
    DIRECTION INOUT ;
    USE GROUND ;
    PORT
      LAYER M1 ;
        RECT 5.000 0.000 13.100 2.600 ;
      LAYER M1 ;
        RECT 13.100 0.000 15.700 9.800 ;
      LAYER M1 ;
        RECT 15.700 0.000 29.100 2.600 ;
      LAYER M1 ;
        RECT 29.100 0.000 31.700 9.800 ;
      LAYER M1 ;
        RECT 31.700 0.000 49.900 2.600 ;
      LAYER M1 ;
        RECT 49.900 0.000 52.500 9.800 ;
      LAYER M1 ;
        RECT 52.500 0.000 57.100 2.600 ;
    END
  END GND
  PIN VDD
    DIRECTION INOUT ;
    USE POWER ;
    PORT
      LAYER M1 ;
        RECT 5.000 55.000 13.100 57.600 ;
      LAYER M1 ;
        RECT 13.100 44.400 15.700 57.600 ;
      LAYER M1 ;
        RECT 15.700 55.000 25.100 57.600 ;
      LAYER M1 ;
        RECT 25.100 44.400 27.700 57.600 ;
      LAYER M1 ;
        RECT 27.700 55.000 29.100 57.600 ;
      LAYER M1 ;
        RECT 29.100 46.100 31.700 57.600 ;
      LAYER M1 ;
        RECT 31.700 55.000 37.100 57.600 ;
      LAYER M1 ;
        RECT 37.100 46.100 39.700 57.600 ;
      LAYER M1 ;
        RECT 39.700 55.000 49.100 57.600 ;
      LAYER M1 ;
        RECT 49.100 44.400 51.700 57.600 ;
      LAYER M1 ;
        RECT 51.700 55.000 57.100 57.600 ;
    END
  END VDD
END MUX2
MACRO NAND2
  CLASS CORE ;
  ORIGIN 0 0 ;
  SIZE 29.100 BY 62.600 ;
  SYMMETRY X Y ;
  SITE TR1um_site ;
  PIN GND
    DIRECTION INOUT ;
    USE GROUND ;
    PORT
      LAYER M1 ;
        RECT 5.000 0.000 9.100 2.600 ;
      LAYER M1 ;
        RECT 9.100 0.000 11.700 9.800 ;
      LAYER M1 ;
        RECT 11.700 0.000 19.300 5.000 ;
      LAYER M1 ;
        RECT 19.300 0.000 24.100 2.600 ;
    END
  END GND
  PIN Y
    DIRECTION OUTPUT ;
    USE SIGNAL ;
    PORT
      LAYER M1 ;
        RECT 13.100 36.400 15.600 51.200 ;
      LAYER M1 ;
        RECT 15.600 21.600 15.700 25.000 ;
      LAYER M1 ;
        RECT 15.600 36.400 15.700 51.200 ;
      LAYER M1 ;
        RECT 15.700 21.600 17.100 25.000 ;
      LAYER M1 ;
        RECT 15.700 36.400 17.100 39.000 ;
      LAYER M1 ;
        RECT 17.100 6.400 17.900 9.800 ;
      LAYER M1 ;
        RECT 17.100 21.600 17.900 25.000 ;
      LAYER M1 ;
        RECT 17.100 36.400 17.900 39.000 ;
      LAYER M1 ;
        RECT 17.900 6.400 19.700 13.600 ;
      LAYER M1 ;
        RECT 17.900 21.600 19.700 25.000 ;
      LAYER M1 ;
        RECT 17.900 36.400 19.700 39.000 ;
      LAYER M1 ;
        RECT 19.700 11.800 21.500 39.000 ;
    END
  END Y
  PIN B
    DIRECTION INPUT ;
    USE SIGNAL ;
    PORT
      LAYER M1 ;
        RECT 10.100 15.300 13.500 19.500 ;
      LAYER M1 ;
        RECT 13.500 15.300 18.100 17.900 ;
    END
  END B
  PIN A
    DIRECTION INPUT ;
    USE SIGNAL ;
    PORT
      LAYER M1 ;
        RECT 10.100 27.100 10.300 30.500 ;
      LAYER M1 ;
        RECT 10.300 27.100 12.900 34.800 ;
      LAYER M1 ;
        RECT 12.900 27.100 13.500 30.500 ;
    END
  END A
  PIN VDD
    DIRECTION INOUT ;
    USE POWER ;
    PORT
      LAYER M1 ;
        RECT 5.000 55.000 9.100 57.600 ;
      LAYER M1 ;
        RECT 9.100 41.000 11.700 57.600 ;
      LAYER M1 ;
        RECT 11.700 52.600 17.100 57.600 ;
      LAYER M1 ;
        RECT 17.100 41.000 19.700 57.600 ;
      LAYER M1 ;
        RECT 19.700 55.000 24.100 57.600 ;
    END
  END VDD
END NAND2
MACRO NAND3
  CLASS CORE ;
  ORIGIN 0 0 ;
  SIZE 34.600 BY 62.600 ;
  SYMMETRY X Y ;
  SITE TR1um_site ;
  PIN Y
    DIRECTION OUTPUT ;
    USE SIGNAL ;
    PORT
      LAYER M1 ;
        RECT 7.300 6.400 9.300 39.200 ;
      LAYER M1 ;
        RECT 9.300 6.400 11.700 9.800 ;
      LAYER M1 ;
        RECT 9.300 37.200 11.700 39.200 ;
      LAYER M1 ;
        RECT 11.700 37.200 13.100 39.200 ;
      LAYER M1 ;
        RECT 13.100 37.200 15.700 51.200 ;
      LAYER M1 ;
        RECT 15.700 37.200 21.100 39.200 ;
      LAYER M1 ;
        RECT 21.100 32.600 23.700 51.200 ;
      LAYER M1 ;
        RECT 23.700 32.600 24.500 36.000 ;
    END
  END Y
  PIN A
    DIRECTION INPUT ;
    USE SIGNAL ;
    PORT
      LAYER M1 ;
        RECT 10.700 33.200 13.300 35.800 ;
      LAYER M1 ;
        RECT 13.300 33.200 15.600 35.200 ;
      LAYER M1 ;
        RECT 15.600 27.100 17.600 35.200 ;
      LAYER M1 ;
        RECT 17.600 27.100 19.000 30.500 ;
    END
  END A
  PIN C
    DIRECTION INPUT ;
    USE SIGNAL ;
    PORT
      LAYER M1 ;
        RECT 21.100 21.600 23.400 25.000 ;
      LAYER M1 ;
        RECT 23.400 16.950 26.000 25.000 ;
    END
  END C
  PIN B
    DIRECTION INPUT ;
    USE SIGNAL ;
    PORT
      LAYER M1 ;
        RECT 12.000 14.600 14.600 19.500 ;
      LAYER M1 ;
        RECT 14.600 16.100 19.000 19.500 ;
    END
  END B
  PIN GND
    DIRECTION INOUT ;
    USE GROUND ;
    PORT
      LAYER M1 ;
        RECT 5.000 0.000 21.100 2.600 ;
      LAYER M1 ;
        RECT 21.100 0.000 23.700 9.800 ;
      LAYER M1 ;
        RECT 23.700 0.000 29.600 2.600 ;
    END
  END GND
  PIN VDD
    DIRECTION INOUT ;
    USE POWER ;
    PORT
      LAYER M1 ;
        RECT 5.000 41.000 29.600 57.600 ;
    END
  END VDD
END NAND3
MACRO NAND4
  CLASS CORE ;
  ORIGIN 0 0 ;
  SIZE 40.100 BY 62.600 ;
  SYMMETRY X Y ;
  SITE TR1um_site ;
  PIN Y
    DIRECTION OUTPUT ;
    USE SIGNAL ;
    PORT
      LAYER M1 ;
        RECT 13.100 41.000 13.500 51.200 ;
      LAYER M1 ;
        RECT 13.500 37.500 15.300 51.200 ;
      LAYER M1 ;
        RECT 15.300 37.500 15.700 39.300 ;
      LAYER M1 ;
        RECT 15.300 41.000 15.700 51.200 ;
      LAYER M1 ;
        RECT 15.700 37.500 21.100 39.300 ;
      LAYER M1 ;
        RECT 21.100 37.500 21.500 39.300 ;
      LAYER M1 ;
        RECT 21.100 41.000 21.500 51.200 ;
      LAYER M1 ;
        RECT 21.500 37.500 23.300 51.200 ;
      LAYER M1 ;
        RECT 23.300 37.500 23.700 39.300 ;
      LAYER M1 ;
        RECT 23.300 41.000 23.700 51.200 ;
      LAYER M1 ;
        RECT 23.700 37.500 25.100 39.300 ;
      LAYER M1 ;
        RECT 25.100 6.400 25.500 9.800 ;
      LAYER M1 ;
        RECT 25.100 37.500 25.500 39.300 ;
      LAYER M1 ;
        RECT 25.500 6.400 26.600 14.400 ;
      LAYER M1 ;
        RECT 25.500 37.500 26.600 39.300 ;
      LAYER M1 ;
        RECT 26.600 6.400 27.300 14.400 ;
      LAYER M1 ;
        RECT 26.600 27.100 27.300 30.500 ;
      LAYER M1 ;
        RECT 26.600 37.500 27.300 39.300 ;
      LAYER M1 ;
        RECT 27.300 6.400 27.700 9.800 ;
      LAYER M1 ;
        RECT 27.300 12.600 27.700 14.400 ;
      LAYER M1 ;
        RECT 27.300 27.100 27.700 30.500 ;
      LAYER M1 ;
        RECT 27.300 37.500 27.700 39.300 ;
      LAYER M1 ;
        RECT 27.700 12.600 28.200 14.400 ;
      LAYER M1 ;
        RECT 27.700 27.100 28.200 30.500 ;
      LAYER M1 ;
        RECT 27.700 37.500 28.200 39.300 ;
      LAYER M1 ;
        RECT 28.200 12.600 30.000 39.300 ;
    END
  END Y
  PIN A
    DIRECTION INPUT ;
    USE SIGNAL ;
    PORT
      LAYER M1 ;
        RECT 7.200 11.700 7.600 14.300 ;
      LAYER M1 ;
        RECT 7.600 11.700 9.400 18.700 ;
      LAYER M1 ;
        RECT 9.400 11.700 9.800 14.300 ;
      LAYER M1 ;
        RECT 9.400 16.900 9.800 18.700 ;
      LAYER M1 ;
        RECT 9.800 16.900 15.600 18.700 ;
      LAYER M1 ;
        RECT 15.600 16.100 19.000 19.500 ;
    END
  END A
  PIN B
    DIRECTION INPUT ;
    USE SIGNAL ;
    PORT
      LAYER M1 ;
        RECT 10.500 23.900 10.900 26.500 ;
      LAYER M1 ;
        RECT 10.900 23.900 12.700 29.800 ;
      LAYER M1 ;
        RECT 12.700 23.900 13.100 26.500 ;
      LAYER M1 ;
        RECT 12.700 28.000 13.100 29.800 ;
      LAYER M1 ;
        RECT 13.100 28.000 15.600 29.800 ;
      LAYER M1 ;
        RECT 15.600 27.100 19.000 30.500 ;
    END
  END B
  PIN C
    DIRECTION INPUT ;
    USE SIGNAL ;
    PORT
      LAYER M1 ;
        RECT 17.900 22.400 21.100 25.000 ;
      LAYER M1 ;
        RECT 21.100 21.600 24.500 25.000 ;
    END
  END C
  PIN D
    DIRECTION INPUT ;
    USE SIGNAL ;
    PORT
      LAYER M1 ;
        RECT 21.100 32.600 22.200 36.000 ;
      LAYER M1 ;
        RECT 22.200 28.400 22.700 31.000 ;
      LAYER M1 ;
        RECT 22.200 32.600 22.700 36.000 ;
      LAYER M1 ;
        RECT 22.700 28.400 24.500 36.000 ;
      LAYER M1 ;
        RECT 24.500 28.400 24.800 31.000 ;
    END
  END D
  PIN VDD
    DIRECTION INOUT ;
    USE POWER ;
    PORT
      LAYER M1 ;
        RECT 5.000 55.000 9.100 57.600 ;
      LAYER M1 ;
        RECT 9.100 41.000 11.700 57.600 ;
      LAYER M1 ;
        RECT 11.700 55.000 17.100 57.600 ;
      LAYER M1 ;
        RECT 17.100 41.000 19.700 57.600 ;
      LAYER M1 ;
        RECT 19.700 55.000 25.100 57.600 ;
      LAYER M1 ;
        RECT 25.100 41.000 27.700 57.600 ;
      LAYER M1 ;
        RECT 27.700 55.000 35.100 57.600 ;
    END
  END VDD
  PIN GND
    DIRECTION INOUT ;
    USE GROUND ;
    PORT
      LAYER M1 ;
        RECT 5.000 0.000 9.100 2.600 ;
      LAYER M1 ;
        RECT 9.100 0.000 11.700 9.800 ;
      LAYER M1 ;
        RECT 11.700 0.000 35.100 2.600 ;
    END
  END GND
END NAND4
MACRO NOR2
  CLASS CORE ;
  ORIGIN 0 0 ;
  SIZE 29.100 BY 62.600 ;
  SYMMETRY X Y ;
  SITE TR1um_site ;
  PIN A
    DIRECTION INPUT ;
    USE SIGNAL ;
    PORT
      LAYER M1 ;
        RECT 10.100 21.600 10.300 25.000 ;
      LAYER M1 ;
        RECT 10.300 16.000 12.900 25.000 ;
      LAYER M1 ;
        RECT 12.900 21.600 13.500 25.000 ;
    END
  END A
  PIN B
    DIRECTION INPUT ;
    USE SIGNAL ;
    PORT
      LAYER M1 ;
        RECT 10.100 32.600 13.500 36.000 ;
      LAYER M1 ;
        RECT 13.500 32.900 18.100 35.500 ;
    END
  END B
  PIN Y
    DIRECTION OUTPUT ;
    USE SIGNAL ;
    PORT
      LAYER M1 ;
        RECT 13.100 6.400 15.600 14.400 ;
      LAYER M1 ;
        RECT 15.600 6.400 15.700 14.400 ;
      LAYER M1 ;
        RECT 15.600 27.100 15.700 30.500 ;
      LAYER M1 ;
        RECT 15.700 11.800 17.100 14.400 ;
      LAYER M1 ;
        RECT 15.700 27.100 17.100 30.500 ;
      LAYER M1 ;
        RECT 17.100 11.800 17.900 14.400 ;
      LAYER M1 ;
        RECT 17.100 27.100 17.900 30.500 ;
      LAYER M1 ;
        RECT 17.100 41.000 17.900 51.200 ;
      LAYER M1 ;
        RECT 17.900 11.800 19.700 14.400 ;
      LAYER M1 ;
        RECT 17.900 27.100 19.700 30.500 ;
      LAYER M1 ;
        RECT 17.900 37.200 19.700 51.200 ;
      LAYER M1 ;
        RECT 19.700 11.800 21.500 39.000 ;
    END
  END Y
  PIN VDD
    DIRECTION INOUT ;
    USE POWER ;
    PORT
      LAYER M1 ;
        RECT 5.000 55.000 9.100 57.600 ;
      LAYER M1 ;
        RECT 9.100 41.000 11.700 57.600 ;
      LAYER M1 ;
        RECT 11.700 52.600 19.700 57.600 ;
      LAYER M1 ;
        RECT 19.700 55.000 24.100 57.600 ;
    END
  END VDD
  PIN GND
    DIRECTION INOUT ;
    USE GROUND ;
    PORT
      LAYER M1 ;
        RECT 5.000 0.000 24.100 9.800 ;
    END
  END GND
END NOR2
MACRO NOR3
  CLASS CORE ;
  ORIGIN 0 0 ;
  SIZE 34.600 BY 62.600 ;
  SYMMETRY X Y ;
  SITE TR1um_site ;
  PIN Y
    DIRECTION OUTPUT ;
    USE SIGNAL ;
    PORT
      LAYER M1 ;
        RECT 7.100 12.300 8.900 39.500 ;
      LAYER M1 ;
        RECT 8.900 12.300 13.100 14.100 ;
      LAYER M1 ;
        RECT 8.900 37.700 13.100 39.500 ;
      LAYER M1 ;
        RECT 13.100 6.400 13.500 9.800 ;
      LAYER M1 ;
        RECT 13.100 12.300 13.500 14.100 ;
      LAYER M1 ;
        RECT 13.100 37.700 13.500 39.500 ;
      LAYER M1 ;
        RECT 13.500 6.400 15.300 14.100 ;
      LAYER M1 ;
        RECT 13.500 37.700 15.300 39.500 ;
      LAYER M1 ;
        RECT 15.300 6.400 15.700 9.800 ;
      LAYER M1 ;
        RECT 15.300 12.300 15.700 14.100 ;
      LAYER M1 ;
        RECT 15.300 37.700 15.700 39.500 ;
      LAYER M1 ;
        RECT 15.700 12.300 21.100 14.100 ;
      LAYER M1 ;
        RECT 15.700 37.700 21.100 39.500 ;
      LAYER M1 ;
        RECT 21.100 6.400 21.500 9.800 ;
      LAYER M1 ;
        RECT 21.100 12.300 21.500 14.100 ;
      LAYER M1 ;
        RECT 21.100 32.600 21.500 36.000 ;
      LAYER M1 ;
        RECT 21.100 37.700 21.500 51.200 ;
      LAYER M1 ;
        RECT 21.500 6.400 21.900 14.100 ;
      LAYER M1 ;
        RECT 21.500 32.600 21.900 36.000 ;
      LAYER M1 ;
        RECT 21.500 37.700 21.900 51.200 ;
      LAYER M1 ;
        RECT 21.900 6.400 23.300 14.100 ;
      LAYER M1 ;
        RECT 21.900 32.600 23.300 51.200 ;
      LAYER M1 ;
        RECT 23.300 6.400 23.700 9.800 ;
      LAYER M1 ;
        RECT 23.300 32.600 23.700 51.200 ;
      LAYER M1 ;
        RECT 23.700 32.600 24.500 36.000 ;
    END
  END Y
  PIN A
    DIRECTION INPUT ;
    USE SIGNAL ;
    PORT
      LAYER M1 ;
        RECT 12.600 21.300 15.200 23.900 ;
      LAYER M1 ;
        RECT 15.200 21.300 15.600 23.100 ;
      LAYER M1 ;
        RECT 15.600 16.100 16.400 19.500 ;
      LAYER M1 ;
        RECT 15.600 21.300 16.400 23.100 ;
      LAYER M1 ;
        RECT 16.400 16.100 18.200 23.100 ;
      LAYER M1 ;
        RECT 18.200 16.100 19.000 19.500 ;
    END
  END A
  PIN B
    DIRECTION INPUT ;
    USE SIGNAL ;
    PORT
      LAYER M1 ;
        RECT 10.400 33.100 13.000 35.700 ;
      LAYER M1 ;
        RECT 13.000 33.500 15.600 35.300 ;
      LAYER M1 ;
        RECT 15.600 27.100 16.400 30.500 ;
      LAYER M1 ;
        RECT 15.600 33.500 16.400 35.300 ;
      LAYER M1 ;
        RECT 16.400 27.100 18.200 35.300 ;
      LAYER M1 ;
        RECT 18.200 27.100 19.000 30.500 ;
    END
  END B
  PIN C
    DIRECTION INPUT ;
    USE SIGNAL ;
    PORT
      LAYER M1 ;
        RECT 21.100 21.600 21.500 25.000 ;
      LAYER M1 ;
        RECT 21.500 16.500 21.900 19.100 ;
      LAYER M1 ;
        RECT 21.500 21.600 21.900 25.000 ;
      LAYER M1 ;
        RECT 21.900 16.500 23.700 25.000 ;
      LAYER M1 ;
        RECT 23.700 16.500 24.100 19.100 ;
      LAYER M1 ;
        RECT 23.700 21.600 24.100 25.000 ;
      LAYER M1 ;
        RECT 24.100 21.600 24.500 25.000 ;
    END
  END C
  PIN VDD
    DIRECTION INOUT ;
    USE POWER ;
    PORT
      LAYER M1 ;
        RECT 5.000 55.000 9.100 57.600 ;
      LAYER M1 ;
        RECT 9.100 41.000 11.700 57.600 ;
      LAYER M1 ;
        RECT 11.700 55.000 29.600 57.600 ;
    END
  END VDD
  PIN GND
    DIRECTION INOUT ;
    USE GROUND ;
    PORT
      LAYER M1 ;
        RECT 5.000 0.000 9.100 2.600 ;
      LAYER M1 ;
        RECT 9.100 0.000 11.700 9.800 ;
      LAYER M1 ;
        RECT 11.700 0.000 17.100 5.000 ;
      LAYER M1 ;
        RECT 17.100 0.000 19.700 9.800 ;
      LAYER M1 ;
        RECT 19.700 0.000 29.600 2.600 ;
    END
  END GND
END NOR3
MACRO NOR4
  CLASS CORE ;
  ORIGIN 0 0 ;
  SIZE 40.100 BY 62.600 ;
  SYMMETRY X Y ;
  SITE TR1um_site ;
  PIN VDD
    DIRECTION INOUT ;
    USE POWER ;
    PORT
      LAYER M1 ;
        RECT 5.000 55.000 9.100 57.600 ;
      LAYER M1 ;
        RECT 9.100 41.000 11.700 57.600 ;
      LAYER M1 ;
        RECT 11.700 55.000 35.100 57.600 ;
    END
  END VDD
  PIN C
    DIRECTION INPUT ;
    USE SIGNAL ;
    PORT
      LAYER M1 ;
        RECT 18.100 32.600 24.500 36.000 ;
    END
  END C
  PIN Y
    DIRECTION OUTPUT ;
    USE SIGNAL ;
    PORT
      LAYER M1 ;
        RECT 7.300 11.200 9.300 39.400 ;
      LAYER M1 ;
        RECT 9.300 11.200 13.100 13.200 ;
      LAYER M1 ;
        RECT 9.300 37.400 13.100 39.400 ;
      LAYER M1 ;
        RECT 13.100 6.400 15.700 13.200 ;
      LAYER M1 ;
        RECT 13.100 37.400 15.700 39.400 ;
      LAYER M1 ;
        RECT 15.700 11.200 21.100 13.200 ;
      LAYER M1 ;
        RECT 15.700 37.400 21.100 39.400 ;
      LAYER M1 ;
        RECT 21.100 6.400 23.700 13.200 ;
      LAYER M1 ;
        RECT 21.100 37.400 23.700 39.400 ;
      LAYER M1 ;
        RECT 23.700 37.400 25.100 39.400 ;
      LAYER M1 ;
        RECT 25.100 37.400 26.600 51.200 ;
      LAYER M1 ;
        RECT 26.600 27.100 27.400 30.500 ;
      LAYER M1 ;
        RECT 26.600 37.400 27.400 51.200 ;
      LAYER M1 ;
        RECT 27.400 27.100 27.700 51.200 ;
      LAYER M1 ;
        RECT 27.700 27.100 30.000 39.400 ;
    END
  END Y
  PIN A
    DIRECTION INPUT ;
    USE SIGNAL ;
    PORT
      LAYER M1 ;
        RECT 10.700 33.200 11.300 35.800 ;
      LAYER M1 ;
        RECT 11.300 28.500 13.300 35.800 ;
      LAYER M1 ;
        RECT 13.300 28.500 15.600 30.500 ;
      LAYER M1 ;
        RECT 15.600 27.100 19.000 30.500 ;
    END
  END A
  PIN D
    DIRECTION INPUT ;
    USE SIGNAL ;
    PORT
      LAYER M1 ;
        RECT 21.100 21.600 27.600 25.000 ;
    END
  END D
  PIN B
    DIRECTION INPUT ;
    USE SIGNAL ;
    PORT
      LAYER M1 ;
        RECT 12.000 14.600 14.600 19.500 ;
      LAYER M1 ;
        RECT 14.600 16.100 19.000 19.500 ;
    END
  END B
  PIN GND
    DIRECTION INOUT ;
    USE GROUND ;
    PORT
      LAYER M1 ;
        RECT 5.000 0.000 9.100 2.600 ;
      LAYER M1 ;
        RECT 9.100 0.000 11.700 9.800 ;
      LAYER M1 ;
        RECT 11.700 0.000 17.100 2.600 ;
      LAYER M1 ;
        RECT 17.100 0.000 19.700 9.800 ;
      LAYER M1 ;
        RECT 19.700 0.000 25.100 2.600 ;
      LAYER M1 ;
        RECT 25.100 0.000 27.700 9.800 ;
      LAYER M1 ;
        RECT 27.700 0.000 35.100 2.600 ;
    END
  END GND
END NOR4
MACRO OR2
  CLASS CORE ;
  ORIGIN 0 0 ;
  SIZE 34.600 BY 62.600 ;
  SYMMETRY X Y ;
  SITE TR1um_site ;
  PIN Y
    DIRECTION OUTPUT ;
    USE SIGNAL ;
    PORT
      LAYER M1 ;
        RECT 21.100 6.400 21.500 9.800 ;
      LAYER M1 ;
        RECT 21.100 32.600 21.500 36.000 ;
      LAYER M1 ;
        RECT 21.100 41.000 21.500 51.200 ;
      LAYER M1 ;
        RECT 21.500 6.400 22.700 13.900 ;
      LAYER M1 ;
        RECT 21.500 32.600 22.700 36.000 ;
      LAYER M1 ;
        RECT 21.500 37.500 22.700 51.200 ;
      LAYER M1 ;
        RECT 22.700 6.400 23.300 51.200 ;
      LAYER M1 ;
        RECT 23.300 6.400 23.700 9.800 ;
      LAYER M1 ;
        RECT 23.300 12.100 23.700 39.300 ;
      LAYER M1 ;
        RECT 23.300 41.000 23.700 51.200 ;
      LAYER M1 ;
        RECT 23.700 12.100 24.500 39.300 ;
    END
  END Y
  PIN A
    DIRECTION INPUT ;
    USE SIGNAL ;
    PORT
      LAYER M1 ;
        RECT 10.600 16.900 13.200 19.500 ;
      LAYER M1 ;
        RECT 13.200 16.900 15.600 18.700 ;
      LAYER M1 ;
        RECT 15.600 16.100 19.000 19.500 ;
    END
  END A
  PIN B
    DIRECTION INPUT ;
    USE SIGNAL ;
    PORT
      LAYER M1 ;
        RECT 14.400 32.600 15.600 35.200 ;
      LAYER M1 ;
        RECT 15.600 27.100 17.400 35.200 ;
      LAYER M1 ;
        RECT 17.400 27.100 19.000 30.500 ;
    END
  END B
  PIN VDD
    DIRECTION INOUT ;
    USE POWER ;
    PORT
      LAYER M1 ;
        RECT 5.000 55.000 17.100 57.600 ;
      LAYER M1 ;
        RECT 17.100 41.000 19.700 57.600 ;
      LAYER M1 ;
        RECT 19.700 55.000 29.600 57.600 ;
    END
  END VDD
  PIN GND
    DIRECTION INOUT ;
    USE GROUND ;
    PORT
      LAYER M1 ;
        RECT 5.000 0.000 9.100 2.600 ;
      LAYER M1 ;
        RECT 9.100 0.000 11.700 9.800 ;
      LAYER M1 ;
        RECT 11.700 0.000 17.100 2.600 ;
      LAYER M1 ;
        RECT 17.100 0.000 19.700 9.800 ;
      LAYER M1 ;
        RECT 19.700 0.000 29.600 2.600 ;
    END
  END GND
END OR2
MACRO OR3
  CLASS CORE ;
  ORIGIN 0 0 ;
  SIZE 40.100 BY 62.600 ;
  SYMMETRY X Y ;
  SITE TR1um_site ;
  PIN Y
    DIRECTION OUTPUT ;
    USE SIGNAL ;
    PORT
      LAYER M1 ;
        RECT 25.100 6.400 25.500 9.800 ;
      LAYER M1 ;
        RECT 25.100 41.000 25.500 51.200 ;
      LAYER M1 ;
        RECT 25.500 6.400 26.600 9.800 ;
      LAYER M1 ;
        RECT 25.500 37.400 26.600 51.200 ;
      LAYER M1 ;
        RECT 26.600 6.400 27.300 9.800 ;
      LAYER M1 ;
        RECT 26.600 32.600 27.300 36.000 ;
      LAYER M1 ;
        RECT 26.600 37.400 27.300 51.200 ;
      LAYER M1 ;
        RECT 27.300 6.400 27.400 9.800 ;
      LAYER M1 ;
        RECT 27.300 32.600 27.400 36.000 ;
      LAYER M1 ;
        RECT 27.300 37.400 27.400 39.200 ;
      LAYER M1 ;
        RECT 27.300 41.000 27.400 51.200 ;
      LAYER M1 ;
        RECT 27.400 6.400 27.700 39.200 ;
      LAYER M1 ;
        RECT 27.400 41.000 27.700 51.200 ;
      LAYER M1 ;
        RECT 27.700 6.400 29.200 39.200 ;
      LAYER M1 ;
        RECT 29.200 32.600 30.000 36.000 ;
    END
  END Y
  PIN A
    DIRECTION INPUT ;
    USE SIGNAL ;
    PORT
      LAYER M1 ;
        RECT 12.600 21.300 15.200 23.900 ;
      LAYER M1 ;
        RECT 15.200 21.300 15.600 23.100 ;
      LAYER M1 ;
        RECT 15.600 16.100 16.400 19.500 ;
      LAYER M1 ;
        RECT 15.600 21.300 16.400 23.100 ;
      LAYER M1 ;
        RECT 16.400 16.100 18.200 23.100 ;
      LAYER M1 ;
        RECT 18.200 16.100 19.000 19.500 ;
    END
  END A
  PIN B
    DIRECTION INPUT ;
    USE SIGNAL ;
    PORT
      LAYER M1 ;
        RECT 10.400 33.100 13.000 35.700 ;
      LAYER M1 ;
        RECT 13.000 33.500 15.600 35.300 ;
      LAYER M1 ;
        RECT 15.600 27.100 16.400 30.500 ;
      LAYER M1 ;
        RECT 15.600 33.500 16.400 35.300 ;
      LAYER M1 ;
        RECT 16.400 27.100 18.200 35.300 ;
      LAYER M1 ;
        RECT 18.200 27.100 19.000 30.500 ;
    END
  END B
  PIN C
    DIRECTION INPUT ;
    USE SIGNAL ;
    PORT
      LAYER M1 ;
        RECT 21.100 21.600 21.400 25.000 ;
      LAYER M1 ;
        RECT 21.400 21.600 21.800 25.000 ;
      LAYER M1 ;
        RECT 21.400 27.100 21.800 29.700 ;
      LAYER M1 ;
        RECT 21.800 21.600 23.600 29.700 ;
      LAYER M1 ;
        RECT 23.600 21.600 24.000 25.000 ;
      LAYER M1 ;
        RECT 23.600 27.100 24.000 29.700 ;
      LAYER M1 ;
        RECT 24.000 21.600 24.500 25.000 ;
    END
  END C
  PIN GND
    DIRECTION INOUT ;
    USE GROUND ;
    PORT
      LAYER M1 ;
        RECT 5.000 0.000 13.100 2.600 ;
      LAYER M1 ;
        RECT 13.100 0.000 15.700 9.800 ;
      LAYER M1 ;
        RECT 15.700 0.000 21.100 5.000 ;
      LAYER M1 ;
        RECT 21.100 0.000 23.700 9.800 ;
      LAYER M1 ;
        RECT 23.700 0.000 35.100 2.600 ;
    END
  END GND
  PIN VDD
    DIRECTION INOUT ;
    USE POWER ;
    PORT
      LAYER M1 ;
        RECT 5.000 41.000 35.100 57.600 ;
    END
  END VDD
END OR3
MACRO OR4
  CLASS CORE ;
  ORIGIN 0 0 ;
  SIZE 45.600 BY 62.600 ;
  SYMMETRY X Y ;
  SITE TR1um_site ;
  PIN A
    DIRECTION INPUT ;
    USE SIGNAL ;
    PORT
      LAYER M1 ;
        RECT 21.100 21.600 27.600 25.000 ;
    END
  END A
  PIN B
    DIRECTION INPUT ;
    USE SIGNAL ;
    PORT
      LAYER M1 ;
        RECT 18.100 32.600 24.500 36.000 ;
    END
  END B
  PIN C
    DIRECTION INPUT ;
    USE SIGNAL ;
    PORT
      LAYER M1 ;
        RECT 12.000 14.600 14.600 19.500 ;
      LAYER M1 ;
        RECT 14.600 16.100 19.000 19.500 ;
    END
  END C
  PIN D
    DIRECTION INPUT ;
    USE SIGNAL ;
    PORT
      LAYER M1 ;
        RECT 10.700 33.200 11.300 35.800 ;
      LAYER M1 ;
        RECT 11.300 28.500 13.300 35.800 ;
      LAYER M1 ;
        RECT 13.300 28.500 15.600 30.500 ;
      LAYER M1 ;
        RECT 15.600 27.100 19.000 30.500 ;
    END
  END D
  PIN Y
    DIRECTION OUTPUT ;
    USE SIGNAL ;
    PORT
      LAYER M1 ;
        RECT 26.600 27.100 29.100 30.500 ;
      LAYER M1 ;
        RECT 29.100 6.400 31.700 51.200 ;
    END
  END Y
  PIN VDD
    DIRECTION INOUT ;
    USE POWER ;
    PORT
      LAYER M1 ;
        RECT 5.000 55.000 25.100 57.600 ;
      LAYER M1 ;
        RECT 25.100 41.000 27.700 57.600 ;
      LAYER M1 ;
        RECT 27.700 55.000 40.600 57.600 ;
    END
  END VDD
  PIN GND
    DIRECTION INOUT ;
    USE GROUND ;
    PORT
      LAYER M1 ;
        RECT 5.000 0.000 9.100 2.600 ;
      LAYER M1 ;
        RECT 9.100 0.000 11.700 9.800 ;
      LAYER M1 ;
        RECT 11.700 0.000 17.100 2.600 ;
      LAYER M1 ;
        RECT 17.100 0.000 19.700 9.800 ;
      LAYER M1 ;
        RECT 19.700 0.000 25.100 2.600 ;
      LAYER M1 ;
        RECT 25.100 0.000 27.700 9.800 ;
      LAYER M1 ;
        RECT 27.700 0.000 40.600 2.600 ;
    END
  END GND
END OR4
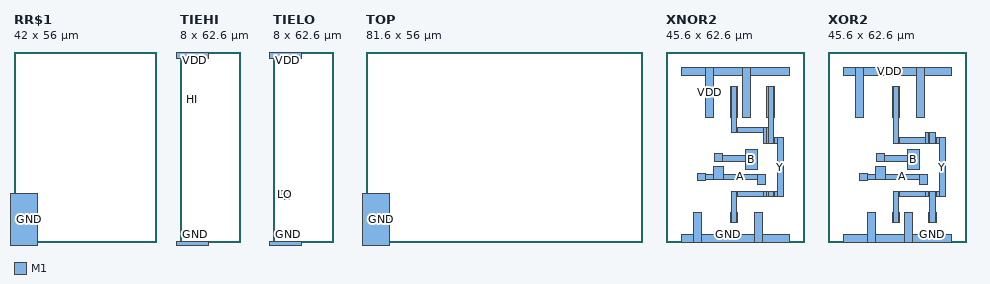
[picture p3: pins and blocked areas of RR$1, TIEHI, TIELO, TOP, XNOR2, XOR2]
MACRO RR$1
  CLASS CORE ;
  ORIGIN 0 0 ;
  SIZE 42.000 BY 56.000 ;
  SYMMETRY X Y ;
  SITE TR1um_site ;
  PIN GND
    DIRECTION INOUT ;
    USE GROUND ;
    PORT
      LAYER M1 ;
        RECT -1.000 -1.000 7.000 14.300 ;
    END
  END GND
END RR$1
MACRO RS
  CLASS CORE ;
  ORIGIN 0 0 ;
  SIZE 23.600 BY 6.000 ;
  SYMMETRY X Y ;
  SITE TR1um_site ;
END RS
MACRO TIEHI
  CLASS CORE ;
  SITE TR1um_site ;
  ORIGIN 0 0 ;
  SIZE 8.000 BY 62.600 ;
  PIN HI
    DIRECTION OUTPUT ;
    USE SIGNAL ;
    PORT
      LAYER M1 ;
        RECT 2.500 45.500 5.500 48.500 ;
    END
  END HI
  PIN VDD
    DIRECTION INOUT ;
    USE POWER ;
    PORT
      LAYER M1 ;
        RECT -1.300 60.600 9.300 62.600 ;
    END
  END VDD
  PIN GND
    DIRECTION INOUT ;
    USE GROUND ;
    PORT
      LAYER M1 ;
        RECT -1.300 -1.300 9.300 0.300 ;
    END
  END GND
END TIEHI
MACRO TIELO
  CLASS CORE ;
  SITE TR1um_site ;
  ORIGIN 0 0 ;
  SIZE 8.000 BY 62.600 ;
  PIN LO
    DIRECTION OUTPUT ;
    USE SIGNAL ;
    PORT
      LAYER M1 ;
        RECT 2.500 14.100 5.500 17.100 ;
    END
  END LO
  PIN VDD
    DIRECTION INOUT ;
    USE POWER ;
    PORT
      LAYER M1 ;
        RECT -1.300 60.600 9.300 62.600 ;
    END
  END VDD
  PIN GND
    DIRECTION INOUT ;
    USE GROUND ;
    PORT
      LAYER M1 ;
        RECT -1.300 -1.300 9.300 0.300 ;
    END
  END GND
END TIELO
MACRO TOP
  CLASS CORE ;
  ORIGIN 0 0 ;
  SIZE 81.600 BY 56.000 ;
  SYMMETRY X Y ;
  SITE TR1um_site ;
  PIN GND
    DIRECTION INOUT ;
    USE GROUND ;
    PORT
      LAYER M1 ;
        RECT -1.000 -1.000 7.000 14.300 ;
    END
  END GND
END TOP
MACRO XNOR2
  CLASS CORE ;
  ORIGIN 0 0 ;
  SIZE 45.600 BY 62.600 ;
  SYMMETRY X Y ;
  SITE TR1um_site ;
  PIN Y
    DIRECTION OUTPUT ;
    USE SIGNAL ;
    PORT
      LAYER M1 ;
        RECT 21.100 6.400 21.500 9.800 ;
      LAYER M1 ;
        RECT 21.100 41.000 21.500 51.200 ;
      LAYER M1 ;
        RECT 21.500 6.400 23.300 16.800 ;
      LAYER M1 ;
        RECT 21.500 36.000 23.300 51.200 ;
      LAYER M1 ;
        RECT 23.300 6.400 23.700 9.800 ;
      LAYER M1 ;
        RECT 23.300 15.000 23.700 16.800 ;
      LAYER M1 ;
        RECT 23.300 36.000 23.700 37.800 ;
      LAYER M1 ;
        RECT 23.300 41.000 23.700 51.200 ;
      LAYER M1 ;
        RECT 23.700 15.000 32.100 16.800 ;
      LAYER M1 ;
        RECT 23.700 36.000 32.100 37.800 ;
      LAYER M1 ;
        RECT 32.100 15.000 33.100 16.800 ;
      LAYER M1 ;
        RECT 32.100 32.600 33.100 37.800 ;
      LAYER M1 ;
        RECT 33.100 15.000 33.700 16.800 ;
      LAYER M1 ;
        RECT 33.100 32.600 33.700 37.800 ;
      LAYER M1 ;
        RECT 33.100 41.000 33.700 51.200 ;
      LAYER M1 ;
        RECT 33.700 15.000 35.500 16.800 ;
      LAYER M1 ;
        RECT 33.700 32.600 35.500 51.200 ;
      LAYER M1 ;
        RECT 35.500 15.000 35.700 16.800 ;
      LAYER M1 ;
        RECT 35.500 32.600 35.700 34.400 ;
      LAYER M1 ;
        RECT 35.500 41.000 35.700 51.200 ;
      LAYER M1 ;
        RECT 35.700 15.000 36.800 16.800 ;
      LAYER M1 ;
        RECT 35.700 32.600 36.800 34.400 ;
      LAYER M1 ;
        RECT 36.800 15.000 38.600 34.400 ;
    END
  END Y
  PIN A
    DIRECTION INPUT ;
    USE SIGNAL ;
    PORT
      LAYER M1 ;
        RECT 10.300 20.100 12.900 22.700 ;
      LAYER M1 ;
        RECT 12.900 20.600 15.600 22.400 ;
      LAYER M1 ;
        RECT 15.600 20.600 19.000 25.000 ;
      LAYER M1 ;
        RECT 19.000 20.600 30.300 22.400 ;
      LAYER M1 ;
        RECT 30.300 19.000 32.900 22.400 ;
    END
  END A
  PIN B
    DIRECTION INPUT ;
    USE SIGNAL ;
    PORT
      LAYER M1 ;
        RECT 15.900 26.600 18.500 29.200 ;
      LAYER M1 ;
        RECT 18.500 26.600 26.300 28.400 ;
      LAYER M1 ;
        RECT 26.300 23.800 30.000 30.500 ;
    END
  END B
  PIN VDD
    DIRECTION INOUT ;
    USE POWER ;
    PORT
      LAYER M1 ;
        RECT 5.000 55.000 13.100 57.600 ;
      LAYER M1 ;
        RECT 13.100 41.000 15.700 57.600 ;
      LAYER M1 ;
        RECT 15.700 55.000 25.100 57.600 ;
      LAYER M1 ;
        RECT 25.100 41.000 27.700 57.600 ;
      LAYER M1 ;
        RECT 27.700 55.000 40.600 57.600 ;
    END
  END VDD
  PIN GND
    DIRECTION INOUT ;
    USE GROUND ;
    PORT
      LAYER M1 ;
        RECT 5.000 0.000 9.100 2.600 ;
      LAYER M1 ;
        RECT 9.100 0.000 11.700 9.800 ;
      LAYER M1 ;
        RECT 11.700 0.000 29.100 2.600 ;
      LAYER M1 ;
        RECT 29.100 0.000 31.700 9.800 ;
      LAYER M1 ;
        RECT 31.700 0.000 40.600 2.600 ;
    END
  END GND
END XNOR2
MACRO XOR2
  CLASS CORE ;
  ORIGIN 0 0 ;
  SIZE 45.600 BY 62.600 ;
  SYMMETRY X Y ;
  SITE TR1um_site ;
  PIN Y
    DIRECTION OUTPUT ;
    USE SIGNAL ;
    PORT
      LAYER M1 ;
        RECT 21.100 6.400 21.500 9.800 ;
      LAYER M1 ;
        RECT 21.100 41.000 21.500 51.200 ;
      LAYER M1 ;
        RECT 21.500 6.400 23.300 16.800 ;
      LAYER M1 ;
        RECT 21.500 32.600 23.300 51.200 ;
      LAYER M1 ;
        RECT 23.300 6.400 23.700 9.800 ;
      LAYER M1 ;
        RECT 23.300 15.000 23.700 16.800 ;
      LAYER M1 ;
        RECT 23.300 32.600 23.700 34.400 ;
      LAYER M1 ;
        RECT 23.300 41.000 23.700 51.200 ;
      LAYER M1 ;
        RECT 23.700 15.000 32.100 16.800 ;
      LAYER M1 ;
        RECT 23.700 32.600 32.100 34.400 ;
      LAYER M1 ;
        RECT 32.100 15.000 33.100 16.800 ;
      LAYER M1 ;
        RECT 32.100 32.600 33.100 36.000 ;
      LAYER M1 ;
        RECT 33.100 6.400 33.500 9.800 ;
      LAYER M1 ;
        RECT 33.100 15.000 33.500 16.800 ;
      LAYER M1 ;
        RECT 33.100 32.600 33.500 36.000 ;
      LAYER M1 ;
        RECT 33.500 6.400 35.300 16.800 ;
      LAYER M1 ;
        RECT 33.500 32.600 35.300 36.000 ;
      LAYER M1 ;
        RECT 35.300 6.400 35.500 9.800 ;
      LAYER M1 ;
        RECT 35.300 15.000 35.500 16.800 ;
      LAYER M1 ;
        RECT 35.300 32.600 35.500 36.000 ;
      LAYER M1 ;
        RECT 35.500 6.400 35.700 9.800 ;
      LAYER M1 ;
        RECT 35.500 15.000 35.700 16.800 ;
      LAYER M1 ;
        RECT 35.500 32.600 35.700 34.400 ;
      LAYER M1 ;
        RECT 35.700 15.000 36.800 16.800 ;
      LAYER M1 ;
        RECT 35.700 32.600 36.800 34.400 ;
      LAYER M1 ;
        RECT 36.800 15.000 38.600 34.400 ;
    END
  END Y
  PIN A
    DIRECTION INPUT ;
    USE SIGNAL ;
    PORT
      LAYER M1 ;
        RECT 10.300 20.100 12.900 22.700 ;
      LAYER M1 ;
        RECT 12.900 20.600 15.600 22.400 ;
      LAYER M1 ;
        RECT 15.600 20.600 19.000 25.000 ;
      LAYER M1 ;
        RECT 19.000 20.600 30.300 22.400 ;
      LAYER M1 ;
        RECT 30.300 19.000 32.900 22.400 ;
    END
  END A
  PIN B
    DIRECTION INPUT ;
    USE SIGNAL ;
    PORT
      LAYER M1 ;
        RECT 15.900 26.600 18.500 29.200 ;
      LAYER M1 ;
        RECT 18.500 26.600 26.300 28.400 ;
      LAYER M1 ;
        RECT 26.300 23.800 30.000 30.500 ;
    END
  END B
  PIN VDD
    DIRECTION INOUT ;
    USE POWER ;
    PORT
      LAYER M1 ;
        RECT 5.000 55.000 9.100 57.600 ;
      LAYER M1 ;
        RECT 9.100 41.000 11.700 57.600 ;
      LAYER M1 ;
        RECT 11.700 55.000 29.100 57.600 ;
      LAYER M1 ;
        RECT 29.100 41.000 31.700 57.600 ;
      LAYER M1 ;
        RECT 31.700 55.000 40.600 57.600 ;
    END
  END VDD
  PIN GND
    DIRECTION INOUT ;
    USE GROUND ;
    PORT
      LAYER M1 ;
        RECT 5.000 0.000 13.100 2.600 ;
      LAYER M1 ;
        RECT 13.100 0.000 15.700 9.800 ;
      LAYER M1 ;
        RECT 15.700 0.000 25.100 2.600 ;
      LAYER M1 ;
        RECT 25.100 0.000 27.700 9.800 ;
      LAYER M1 ;
        RECT 27.700 0.000 40.600 2.600 ;
    END
  END GND
END XOR2
END LIBRARY
